VERSION 5.7 ;
BUSBITCHARS "[]" ;
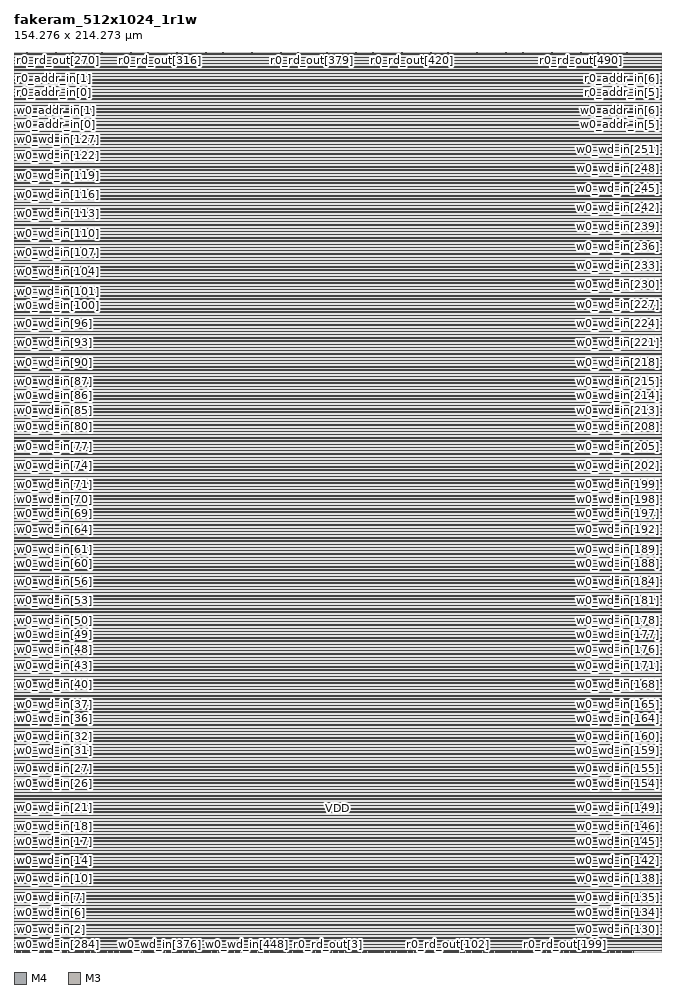
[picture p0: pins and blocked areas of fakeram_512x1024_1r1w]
MACRO fakeram_512x1024_1r1w
  FOREIGN fakeram_512x1024_1r1w 0 0 ;
  SYMMETRY X Y R90 ;
  SIZE 154.276 BY 214.273 ;
  CLASS BLOCK ;
  PIN w0_wd_in[0]
    DIRECTION INPUT ;
    USE SIGNAL ;
    SHAPE ABUTMENT ;
    PORT
      LAYER M4 ;
      RECT 0.000 0.276 0.072 0.300 ;
    END
  END w0_wd_in[0]
  PIN w0_wd_in[1]
    DIRECTION INPUT ;
    USE SIGNAL ;
    SHAPE ABUTMENT ;
    PORT
      LAYER M4 ;
      RECT 0.000 1.812 0.072 1.836 ;
    END
  END w0_wd_in[1]
  PIN w0_wd_in[2]
    DIRECTION INPUT ;
    USE SIGNAL ;
    SHAPE ABUTMENT ;
    PORT
      LAYER M4 ;
      RECT 0.000 3.348 0.072 3.372 ;
    END
  END w0_wd_in[2]
  PIN w0_wd_in[3]
    DIRECTION INPUT ;
    USE SIGNAL ;
    SHAPE ABUTMENT ;
    PORT
      LAYER M4 ;
      RECT 0.000 4.884 0.072 4.908 ;
    END
  END w0_wd_in[3]
  PIN w0_wd_in[4]
    DIRECTION INPUT ;
    USE SIGNAL ;
    SHAPE ABUTMENT ;
    PORT
      LAYER M4 ;
      RECT 0.000 6.420 0.072 6.444 ;
    END
  END w0_wd_in[4]
  PIN w0_wd_in[5]
    DIRECTION INPUT ;
    USE SIGNAL ;
    SHAPE ABUTMENT ;
    PORT
      LAYER M4 ;
      RECT 0.000 7.956 0.072 7.980 ;
    END
  END w0_wd_in[5]
  PIN w0_wd_in[6]
    DIRECTION INPUT ;
    USE SIGNAL ;
    SHAPE ABUTMENT ;
    PORT
      LAYER M4 ;
      RECT 0.000 9.492 0.072 9.516 ;
    END
  END w0_wd_in[6]
  PIN w0_wd_in[7]
    DIRECTION INPUT ;
    USE SIGNAL ;
    SHAPE ABUTMENT ;
    PORT
      LAYER M4 ;
      RECT 0.000 11.028 0.072 11.052 ;
    END
  END w0_wd_in[7]
  PIN w0_wd_in[8]
    DIRECTION INPUT ;
    USE SIGNAL ;
    SHAPE ABUTMENT ;
    PORT
      LAYER M4 ;
      RECT 0.000 12.564 0.072 12.588 ;
    END
  END w0_wd_in[8]
  PIN w0_wd_in[9]
    DIRECTION INPUT ;
    USE SIGNAL ;
    SHAPE ABUTMENT ;
    PORT
      LAYER M4 ;
      RECT 0.000 14.100 0.072 14.124 ;
    END
  END w0_wd_in[9]
  PIN w0_wd_in[10]
    DIRECTION INPUT ;
    USE SIGNAL ;
    SHAPE ABUTMENT ;
    PORT
      LAYER M4 ;
      RECT 0.000 15.636 0.072 15.660 ;
    END
  END w0_wd_in[10]
  PIN w0_wd_in[11]
    DIRECTION INPUT ;
    USE SIGNAL ;
    SHAPE ABUTMENT ;
    PORT
      LAYER M4 ;
      RECT 0.000 17.172 0.072 17.196 ;
    END
  END w0_wd_in[11]
  PIN w0_wd_in[12]
    DIRECTION INPUT ;
    USE SIGNAL ;
    SHAPE ABUTMENT ;
    PORT
      LAYER M4 ;
      RECT 0.000 18.708 0.072 18.732 ;
    END
  END w0_wd_in[12]
  PIN w0_wd_in[13]
    DIRECTION INPUT ;
    USE SIGNAL ;
    SHAPE ABUTMENT ;
    PORT
      LAYER M4 ;
      RECT 0.000 20.244 0.072 20.268 ;
    END
  END w0_wd_in[13]
  PIN w0_wd_in[14]
    DIRECTION INPUT ;
    USE SIGNAL ;
    SHAPE ABUTMENT ;
    PORT
      LAYER M4 ;
      RECT 0.000 21.780 0.072 21.804 ;
    END
  END w0_wd_in[14]
  PIN w0_wd_in[15]
    DIRECTION INPUT ;
    USE SIGNAL ;
    SHAPE ABUTMENT ;
    PORT
      LAYER M4 ;
      RECT 0.000 23.316 0.072 23.340 ;
    END
  END w0_wd_in[15]
  PIN w0_wd_in[16]
    DIRECTION INPUT ;
    USE SIGNAL ;
    SHAPE ABUTMENT ;
    PORT
      LAYER M4 ;
      RECT 0.000 24.852 0.072 24.876 ;
    END
  END w0_wd_in[16]
  PIN w0_wd_in[17]
    DIRECTION INPUT ;
    USE SIGNAL ;
    SHAPE ABUTMENT ;
    PORT
      LAYER M4 ;
      RECT 0.000 26.388 0.072 26.412 ;
    END
  END w0_wd_in[17]
  PIN w0_wd_in[18]
    DIRECTION INPUT ;
    USE SIGNAL ;
    SHAPE ABUTMENT ;
    PORT
      LAYER M4 ;
      RECT 0.000 27.924 0.072 27.948 ;
    END
  END w0_wd_in[18]
  PIN w0_wd_in[19]
    DIRECTION INPUT ;
    USE SIGNAL ;
    SHAPE ABUTMENT ;
    PORT
      LAYER M4 ;
      RECT 0.000 29.460 0.072 29.484 ;
    END
  END w0_wd_in[19]
  PIN w0_wd_in[20]
    DIRECTION INPUT ;
    USE SIGNAL ;
    SHAPE ABUTMENT ;
    PORT
      LAYER M4 ;
      RECT 0.000 30.996 0.072 31.020 ;
    END
  END w0_wd_in[20]
  PIN w0_wd_in[21]
    DIRECTION INPUT ;
    USE SIGNAL ;
    SHAPE ABUTMENT ;
    PORT
      LAYER M4 ;
      RECT 0.000 32.532 0.072 32.556 ;
    END
  END w0_wd_in[21]
  PIN w0_wd_in[22]
    DIRECTION INPUT ;
    USE SIGNAL ;
    SHAPE ABUTMENT ;
    PORT
      LAYER M4 ;
      RECT 0.000 34.068 0.072 34.092 ;
    END
  END w0_wd_in[22]
  PIN w0_wd_in[23]
    DIRECTION INPUT ;
    USE SIGNAL ;
    SHAPE ABUTMENT ;
    PORT
      LAYER M4 ;
      RECT 0.000 35.604 0.072 35.628 ;
    END
  END w0_wd_in[23]
  PIN w0_wd_in[24]
    DIRECTION INPUT ;
    USE SIGNAL ;
    SHAPE ABUTMENT ;
    PORT
      LAYER M4 ;
      RECT 0.000 37.140 0.072 37.164 ;
    END
  END w0_wd_in[24]
  PIN w0_wd_in[25]
    DIRECTION INPUT ;
    USE SIGNAL ;
    SHAPE ABUTMENT ;
    PORT
      LAYER M4 ;
      RECT 0.000 38.676 0.072 38.700 ;
    END
  END w0_wd_in[25]
  PIN w0_wd_in[26]
    DIRECTION INPUT ;
    USE SIGNAL ;
    SHAPE ABUTMENT ;
    PORT
      LAYER M4 ;
      RECT 0.000 40.212 0.072 40.236 ;
    END
  END w0_wd_in[26]
  PIN w0_wd_in[27]
    DIRECTION INPUT ;
    USE SIGNAL ;
    SHAPE ABUTMENT ;
    PORT
      LAYER M4 ;
      RECT 0.000 41.748 0.072 41.772 ;
    END
  END w0_wd_in[27]
  PIN w0_wd_in[28]
    DIRECTION INPUT ;
    USE SIGNAL ;
    SHAPE ABUTMENT ;
    PORT
      LAYER M4 ;
      RECT 0.000 43.284 0.072 43.308 ;
    END
  END w0_wd_in[28]
  PIN w0_wd_in[29]
    DIRECTION INPUT ;
    USE SIGNAL ;
    SHAPE ABUTMENT ;
    PORT
      LAYER M4 ;
      RECT 0.000 44.820 0.072 44.844 ;
    END
  END w0_wd_in[29]
  PIN w0_wd_in[30]
    DIRECTION INPUT ;
    USE SIGNAL ;
    SHAPE ABUTMENT ;
    PORT
      LAYER M4 ;
      RECT 0.000 46.356 0.072 46.380 ;
    END
  END w0_wd_in[30]
  PIN w0_wd_in[31]
    DIRECTION INPUT ;
    USE SIGNAL ;
    SHAPE ABUTMENT ;
    PORT
      LAYER M4 ;
      RECT 0.000 47.892 0.072 47.916 ;
    END
  END w0_wd_in[31]
  PIN w0_wd_in[32]
    DIRECTION INPUT ;
    USE SIGNAL ;
    SHAPE ABUTMENT ;
    PORT
      LAYER M4 ;
      RECT 0.000 49.428 0.072 49.452 ;
    END
  END w0_wd_in[32]
  PIN w0_wd_in[33]
    DIRECTION INPUT ;
    USE SIGNAL ;
    SHAPE ABUTMENT ;
    PORT
      LAYER M4 ;
      RECT 0.000 50.964 0.072 50.988 ;
    END
  END w0_wd_in[33]
  PIN w0_wd_in[34]
    DIRECTION INPUT ;
    USE SIGNAL ;
    SHAPE ABUTMENT ;
    PORT
      LAYER M4 ;
      RECT 0.000 52.500 0.072 52.524 ;
    END
  END w0_wd_in[34]
  PIN w0_wd_in[35]
    DIRECTION INPUT ;
    USE SIGNAL ;
    SHAPE ABUTMENT ;
    PORT
      LAYER M4 ;
      RECT 0.000 54.036 0.072 54.060 ;
    END
  END w0_wd_in[35]
  PIN w0_wd_in[36]
    DIRECTION INPUT ;
    USE SIGNAL ;
    SHAPE ABUTMENT ;
    PORT
      LAYER M4 ;
      RECT 0.000 55.572 0.072 55.596 ;
    END
  END w0_wd_in[36]
  PIN w0_wd_in[37]
    DIRECTION INPUT ;
    USE SIGNAL ;
    SHAPE ABUTMENT ;
    PORT
      LAYER M4 ;
      RECT 0.000 57.108 0.072 57.132 ;
    END
  END w0_wd_in[37]
  PIN w0_wd_in[38]
    DIRECTION INPUT ;
    USE SIGNAL ;
    SHAPE ABUTMENT ;
    PORT
      LAYER M4 ;
      RECT 0.000 58.644 0.072 58.668 ;
    END
  END w0_wd_in[38]
  PIN w0_wd_in[39]
    DIRECTION INPUT ;
    USE SIGNAL ;
    SHAPE ABUTMENT ;
    PORT
      LAYER M4 ;
      RECT 0.000 60.180 0.072 60.204 ;
    END
  END w0_wd_in[39]
  PIN w0_wd_in[40]
    DIRECTION INPUT ;
    USE SIGNAL ;
    SHAPE ABUTMENT ;
    PORT
      LAYER M4 ;
      RECT 0.000 61.716 0.072 61.740 ;
    END
  END w0_wd_in[40]
  PIN w0_wd_in[41]
    DIRECTION INPUT ;
    USE SIGNAL ;
    SHAPE ABUTMENT ;
    PORT
      LAYER M4 ;
      RECT 0.000 63.252 0.072 63.276 ;
    END
  END w0_wd_in[41]
  PIN w0_wd_in[42]
    DIRECTION INPUT ;
    USE SIGNAL ;
    SHAPE ABUTMENT ;
    PORT
      LAYER M4 ;
      RECT 0.000 64.788 0.072 64.812 ;
    END
  END w0_wd_in[42]
  PIN w0_wd_in[43]
    DIRECTION INPUT ;
    USE SIGNAL ;
    SHAPE ABUTMENT ;
    PORT
      LAYER M4 ;
      RECT 0.000 66.324 0.072 66.348 ;
    END
  END w0_wd_in[43]
  PIN w0_wd_in[44]
    DIRECTION INPUT ;
    USE SIGNAL ;
    SHAPE ABUTMENT ;
    PORT
      LAYER M4 ;
      RECT 0.000 67.860 0.072 67.884 ;
    END
  END w0_wd_in[44]
  PIN w0_wd_in[45]
    DIRECTION INPUT ;
    USE SIGNAL ;
    SHAPE ABUTMENT ;
    PORT
      LAYER M4 ;
      RECT 0.000 69.396 0.072 69.420 ;
    END
  END w0_wd_in[45]
  PIN w0_wd_in[46]
    DIRECTION INPUT ;
    USE SIGNAL ;
    SHAPE ABUTMENT ;
    PORT
      LAYER M4 ;
      RECT 0.000 70.932 0.072 70.956 ;
    END
  END w0_wd_in[46]
  PIN w0_wd_in[47]
    DIRECTION INPUT ;
    USE SIGNAL ;
    SHAPE ABUTMENT ;
    PORT
      LAYER M4 ;
      RECT 0.000 72.468 0.072 72.492 ;
    END
  END w0_wd_in[47]
  PIN w0_wd_in[48]
    DIRECTION INPUT ;
    USE SIGNAL ;
    SHAPE ABUTMENT ;
    PORT
      LAYER M4 ;
      RECT 0.000 74.004 0.072 74.028 ;
    END
  END w0_wd_in[48]
  PIN w0_wd_in[49]
    DIRECTION INPUT ;
    USE SIGNAL ;
    SHAPE ABUTMENT ;
    PORT
      LAYER M4 ;
      RECT 0.000 75.540 0.072 75.564 ;
    END
  END w0_wd_in[49]
  PIN w0_wd_in[50]
    DIRECTION INPUT ;
    USE SIGNAL ;
    SHAPE ABUTMENT ;
    PORT
      LAYER M4 ;
      RECT 0.000 77.076 0.072 77.100 ;
    END
  END w0_wd_in[50]
  PIN w0_wd_in[51]
    DIRECTION INPUT ;
    USE SIGNAL ;
    SHAPE ABUTMENT ;
    PORT
      LAYER M4 ;
      RECT 0.000 78.612 0.072 78.636 ;
    END
  END w0_wd_in[51]
  PIN w0_wd_in[52]
    DIRECTION INPUT ;
    USE SIGNAL ;
    SHAPE ABUTMENT ;
    PORT
      LAYER M4 ;
      RECT 0.000 80.148 0.072 80.172 ;
    END
  END w0_wd_in[52]
  PIN w0_wd_in[53]
    DIRECTION INPUT ;
    USE SIGNAL ;
    SHAPE ABUTMENT ;
    PORT
      LAYER M4 ;
      RECT 0.000 81.684 0.072 81.708 ;
    END
  END w0_wd_in[53]
  PIN w0_wd_in[54]
    DIRECTION INPUT ;
    USE SIGNAL ;
    SHAPE ABUTMENT ;
    PORT
      LAYER M4 ;
      RECT 0.000 83.220 0.072 83.244 ;
    END
  END w0_wd_in[54]
  PIN w0_wd_in[55]
    DIRECTION INPUT ;
    USE SIGNAL ;
    SHAPE ABUTMENT ;
    PORT
      LAYER M4 ;
      RECT 0.000 84.756 0.072 84.780 ;
    END
  END w0_wd_in[55]
  PIN w0_wd_in[56]
    DIRECTION INPUT ;
    USE SIGNAL ;
    SHAPE ABUTMENT ;
    PORT
      LAYER M4 ;
      RECT 0.000 86.292 0.072 86.316 ;
    END
  END w0_wd_in[56]
  PIN w0_wd_in[57]
    DIRECTION INPUT ;
    USE SIGNAL ;
    SHAPE ABUTMENT ;
    PORT
      LAYER M4 ;
      RECT 0.000 87.828 0.072 87.852 ;
    END
  END w0_wd_in[57]
  PIN w0_wd_in[58]
    DIRECTION INPUT ;
    USE SIGNAL ;
    SHAPE ABUTMENT ;
    PORT
      LAYER M4 ;
      RECT 0.000 89.364 0.072 89.388 ;
    END
  END w0_wd_in[58]
  PIN w0_wd_in[59]
    DIRECTION INPUT ;
    USE SIGNAL ;
    SHAPE ABUTMENT ;
    PORT
      LAYER M4 ;
      RECT 0.000 90.900 0.072 90.924 ;
    END
  END w0_wd_in[59]
  PIN w0_wd_in[60]
    DIRECTION INPUT ;
    USE SIGNAL ;
    SHAPE ABUTMENT ;
    PORT
      LAYER M4 ;
      RECT 0.000 92.436 0.072 92.460 ;
    END
  END w0_wd_in[60]
  PIN w0_wd_in[61]
    DIRECTION INPUT ;
    USE SIGNAL ;
    SHAPE ABUTMENT ;
    PORT
      LAYER M4 ;
      RECT 0.000 93.972 0.072 93.996 ;
    END
  END w0_wd_in[61]
  PIN w0_wd_in[62]
    DIRECTION INPUT ;
    USE SIGNAL ;
    SHAPE ABUTMENT ;
    PORT
      LAYER M4 ;
      RECT 0.000 95.508 0.072 95.532 ;
    END
  END w0_wd_in[62]
  PIN w0_wd_in[63]
    DIRECTION INPUT ;
    USE SIGNAL ;
    SHAPE ABUTMENT ;
    PORT
      LAYER M4 ;
      RECT 0.000 97.044 0.072 97.068 ;
    END
  END w0_wd_in[63]
  PIN w0_wd_in[64]
    DIRECTION INPUT ;
    USE SIGNAL ;
    SHAPE ABUTMENT ;
    PORT
      LAYER M4 ;
      RECT 0.000 98.580 0.072 98.604 ;
    END
  END w0_wd_in[64]
  PIN w0_wd_in[65]
    DIRECTION INPUT ;
    USE SIGNAL ;
    SHAPE ABUTMENT ;
    PORT
      LAYER M4 ;
      RECT 0.000 100.116 0.072 100.140 ;
    END
  END w0_wd_in[65]
  PIN w0_wd_in[66]
    DIRECTION INPUT ;
    USE SIGNAL ;
    SHAPE ABUTMENT ;
    PORT
      LAYER M4 ;
      RECT 0.000 101.652 0.072 101.676 ;
    END
  END w0_wd_in[66]
  PIN w0_wd_in[67]
    DIRECTION INPUT ;
    USE SIGNAL ;
    SHAPE ABUTMENT ;
    PORT
      LAYER M4 ;
      RECT 0.000 103.188 0.072 103.212 ;
    END
  END w0_wd_in[67]
  PIN w0_wd_in[68]
    DIRECTION INPUT ;
    USE SIGNAL ;
    SHAPE ABUTMENT ;
    PORT
      LAYER M4 ;
      RECT 0.000 104.724 0.072 104.748 ;
    END
  END w0_wd_in[68]
  PIN w0_wd_in[69]
    DIRECTION INPUT ;
    USE SIGNAL ;
    SHAPE ABUTMENT ;
    PORT
      LAYER M4 ;
      RECT 0.000 106.260 0.072 106.284 ;
    END
  END w0_wd_in[69]
  PIN w0_wd_in[70]
    DIRECTION INPUT ;
    USE SIGNAL ;
    SHAPE ABUTMENT ;
    PORT
      LAYER M4 ;
      RECT 0.000 107.796 0.072 107.820 ;
    END
  END w0_wd_in[70]
  PIN w0_wd_in[71]
    DIRECTION INPUT ;
    USE SIGNAL ;
    SHAPE ABUTMENT ;
    PORT
      LAYER M4 ;
      RECT 0.000 109.332 0.072 109.356 ;
    END
  END w0_wd_in[71]
  PIN w0_wd_in[72]
    DIRECTION INPUT ;
    USE SIGNAL ;
    SHAPE ABUTMENT ;
    PORT
      LAYER M4 ;
      RECT 0.000 110.868 0.072 110.892 ;
    END
  END w0_wd_in[72]
  PIN w0_wd_in[73]
    DIRECTION INPUT ;
    USE SIGNAL ;
    SHAPE ABUTMENT ;
    PORT
      LAYER M4 ;
      RECT 0.000 112.404 0.072 112.428 ;
    END
  END w0_wd_in[73]
  PIN w0_wd_in[74]
    DIRECTION INPUT ;
    USE SIGNAL ;
    SHAPE ABUTMENT ;
    PORT
      LAYER M4 ;
      RECT 0.000 113.940 0.072 113.964 ;
    END
  END w0_wd_in[74]
  PIN w0_wd_in[75]
    DIRECTION INPUT ;
    USE SIGNAL ;
    SHAPE ABUTMENT ;
    PORT
      LAYER M4 ;
      RECT 0.000 115.476 0.072 115.500 ;
    END
  END w0_wd_in[75]
  PIN w0_wd_in[76]
    DIRECTION INPUT ;
    USE SIGNAL ;
    SHAPE ABUTMENT ;
    PORT
      LAYER M4 ;
      RECT 0.000 117.012 0.072 117.036 ;
    END
  END w0_wd_in[76]
  PIN w0_wd_in[77]
    DIRECTION INPUT ;
    USE SIGNAL ;
    SHAPE ABUTMENT ;
    PORT
      LAYER M4 ;
      RECT 0.000 118.548 0.072 118.572 ;
    END
  END w0_wd_in[77]
  PIN w0_wd_in[78]
    DIRECTION INPUT ;
    USE SIGNAL ;
    SHAPE ABUTMENT ;
    PORT
      LAYER M4 ;
      RECT 0.000 120.084 0.072 120.108 ;
    END
  END w0_wd_in[78]
  PIN w0_wd_in[79]
    DIRECTION INPUT ;
    USE SIGNAL ;
    SHAPE ABUTMENT ;
    PORT
      LAYER M4 ;
      RECT 0.000 121.620 0.072 121.644 ;
    END
  END w0_wd_in[79]
  PIN w0_wd_in[80]
    DIRECTION INPUT ;
    USE SIGNAL ;
    SHAPE ABUTMENT ;
    PORT
      LAYER M4 ;
      RECT 0.000 123.156 0.072 123.180 ;
    END
  END w0_wd_in[80]
  PIN w0_wd_in[81]
    DIRECTION INPUT ;
    USE SIGNAL ;
    SHAPE ABUTMENT ;
    PORT
      LAYER M4 ;
      RECT 0.000 124.692 0.072 124.716 ;
    END
  END w0_wd_in[81]
  PIN w0_wd_in[82]
    DIRECTION INPUT ;
    USE SIGNAL ;
    SHAPE ABUTMENT ;
    PORT
      LAYER M4 ;
      RECT 0.000 126.228 0.072 126.252 ;
    END
  END w0_wd_in[82]
  PIN w0_wd_in[83]
    DIRECTION INPUT ;
    USE SIGNAL ;
    SHAPE ABUTMENT ;
    PORT
      LAYER M4 ;
      RECT 0.000 127.764 0.072 127.788 ;
    END
  END w0_wd_in[83]
  PIN w0_wd_in[84]
    DIRECTION INPUT ;
    USE SIGNAL ;
    SHAPE ABUTMENT ;
    PORT
      LAYER M4 ;
      RECT 0.000 129.300 0.072 129.324 ;
    END
  END w0_wd_in[84]
  PIN w0_wd_in[85]
    DIRECTION INPUT ;
    USE SIGNAL ;
    SHAPE ABUTMENT ;
    PORT
      LAYER M4 ;
      RECT 0.000 130.836 0.072 130.860 ;
    END
  END w0_wd_in[85]
  PIN w0_wd_in[86]
    DIRECTION INPUT ;
    USE SIGNAL ;
    SHAPE ABUTMENT ;
    PORT
      LAYER M4 ;
      RECT 0.000 132.372 0.072 132.396 ;
    END
  END w0_wd_in[86]
  PIN w0_wd_in[87]
    DIRECTION INPUT ;
    USE SIGNAL ;
    SHAPE ABUTMENT ;
    PORT
      LAYER M4 ;
      RECT 0.000 133.908 0.072 133.932 ;
    END
  END w0_wd_in[87]
  PIN w0_wd_in[88]
    DIRECTION INPUT ;
    USE SIGNAL ;
    SHAPE ABUTMENT ;
    PORT
      LAYER M4 ;
      RECT 0.000 135.444 0.072 135.468 ;
    END
  END w0_wd_in[88]
  PIN w0_wd_in[89]
    DIRECTION INPUT ;
    USE SIGNAL ;
    SHAPE ABUTMENT ;
    PORT
      LAYER M4 ;
      RECT 0.000 136.980 0.072 137.004 ;
    END
  END w0_wd_in[89]
  PIN w0_wd_in[90]
    DIRECTION INPUT ;
    USE SIGNAL ;
    SHAPE ABUTMENT ;
    PORT
      LAYER M4 ;
      RECT 0.000 138.516 0.072 138.540 ;
    END
  END w0_wd_in[90]
  PIN w0_wd_in[91]
    DIRECTION INPUT ;
    USE SIGNAL ;
    SHAPE ABUTMENT ;
    PORT
      LAYER M4 ;
      RECT 0.000 140.052 0.072 140.076 ;
    END
  END w0_wd_in[91]
  PIN w0_wd_in[92]
    DIRECTION INPUT ;
    USE SIGNAL ;
    SHAPE ABUTMENT ;
    PORT
      LAYER M4 ;
      RECT 0.000 141.588 0.072 141.612 ;
    END
  END w0_wd_in[92]
  PIN w0_wd_in[93]
    DIRECTION INPUT ;
    USE SIGNAL ;
    SHAPE ABUTMENT ;
    PORT
      LAYER M4 ;
      RECT 0.000 143.124 0.072 143.148 ;
    END
  END w0_wd_in[93]
  PIN w0_wd_in[94]
    DIRECTION INPUT ;
    USE SIGNAL ;
    SHAPE ABUTMENT ;
    PORT
      LAYER M4 ;
      RECT 0.000 144.660 0.072 144.684 ;
    END
  END w0_wd_in[94]
  PIN w0_wd_in[95]
    DIRECTION INPUT ;
    USE SIGNAL ;
    SHAPE ABUTMENT ;
    PORT
      LAYER M4 ;
      RECT 0.000 146.196 0.072 146.220 ;
    END
  END w0_wd_in[95]
  PIN w0_wd_in[96]
    DIRECTION INPUT ;
    USE SIGNAL ;
    SHAPE ABUTMENT ;
    PORT
      LAYER M4 ;
      RECT 0.000 147.732 0.072 147.756 ;
    END
  END w0_wd_in[96]
  PIN w0_wd_in[97]
    DIRECTION INPUT ;
    USE SIGNAL ;
    SHAPE ABUTMENT ;
    PORT
      LAYER M4 ;
      RECT 0.000 149.268 0.072 149.292 ;
    END
  END w0_wd_in[97]
  PIN w0_wd_in[98]
    DIRECTION INPUT ;
    USE SIGNAL ;
    SHAPE ABUTMENT ;
    PORT
      LAYER M4 ;
      RECT 0.000 150.804 0.072 150.828 ;
    END
  END w0_wd_in[98]
  PIN w0_wd_in[99]
    DIRECTION INPUT ;
    USE SIGNAL ;
    SHAPE ABUTMENT ;
    PORT
      LAYER M4 ;
      RECT 0.000 152.340 0.072 152.364 ;
    END
  END w0_wd_in[99]
  PIN w0_wd_in[100]
    DIRECTION INPUT ;
    USE SIGNAL ;
    SHAPE ABUTMENT ;
    PORT
      LAYER M4 ;
      RECT 0.000 153.876 0.072 153.900 ;
    END
  END w0_wd_in[100]
  PIN w0_wd_in[101]
    DIRECTION INPUT ;
    USE SIGNAL ;
    SHAPE ABUTMENT ;
    PORT
      LAYER M4 ;
      RECT 0.000 155.412 0.072 155.436 ;
    END
  END w0_wd_in[101]
  PIN w0_wd_in[102]
    DIRECTION INPUT ;
    USE SIGNAL ;
    SHAPE ABUTMENT ;
    PORT
      LAYER M4 ;
      RECT 0.000 156.948 0.072 156.972 ;
    END
  END w0_wd_in[102]
  PIN w0_wd_in[103]
    DIRECTION INPUT ;
    USE SIGNAL ;
    SHAPE ABUTMENT ;
    PORT
      LAYER M4 ;
      RECT 0.000 158.484 0.072 158.508 ;
    END
  END w0_wd_in[103]
  PIN w0_wd_in[104]
    DIRECTION INPUT ;
    USE SIGNAL ;
    SHAPE ABUTMENT ;
    PORT
      LAYER M4 ;
      RECT 0.000 160.020 0.072 160.044 ;
    END
  END w0_wd_in[104]
  PIN w0_wd_in[105]
    DIRECTION INPUT ;
    USE SIGNAL ;
    SHAPE ABUTMENT ;
    PORT
      LAYER M4 ;
      RECT 0.000 161.556 0.072 161.580 ;
    END
  END w0_wd_in[105]
  PIN w0_wd_in[106]
    DIRECTION INPUT ;
    USE SIGNAL ;
    SHAPE ABUTMENT ;
    PORT
      LAYER M4 ;
      RECT 0.000 163.092 0.072 163.116 ;
    END
  END w0_wd_in[106]
  PIN w0_wd_in[107]
    DIRECTION INPUT ;
    USE SIGNAL ;
    SHAPE ABUTMENT ;
    PORT
      LAYER M4 ;
      RECT 0.000 164.628 0.072 164.652 ;
    END
  END w0_wd_in[107]
  PIN w0_wd_in[108]
    DIRECTION INPUT ;
    USE SIGNAL ;
    SHAPE ABUTMENT ;
    PORT
      LAYER M4 ;
      RECT 0.000 166.164 0.072 166.188 ;
    END
  END w0_wd_in[108]
  PIN w0_wd_in[109]
    DIRECTION INPUT ;
    USE SIGNAL ;
    SHAPE ABUTMENT ;
    PORT
      LAYER M4 ;
      RECT 0.000 167.700 0.072 167.724 ;
    END
  END w0_wd_in[109]
  PIN w0_wd_in[110]
    DIRECTION INPUT ;
    USE SIGNAL ;
    SHAPE ABUTMENT ;
    PORT
      LAYER M4 ;
      RECT 0.000 169.236 0.072 169.260 ;
    END
  END w0_wd_in[110]
  PIN w0_wd_in[111]
    DIRECTION INPUT ;
    USE SIGNAL ;
    SHAPE ABUTMENT ;
    PORT
      LAYER M4 ;
      RECT 0.000 170.772 0.072 170.796 ;
    END
  END w0_wd_in[111]
  PIN w0_wd_in[112]
    DIRECTION INPUT ;
    USE SIGNAL ;
    SHAPE ABUTMENT ;
    PORT
      LAYER M4 ;
      RECT 0.000 172.308 0.072 172.332 ;
    END
  END w0_wd_in[112]
  PIN w0_wd_in[113]
    DIRECTION INPUT ;
    USE SIGNAL ;
    SHAPE ABUTMENT ;
    PORT
      LAYER M4 ;
      RECT 0.000 173.844 0.072 173.868 ;
    END
  END w0_wd_in[113]
  PIN w0_wd_in[114]
    DIRECTION INPUT ;
    USE SIGNAL ;
    SHAPE ABUTMENT ;
    PORT
      LAYER M4 ;
      RECT 0.000 175.380 0.072 175.404 ;
    END
  END w0_wd_in[114]
  PIN w0_wd_in[115]
    DIRECTION INPUT ;
    USE SIGNAL ;
    SHAPE ABUTMENT ;
    PORT
      LAYER M4 ;
      RECT 0.000 176.916 0.072 176.940 ;
    END
  END w0_wd_in[115]
  PIN w0_wd_in[116]
    DIRECTION INPUT ;
    USE SIGNAL ;
    SHAPE ABUTMENT ;
    PORT
      LAYER M4 ;
      RECT 0.000 178.452 0.072 178.476 ;
    END
  END w0_wd_in[116]
  PIN w0_wd_in[117]
    DIRECTION INPUT ;
    USE SIGNAL ;
    SHAPE ABUTMENT ;
    PORT
      LAYER M4 ;
      RECT 0.000 179.988 0.072 180.012 ;
    END
  END w0_wd_in[117]
  PIN w0_wd_in[118]
    DIRECTION INPUT ;
    USE SIGNAL ;
    SHAPE ABUTMENT ;
    PORT
      LAYER M4 ;
      RECT 0.000 181.524 0.072 181.548 ;
    END
  END w0_wd_in[118]
  PIN w0_wd_in[119]
    DIRECTION INPUT ;
    USE SIGNAL ;
    SHAPE ABUTMENT ;
    PORT
      LAYER M4 ;
      RECT 0.000 183.060 0.072 183.084 ;
    END
  END w0_wd_in[119]
  PIN w0_wd_in[120]
    DIRECTION INPUT ;
    USE SIGNAL ;
    SHAPE ABUTMENT ;
    PORT
      LAYER M4 ;
      RECT 0.000 184.596 0.072 184.620 ;
    END
  END w0_wd_in[120]
  PIN w0_wd_in[121]
    DIRECTION INPUT ;
    USE SIGNAL ;
    SHAPE ABUTMENT ;
    PORT
      LAYER M4 ;
      RECT 0.000 186.132 0.072 186.156 ;
    END
  END w0_wd_in[121]
  PIN w0_wd_in[122]
    DIRECTION INPUT ;
    USE SIGNAL ;
    SHAPE ABUTMENT ;
    PORT
      LAYER M4 ;
      RECT 0.000 187.668 0.072 187.692 ;
    END
  END w0_wd_in[122]
  PIN w0_wd_in[123]
    DIRECTION INPUT ;
    USE SIGNAL ;
    SHAPE ABUTMENT ;
    PORT
      LAYER M4 ;
      RECT 0.000 189.204 0.072 189.228 ;
    END
  END w0_wd_in[123]
  PIN w0_wd_in[124]
    DIRECTION INPUT ;
    USE SIGNAL ;
    SHAPE ABUTMENT ;
    PORT
      LAYER M4 ;
      RECT 0.000 190.740 0.072 190.764 ;
    END
  END w0_wd_in[124]
  PIN w0_wd_in[125]
    DIRECTION INPUT ;
    USE SIGNAL ;
    SHAPE ABUTMENT ;
    PORT
      LAYER M4 ;
      RECT 0.000 192.276 0.072 192.300 ;
    END
  END w0_wd_in[125]
  PIN w0_wd_in[126]
    DIRECTION INPUT ;
    USE SIGNAL ;
    SHAPE ABUTMENT ;
    PORT
      LAYER M4 ;
      RECT 0.000 193.812 0.072 193.836 ;
    END
  END w0_wd_in[126]
  PIN w0_wd_in[127]
    DIRECTION INPUT ;
    USE SIGNAL ;
    SHAPE ABUTMENT ;
    PORT
      LAYER M4 ;
      RECT 0.000 195.348 0.072 195.372 ;
    END
  END w0_wd_in[127]
  PIN w0_wd_in[128]
    DIRECTION INPUT ;
    USE SIGNAL ;
    SHAPE ABUTMENT ;
    PORT
      LAYER M4 ;
      RECT 154.204 0.276 154.276 0.300 ;
    END
  END w0_wd_in[128]
  PIN w0_wd_in[129]
    DIRECTION INPUT ;
    USE SIGNAL ;
    SHAPE ABUTMENT ;
    PORT
      LAYER M4 ;
      RECT 154.204 1.812 154.276 1.836 ;
    END
  END w0_wd_in[129]
  PIN w0_wd_in[130]
    DIRECTION INPUT ;
    USE SIGNAL ;
    SHAPE ABUTMENT ;
    PORT
      LAYER M4 ;
      RECT 154.204 3.348 154.276 3.372 ;
    END
  END w0_wd_in[130]
  PIN w0_wd_in[131]
    DIRECTION INPUT ;
    USE SIGNAL ;
    SHAPE ABUTMENT ;
    PORT
      LAYER M4 ;
      RECT 154.204 4.884 154.276 4.908 ;
    END
  END w0_wd_in[131]
  PIN w0_wd_in[132]
    DIRECTION INPUT ;
    USE SIGNAL ;
    SHAPE ABUTMENT ;
    PORT
      LAYER M4 ;
      RECT 154.204 6.420 154.276 6.444 ;
    END
  END w0_wd_in[132]
  PIN w0_wd_in[133]
    DIRECTION INPUT ;
    USE SIGNAL ;
    SHAPE ABUTMENT ;
    PORT
      LAYER M4 ;
      RECT 154.204 7.956 154.276 7.980 ;
    END
  END w0_wd_in[133]
  PIN w0_wd_in[134]
    DIRECTION INPUT ;
    USE SIGNAL ;
    SHAPE ABUTMENT ;
    PORT
      LAYER M4 ;
      RECT 154.204 9.492 154.276 9.516 ;
    END
  END w0_wd_in[134]
  PIN w0_wd_in[135]
    DIRECTION INPUT ;
    USE SIGNAL ;
    SHAPE ABUTMENT ;
    PORT
      LAYER M4 ;
      RECT 154.204 11.028 154.276 11.052 ;
    END
  END w0_wd_in[135]
  PIN w0_wd_in[136]
    DIRECTION INPUT ;
    USE SIGNAL ;
    SHAPE ABUTMENT ;
    PORT
      LAYER M4 ;
      RECT 154.204 12.564 154.276 12.588 ;
    END
  END w0_wd_in[136]
  PIN w0_wd_in[137]
    DIRECTION INPUT ;
    USE SIGNAL ;
    SHAPE ABUTMENT ;
    PORT
      LAYER M4 ;
      RECT 154.204 14.100 154.276 14.124 ;
    END
  END w0_wd_in[137]
  PIN w0_wd_in[138]
    DIRECTION INPUT ;
    USE SIGNAL ;
    SHAPE ABUTMENT ;
    PORT
      LAYER M4 ;
      RECT 154.204 15.636 154.276 15.660 ;
    END
  END w0_wd_in[138]
  PIN w0_wd_in[139]
    DIRECTION INPUT ;
    USE SIGNAL ;
    SHAPE ABUTMENT ;
    PORT
      LAYER M4 ;
      RECT 154.204 17.172 154.276 17.196 ;
    END
  END w0_wd_in[139]
  PIN w0_wd_in[140]
    DIRECTION INPUT ;
    USE SIGNAL ;
    SHAPE ABUTMENT ;
    PORT
      LAYER M4 ;
      RECT 154.204 18.708 154.276 18.732 ;
    END
  END w0_wd_in[140]
  PIN w0_wd_in[141]
    DIRECTION INPUT ;
    USE SIGNAL ;
    SHAPE ABUTMENT ;
    PORT
      LAYER M4 ;
      RECT 154.204 20.244 154.276 20.268 ;
    END
  END w0_wd_in[141]
  PIN w0_wd_in[142]
    DIRECTION INPUT ;
    USE SIGNAL ;
    SHAPE ABUTMENT ;
    PORT
      LAYER M4 ;
      RECT 154.204 21.780 154.276 21.804 ;
    END
  END w0_wd_in[142]
  PIN w0_wd_in[143]
    DIRECTION INPUT ;
    USE SIGNAL ;
    SHAPE ABUTMENT ;
    PORT
      LAYER M4 ;
      RECT 154.204 23.316 154.276 23.340 ;
    END
  END w0_wd_in[143]
  PIN w0_wd_in[144]
    DIRECTION INPUT ;
    USE SIGNAL ;
    SHAPE ABUTMENT ;
    PORT
      LAYER M4 ;
      RECT 154.204 24.852 154.276 24.876 ;
    END
  END w0_wd_in[144]
  PIN w0_wd_in[145]
    DIRECTION INPUT ;
    USE SIGNAL ;
    SHAPE ABUTMENT ;
    PORT
      LAYER M4 ;
      RECT 154.204 26.388 154.276 26.412 ;
    END
  END w0_wd_in[145]
  PIN w0_wd_in[146]
    DIRECTION INPUT ;
    USE SIGNAL ;
    SHAPE ABUTMENT ;
    PORT
      LAYER M4 ;
      RECT 154.204 27.924 154.276 27.948 ;
    END
  END w0_wd_in[146]
  PIN w0_wd_in[147]
    DIRECTION INPUT ;
    USE SIGNAL ;
    SHAPE ABUTMENT ;
    PORT
      LAYER M4 ;
      RECT 154.204 29.460 154.276 29.484 ;
    END
  END w0_wd_in[147]
  PIN w0_wd_in[148]
    DIRECTION INPUT ;
    USE SIGNAL ;
    SHAPE ABUTMENT ;
    PORT
      LAYER M4 ;
      RECT 154.204 30.996 154.276 31.020 ;
    END
  END w0_wd_in[148]
  PIN w0_wd_in[149]
    DIRECTION INPUT ;
    USE SIGNAL ;
    SHAPE ABUTMENT ;
    PORT
      LAYER M4 ;
      RECT 154.204 32.532 154.276 32.556 ;
    END
  END w0_wd_in[149]
  PIN w0_wd_in[150]
    DIRECTION INPUT ;
    USE SIGNAL ;
    SHAPE ABUTMENT ;
    PORT
      LAYER M4 ;
      RECT 154.204 34.068 154.276 34.092 ;
    END
  END w0_wd_in[150]
  PIN w0_wd_in[151]
    DIRECTION INPUT ;
    USE SIGNAL ;
    SHAPE ABUTMENT ;
    PORT
      LAYER M4 ;
      RECT 154.204 35.604 154.276 35.628 ;
    END
  END w0_wd_in[151]
  PIN w0_wd_in[152]
    DIRECTION INPUT ;
    USE SIGNAL ;
    SHAPE ABUTMENT ;
    PORT
      LAYER M4 ;
      RECT 154.204 37.140 154.276 37.164 ;
    END
  END w0_wd_in[152]
  PIN w0_wd_in[153]
    DIRECTION INPUT ;
    USE SIGNAL ;
    SHAPE ABUTMENT ;
    PORT
      LAYER M4 ;
      RECT 154.204 38.676 154.276 38.700 ;
    END
  END w0_wd_in[153]
  PIN w0_wd_in[154]
    DIRECTION INPUT ;
    USE SIGNAL ;
    SHAPE ABUTMENT ;
    PORT
      LAYER M4 ;
      RECT 154.204 40.212 154.276 40.236 ;
    END
  END w0_wd_in[154]
  PIN w0_wd_in[155]
    DIRECTION INPUT ;
    USE SIGNAL ;
    SHAPE ABUTMENT ;
    PORT
      LAYER M4 ;
      RECT 154.204 41.748 154.276 41.772 ;
    END
  END w0_wd_in[155]
  PIN w0_wd_in[156]
    DIRECTION INPUT ;
    USE SIGNAL ;
    SHAPE ABUTMENT ;
    PORT
      LAYER M4 ;
      RECT 154.204 43.284 154.276 43.308 ;
    END
  END w0_wd_in[156]
  PIN w0_wd_in[157]
    DIRECTION INPUT ;
    USE SIGNAL ;
    SHAPE ABUTMENT ;
    PORT
      LAYER M4 ;
      RECT 154.204 44.820 154.276 44.844 ;
    END
  END w0_wd_in[157]
  PIN w0_wd_in[158]
    DIRECTION INPUT ;
    USE SIGNAL ;
    SHAPE ABUTMENT ;
    PORT
      LAYER M4 ;
      RECT 154.204 46.356 154.276 46.380 ;
    END
  END w0_wd_in[158]
  PIN w0_wd_in[159]
    DIRECTION INPUT ;
    USE SIGNAL ;
    SHAPE ABUTMENT ;
    PORT
      LAYER M4 ;
      RECT 154.204 47.892 154.276 47.916 ;
    END
  END w0_wd_in[159]
  PIN w0_wd_in[160]
    DIRECTION INPUT ;
    USE SIGNAL ;
    SHAPE ABUTMENT ;
    PORT
      LAYER M4 ;
      RECT 154.204 49.428 154.276 49.452 ;
    END
  END w0_wd_in[160]
  PIN w0_wd_in[161]
    DIRECTION INPUT ;
    USE SIGNAL ;
    SHAPE ABUTMENT ;
    PORT
      LAYER M4 ;
      RECT 154.204 50.964 154.276 50.988 ;
    END
  END w0_wd_in[161]
  PIN w0_wd_in[162]
    DIRECTION INPUT ;
    USE SIGNAL ;
    SHAPE ABUTMENT ;
    PORT
      LAYER M4 ;
      RECT 154.204 52.500 154.276 52.524 ;
    END
  END w0_wd_in[162]
  PIN w0_wd_in[163]
    DIRECTION INPUT ;
    USE SIGNAL ;
    SHAPE ABUTMENT ;
    PORT
      LAYER M4 ;
      RECT 154.204 54.036 154.276 54.060 ;
    END
  END w0_wd_in[163]
  PIN w0_wd_in[164]
    DIRECTION INPUT ;
    USE SIGNAL ;
    SHAPE ABUTMENT ;
    PORT
      LAYER M4 ;
      RECT 154.204 55.572 154.276 55.596 ;
    END
  END w0_wd_in[164]
  PIN w0_wd_in[165]
    DIRECTION INPUT ;
    USE SIGNAL ;
    SHAPE ABUTMENT ;
    PORT
      LAYER M4 ;
      RECT 154.204 57.108 154.276 57.132 ;
    END
  END w0_wd_in[165]
  PIN w0_wd_in[166]
    DIRECTION INPUT ;
    USE SIGNAL ;
    SHAPE ABUTMENT ;
    PORT
      LAYER M4 ;
      RECT 154.204 58.644 154.276 58.668 ;
    END
  END w0_wd_in[166]
  PIN w0_wd_in[167]
    DIRECTION INPUT ;
    USE SIGNAL ;
    SHAPE ABUTMENT ;
    PORT
      LAYER M4 ;
      RECT 154.204 60.180 154.276 60.204 ;
    END
  END w0_wd_in[167]
  PIN w0_wd_in[168]
    DIRECTION INPUT ;
    USE SIGNAL ;
    SHAPE ABUTMENT ;
    PORT
      LAYER M4 ;
      RECT 154.204 61.716 154.276 61.740 ;
    END
  END w0_wd_in[168]
  PIN w0_wd_in[169]
    DIRECTION INPUT ;
    USE SIGNAL ;
    SHAPE ABUTMENT ;
    PORT
      LAYER M4 ;
      RECT 154.204 63.252 154.276 63.276 ;
    END
  END w0_wd_in[169]
  PIN w0_wd_in[170]
    DIRECTION INPUT ;
    USE SIGNAL ;
    SHAPE ABUTMENT ;
    PORT
      LAYER M4 ;
      RECT 154.204 64.788 154.276 64.812 ;
    END
  END w0_wd_in[170]
  PIN w0_wd_in[171]
    DIRECTION INPUT ;
    USE SIGNAL ;
    SHAPE ABUTMENT ;
    PORT
      LAYER M4 ;
      RECT 154.204 66.324 154.276 66.348 ;
    END
  END w0_wd_in[171]
  PIN w0_wd_in[172]
    DIRECTION INPUT ;
    USE SIGNAL ;
    SHAPE ABUTMENT ;
    PORT
      LAYER M4 ;
      RECT 154.204 67.860 154.276 67.884 ;
    END
  END w0_wd_in[172]
  PIN w0_wd_in[173]
    DIRECTION INPUT ;
    USE SIGNAL ;
    SHAPE ABUTMENT ;
    PORT
      LAYER M4 ;
      RECT 154.204 69.396 154.276 69.420 ;
    END
  END w0_wd_in[173]
  PIN w0_wd_in[174]
    DIRECTION INPUT ;
    USE SIGNAL ;
    SHAPE ABUTMENT ;
    PORT
      LAYER M4 ;
      RECT 154.204 70.932 154.276 70.956 ;
    END
  END w0_wd_in[174]
  PIN w0_wd_in[175]
    DIRECTION INPUT ;
    USE SIGNAL ;
    SHAPE ABUTMENT ;
    PORT
      LAYER M4 ;
      RECT 154.204 72.468 154.276 72.492 ;
    END
  END w0_wd_in[175]
  PIN w0_wd_in[176]
    DIRECTION INPUT ;
    USE SIGNAL ;
    SHAPE ABUTMENT ;
    PORT
      LAYER M4 ;
      RECT 154.204 74.004 154.276 74.028 ;
    END
  END w0_wd_in[176]
  PIN w0_wd_in[177]
    DIRECTION INPUT ;
    USE SIGNAL ;
    SHAPE ABUTMENT ;
    PORT
      LAYER M4 ;
      RECT 154.204 75.540 154.276 75.564 ;
    END
  END w0_wd_in[177]
  PIN w0_wd_in[178]
    DIRECTION INPUT ;
    USE SIGNAL ;
    SHAPE ABUTMENT ;
    PORT
      LAYER M4 ;
      RECT 154.204 77.076 154.276 77.100 ;
    END
  END w0_wd_in[178]
  PIN w0_wd_in[179]
    DIRECTION INPUT ;
    USE SIGNAL ;
    SHAPE ABUTMENT ;
    PORT
      LAYER M4 ;
      RECT 154.204 78.612 154.276 78.636 ;
    END
  END w0_wd_in[179]
  PIN w0_wd_in[180]
    DIRECTION INPUT ;
    USE SIGNAL ;
    SHAPE ABUTMENT ;
    PORT
      LAYER M4 ;
      RECT 154.204 80.148 154.276 80.172 ;
    END
  END w0_wd_in[180]
  PIN w0_wd_in[181]
    DIRECTION INPUT ;
    USE SIGNAL ;
    SHAPE ABUTMENT ;
    PORT
      LAYER M4 ;
      RECT 154.204 81.684 154.276 81.708 ;
    END
  END w0_wd_in[181]
  PIN w0_wd_in[182]
    DIRECTION INPUT ;
    USE SIGNAL ;
    SHAPE ABUTMENT ;
    PORT
      LAYER M4 ;
      RECT 154.204 83.220 154.276 83.244 ;
    END
  END w0_wd_in[182]
  PIN w0_wd_in[183]
    DIRECTION INPUT ;
    USE SIGNAL ;
    SHAPE ABUTMENT ;
    PORT
      LAYER M4 ;
      RECT 154.204 84.756 154.276 84.780 ;
    END
  END w0_wd_in[183]
  PIN w0_wd_in[184]
    DIRECTION INPUT ;
    USE SIGNAL ;
    SHAPE ABUTMENT ;
    PORT
      LAYER M4 ;
      RECT 154.204 86.292 154.276 86.316 ;
    END
  END w0_wd_in[184]
  PIN w0_wd_in[185]
    DIRECTION INPUT ;
    USE SIGNAL ;
    SHAPE ABUTMENT ;
    PORT
      LAYER M4 ;
      RECT 154.204 87.828 154.276 87.852 ;
    END
  END w0_wd_in[185]
  PIN w0_wd_in[186]
    DIRECTION INPUT ;
    USE SIGNAL ;
    SHAPE ABUTMENT ;
    PORT
      LAYER M4 ;
      RECT 154.204 89.364 154.276 89.388 ;
    END
  END w0_wd_in[186]
  PIN w0_wd_in[187]
    DIRECTION INPUT ;
    USE SIGNAL ;
    SHAPE ABUTMENT ;
    PORT
      LAYER M4 ;
      RECT 154.204 90.900 154.276 90.924 ;
    END
  END w0_wd_in[187]
  PIN w0_wd_in[188]
    DIRECTION INPUT ;
    USE SIGNAL ;
    SHAPE ABUTMENT ;
    PORT
      LAYER M4 ;
      RECT 154.204 92.436 154.276 92.460 ;
    END
  END w0_wd_in[188]
  PIN w0_wd_in[189]
    DIRECTION INPUT ;
    USE SIGNAL ;
    SHAPE ABUTMENT ;
    PORT
      LAYER M4 ;
      RECT 154.204 93.972 154.276 93.996 ;
    END
  END w0_wd_in[189]
  PIN w0_wd_in[190]
    DIRECTION INPUT ;
    USE SIGNAL ;
    SHAPE ABUTMENT ;
    PORT
      LAYER M4 ;
      RECT 154.204 95.508 154.276 95.532 ;
    END
  END w0_wd_in[190]
  PIN w0_wd_in[191]
    DIRECTION INPUT ;
    USE SIGNAL ;
    SHAPE ABUTMENT ;
    PORT
      LAYER M4 ;
      RECT 154.204 97.044 154.276 97.068 ;
    END
  END w0_wd_in[191]
  PIN w0_wd_in[192]
    DIRECTION INPUT ;
    USE SIGNAL ;
    SHAPE ABUTMENT ;
    PORT
      LAYER M4 ;
      RECT 154.204 98.580 154.276 98.604 ;
    END
  END w0_wd_in[192]
  PIN w0_wd_in[193]
    DIRECTION INPUT ;
    USE SIGNAL ;
    SHAPE ABUTMENT ;
    PORT
      LAYER M4 ;
      RECT 154.204 100.116 154.276 100.140 ;
    END
  END w0_wd_in[193]
  PIN w0_wd_in[194]
    DIRECTION INPUT ;
    USE SIGNAL ;
    SHAPE ABUTMENT ;
    PORT
      LAYER M4 ;
      RECT 154.204 101.652 154.276 101.676 ;
    END
  END w0_wd_in[194]
  PIN w0_wd_in[195]
    DIRECTION INPUT ;
    USE SIGNAL ;
    SHAPE ABUTMENT ;
    PORT
      LAYER M4 ;
      RECT 154.204 103.188 154.276 103.212 ;
    END
  END w0_wd_in[195]
  PIN w0_wd_in[196]
    DIRECTION INPUT ;
    USE SIGNAL ;
    SHAPE ABUTMENT ;
    PORT
      LAYER M4 ;
      RECT 154.204 104.724 154.276 104.748 ;
    END
  END w0_wd_in[196]
  PIN w0_wd_in[197]
    DIRECTION INPUT ;
    USE SIGNAL ;
    SHAPE ABUTMENT ;
    PORT
      LAYER M4 ;
      RECT 154.204 106.260 154.276 106.284 ;
    END
  END w0_wd_in[197]
  PIN w0_wd_in[198]
    DIRECTION INPUT ;
    USE SIGNAL ;
    SHAPE ABUTMENT ;
    PORT
      LAYER M4 ;
      RECT 154.204 107.796 154.276 107.820 ;
    END
  END w0_wd_in[198]
  PIN w0_wd_in[199]
    DIRECTION INPUT ;
    USE SIGNAL ;
    SHAPE ABUTMENT ;
    PORT
      LAYER M4 ;
      RECT 154.204 109.332 154.276 109.356 ;
    END
  END w0_wd_in[199]
  PIN w0_wd_in[200]
    DIRECTION INPUT ;
    USE SIGNAL ;
    SHAPE ABUTMENT ;
    PORT
      LAYER M4 ;
      RECT 154.204 110.868 154.276 110.892 ;
    END
  END w0_wd_in[200]
  PIN w0_wd_in[201]
    DIRECTION INPUT ;
    USE SIGNAL ;
    SHAPE ABUTMENT ;
    PORT
      LAYER M4 ;
      RECT 154.204 112.404 154.276 112.428 ;
    END
  END w0_wd_in[201]
  PIN w0_wd_in[202]
    DIRECTION INPUT ;
    USE SIGNAL ;
    SHAPE ABUTMENT ;
    PORT
      LAYER M4 ;
      RECT 154.204 113.940 154.276 113.964 ;
    END
  END w0_wd_in[202]
  PIN w0_wd_in[203]
    DIRECTION INPUT ;
    USE SIGNAL ;
    SHAPE ABUTMENT ;
    PORT
      LAYER M4 ;
      RECT 154.204 115.476 154.276 115.500 ;
    END
  END w0_wd_in[203]
  PIN w0_wd_in[204]
    DIRECTION INPUT ;
    USE SIGNAL ;
    SHAPE ABUTMENT ;
    PORT
      LAYER M4 ;
      RECT 154.204 117.012 154.276 117.036 ;
    END
  END w0_wd_in[204]
  PIN w0_wd_in[205]
    DIRECTION INPUT ;
    USE SIGNAL ;
    SHAPE ABUTMENT ;
    PORT
      LAYER M4 ;
      RECT 154.204 118.548 154.276 118.572 ;
    END
  END w0_wd_in[205]
  PIN w0_wd_in[206]
    DIRECTION INPUT ;
    USE SIGNAL ;
    SHAPE ABUTMENT ;
    PORT
      LAYER M4 ;
      RECT 154.204 120.084 154.276 120.108 ;
    END
  END w0_wd_in[206]
  PIN w0_wd_in[207]
    DIRECTION INPUT ;
    USE SIGNAL ;
    SHAPE ABUTMENT ;
    PORT
      LAYER M4 ;
      RECT 154.204 121.620 154.276 121.644 ;
    END
  END w0_wd_in[207]
  PIN w0_wd_in[208]
    DIRECTION INPUT ;
    USE SIGNAL ;
    SHAPE ABUTMENT ;
    PORT
      LAYER M4 ;
      RECT 154.204 123.156 154.276 123.180 ;
    END
  END w0_wd_in[208]
  PIN w0_wd_in[209]
    DIRECTION INPUT ;
    USE SIGNAL ;
    SHAPE ABUTMENT ;
    PORT
      LAYER M4 ;
      RECT 154.204 124.692 154.276 124.716 ;
    END
  END w0_wd_in[209]
  PIN w0_wd_in[210]
    DIRECTION INPUT ;
    USE SIGNAL ;
    SHAPE ABUTMENT ;
    PORT
      LAYER M4 ;
      RECT 154.204 126.228 154.276 126.252 ;
    END
  END w0_wd_in[210]
  PIN w0_wd_in[211]
    DIRECTION INPUT ;
    USE SIGNAL ;
    SHAPE ABUTMENT ;
    PORT
      LAYER M4 ;
      RECT 154.204 127.764 154.276 127.788 ;
    END
  END w0_wd_in[211]
  PIN w0_wd_in[212]
    DIRECTION INPUT ;
    USE SIGNAL ;
    SHAPE ABUTMENT ;
    PORT
      LAYER M4 ;
      RECT 154.204 129.300 154.276 129.324 ;
    END
  END w0_wd_in[212]
  PIN w0_wd_in[213]
    DIRECTION INPUT ;
    USE SIGNAL ;
    SHAPE ABUTMENT ;
    PORT
      LAYER M4 ;
      RECT 154.204 130.836 154.276 130.860 ;
    END
  END w0_wd_in[213]
  PIN w0_wd_in[214]
    DIRECTION INPUT ;
    USE SIGNAL ;
    SHAPE ABUTMENT ;
    PORT
      LAYER M4 ;
      RECT 154.204 132.372 154.276 132.396 ;
    END
  END w0_wd_in[214]
  PIN w0_wd_in[215]
    DIRECTION INPUT ;
    USE SIGNAL ;
    SHAPE ABUTMENT ;
    PORT
      LAYER M4 ;
      RECT 154.204 133.908 154.276 133.932 ;
    END
  END w0_wd_in[215]
  PIN w0_wd_in[216]
    DIRECTION INPUT ;
    USE SIGNAL ;
    SHAPE ABUTMENT ;
    PORT
      LAYER M4 ;
      RECT 154.204 135.444 154.276 135.468 ;
    END
  END w0_wd_in[216]
  PIN w0_wd_in[217]
    DIRECTION INPUT ;
    USE SIGNAL ;
    SHAPE ABUTMENT ;
    PORT
      LAYER M4 ;
      RECT 154.204 136.980 154.276 137.004 ;
    END
  END w0_wd_in[217]
  PIN w0_wd_in[218]
    DIRECTION INPUT ;
    USE SIGNAL ;
    SHAPE ABUTMENT ;
    PORT
      LAYER M4 ;
      RECT 154.204 138.516 154.276 138.540 ;
    END
  END w0_wd_in[218]
  PIN w0_wd_in[219]
    DIRECTION INPUT ;
    USE SIGNAL ;
    SHAPE ABUTMENT ;
    PORT
      LAYER M4 ;
      RECT 154.204 140.052 154.276 140.076 ;
    END
  END w0_wd_in[219]
  PIN w0_wd_in[220]
    DIRECTION INPUT ;
    USE SIGNAL ;
    SHAPE ABUTMENT ;
    PORT
      LAYER M4 ;
      RECT 154.204 141.588 154.276 141.612 ;
    END
  END w0_wd_in[220]
  PIN w0_wd_in[221]
    DIRECTION INPUT ;
    USE SIGNAL ;
    SHAPE ABUTMENT ;
    PORT
      LAYER M4 ;
      RECT 154.204 143.124 154.276 143.148 ;
    END
  END w0_wd_in[221]
  PIN w0_wd_in[222]
    DIRECTION INPUT ;
    USE SIGNAL ;
    SHAPE ABUTMENT ;
    PORT
      LAYER M4 ;
      RECT 154.204 144.660 154.276 144.684 ;
    END
  END w0_wd_in[222]
  PIN w0_wd_in[223]
    DIRECTION INPUT ;
    USE SIGNAL ;
    SHAPE ABUTMENT ;
    PORT
      LAYER M4 ;
      RECT 154.204 146.196 154.276 146.220 ;
    END
  END w0_wd_in[223]
  PIN w0_wd_in[224]
    DIRECTION INPUT ;
    USE SIGNAL ;
    SHAPE ABUTMENT ;
    PORT
      LAYER M4 ;
      RECT 154.204 147.732 154.276 147.756 ;
    END
  END w0_wd_in[224]
  PIN w0_wd_in[225]
    DIRECTION INPUT ;
    USE SIGNAL ;
    SHAPE ABUTMENT ;
    PORT
      LAYER M4 ;
      RECT 154.204 149.268 154.276 149.292 ;
    END
  END w0_wd_in[225]
  PIN w0_wd_in[226]
    DIRECTION INPUT ;
    USE SIGNAL ;
    SHAPE ABUTMENT ;
    PORT
      LAYER M4 ;
      RECT 154.204 150.804 154.276 150.828 ;
    END
  END w0_wd_in[226]
  PIN w0_wd_in[227]
    DIRECTION INPUT ;
    USE SIGNAL ;
    SHAPE ABUTMENT ;
    PORT
      LAYER M4 ;
      RECT 154.204 152.340 154.276 152.364 ;
    END
  END w0_wd_in[227]
  PIN w0_wd_in[228]
    DIRECTION INPUT ;
    USE SIGNAL ;
    SHAPE ABUTMENT ;
    PORT
      LAYER M4 ;
      RECT 154.204 153.876 154.276 153.900 ;
    END
  END w0_wd_in[228]
  PIN w0_wd_in[229]
    DIRECTION INPUT ;
    USE SIGNAL ;
    SHAPE ABUTMENT ;
    PORT
      LAYER M4 ;
      RECT 154.204 155.412 154.276 155.436 ;
    END
  END w0_wd_in[229]
  PIN w0_wd_in[230]
    DIRECTION INPUT ;
    USE SIGNAL ;
    SHAPE ABUTMENT ;
    PORT
      LAYER M4 ;
      RECT 154.204 156.948 154.276 156.972 ;
    END
  END w0_wd_in[230]
  PIN w0_wd_in[231]
    DIRECTION INPUT ;
    USE SIGNAL ;
    SHAPE ABUTMENT ;
    PORT
      LAYER M4 ;
      RECT 154.204 158.484 154.276 158.508 ;
    END
  END w0_wd_in[231]
  PIN w0_wd_in[232]
    DIRECTION INPUT ;
    USE SIGNAL ;
    SHAPE ABUTMENT ;
    PORT
      LAYER M4 ;
      RECT 154.204 160.020 154.276 160.044 ;
    END
  END w0_wd_in[232]
  PIN w0_wd_in[233]
    DIRECTION INPUT ;
    USE SIGNAL ;
    SHAPE ABUTMENT ;
    PORT
      LAYER M4 ;
      RECT 154.204 161.556 154.276 161.580 ;
    END
  END w0_wd_in[233]
  PIN w0_wd_in[234]
    DIRECTION INPUT ;
    USE SIGNAL ;
    SHAPE ABUTMENT ;
    PORT
      LAYER M4 ;
      RECT 154.204 163.092 154.276 163.116 ;
    END
  END w0_wd_in[234]
  PIN w0_wd_in[235]
    DIRECTION INPUT ;
    USE SIGNAL ;
    SHAPE ABUTMENT ;
    PORT
      LAYER M4 ;
      RECT 154.204 164.628 154.276 164.652 ;
    END
  END w0_wd_in[235]
  PIN w0_wd_in[236]
    DIRECTION INPUT ;
    USE SIGNAL ;
    SHAPE ABUTMENT ;
    PORT
      LAYER M4 ;
      RECT 154.204 166.164 154.276 166.188 ;
    END
  END w0_wd_in[236]
  PIN w0_wd_in[237]
    DIRECTION INPUT ;
    USE SIGNAL ;
    SHAPE ABUTMENT ;
    PORT
      LAYER M4 ;
      RECT 154.204 167.700 154.276 167.724 ;
    END
  END w0_wd_in[237]
  PIN w0_wd_in[238]
    DIRECTION INPUT ;
    USE SIGNAL ;
    SHAPE ABUTMENT ;
    PORT
      LAYER M4 ;
      RECT 154.204 169.236 154.276 169.260 ;
    END
  END w0_wd_in[238]
  PIN w0_wd_in[239]
    DIRECTION INPUT ;
    USE SIGNAL ;
    SHAPE ABUTMENT ;
    PORT
      LAYER M4 ;
      RECT 154.204 170.772 154.276 170.796 ;
    END
  END w0_wd_in[239]
  PIN w0_wd_in[240]
    DIRECTION INPUT ;
    USE SIGNAL ;
    SHAPE ABUTMENT ;
    PORT
      LAYER M4 ;
      RECT 154.204 172.308 154.276 172.332 ;
    END
  END w0_wd_in[240]
  PIN w0_wd_in[241]
    DIRECTION INPUT ;
    USE SIGNAL ;
    SHAPE ABUTMENT ;
    PORT
      LAYER M4 ;
      RECT 154.204 173.844 154.276 173.868 ;
    END
  END w0_wd_in[241]
  PIN w0_wd_in[242]
    DIRECTION INPUT ;
    USE SIGNAL ;
    SHAPE ABUTMENT ;
    PORT
      LAYER M4 ;
      RECT 154.204 175.380 154.276 175.404 ;
    END
  END w0_wd_in[242]
  PIN w0_wd_in[243]
    DIRECTION INPUT ;
    USE SIGNAL ;
    SHAPE ABUTMENT ;
    PORT
      LAYER M4 ;
      RECT 154.204 176.916 154.276 176.940 ;
    END
  END w0_wd_in[243]
  PIN w0_wd_in[244]
    DIRECTION INPUT ;
    USE SIGNAL ;
    SHAPE ABUTMENT ;
    PORT
      LAYER M4 ;
      RECT 154.204 178.452 154.276 178.476 ;
    END
  END w0_wd_in[244]
  PIN w0_wd_in[245]
    DIRECTION INPUT ;
    USE SIGNAL ;
    SHAPE ABUTMENT ;
    PORT
      LAYER M4 ;
      RECT 154.204 179.988 154.276 180.012 ;
    END
  END w0_wd_in[245]
  PIN w0_wd_in[246]
    DIRECTION INPUT ;
    USE SIGNAL ;
    SHAPE ABUTMENT ;
    PORT
      LAYER M4 ;
      RECT 154.204 181.524 154.276 181.548 ;
    END
  END w0_wd_in[246]
  PIN w0_wd_in[247]
    DIRECTION INPUT ;
    USE SIGNAL ;
    SHAPE ABUTMENT ;
    PORT
      LAYER M4 ;
      RECT 154.204 183.060 154.276 183.084 ;
    END
  END w0_wd_in[247]
  PIN w0_wd_in[248]
    DIRECTION INPUT ;
    USE SIGNAL ;
    SHAPE ABUTMENT ;
    PORT
      LAYER M4 ;
      RECT 154.204 184.596 154.276 184.620 ;
    END
  END w0_wd_in[248]
  PIN w0_wd_in[249]
    DIRECTION INPUT ;
    USE SIGNAL ;
    SHAPE ABUTMENT ;
    PORT
      LAYER M4 ;
      RECT 154.204 186.132 154.276 186.156 ;
    END
  END w0_wd_in[249]
  PIN w0_wd_in[250]
    DIRECTION INPUT ;
    USE SIGNAL ;
    SHAPE ABUTMENT ;
    PORT
      LAYER M4 ;
      RECT 154.204 187.668 154.276 187.692 ;
    END
  END w0_wd_in[250]
  PIN w0_wd_in[251]
    DIRECTION INPUT ;
    USE SIGNAL ;
    SHAPE ABUTMENT ;
    PORT
      LAYER M4 ;
      RECT 154.204 189.204 154.276 189.228 ;
    END
  END w0_wd_in[251]
  PIN w0_wd_in[252]
    DIRECTION INPUT ;
    USE SIGNAL ;
    SHAPE ABUTMENT ;
    PORT
      LAYER M4 ;
      RECT 154.204 190.740 154.276 190.764 ;
    END
  END w0_wd_in[252]
  PIN w0_wd_in[253]
    DIRECTION INPUT ;
    USE SIGNAL ;
    SHAPE ABUTMENT ;
    PORT
      LAYER M4 ;
      RECT 154.204 192.276 154.276 192.300 ;
    END
  END w0_wd_in[253]
  PIN w0_wd_in[254]
    DIRECTION INPUT ;
    USE SIGNAL ;
    SHAPE ABUTMENT ;
    PORT
      LAYER M4 ;
      RECT 154.204 193.812 154.276 193.836 ;
    END
  END w0_wd_in[254]
  PIN w0_wd_in[255]
    DIRECTION INPUT ;
    USE SIGNAL ;
    SHAPE ABUTMENT ;
    PORT
      LAYER M4 ;
      RECT 154.204 195.348 154.276 195.372 ;
    END
  END w0_wd_in[255]
  PIN w0_wd_in[256]
    DIRECTION OUTPUT ;
    USE SIGNAL ;
    SHAPE ABUTMENT ;
    PORT
      LAYER M3 ;
      RECT 0.207 0.000 0.225 0.054 ;
    END
  END w0_wd_in[256]
  PIN w0_wd_in[257]
    DIRECTION OUTPUT ;
    USE SIGNAL ;
    SHAPE ABUTMENT ;
    PORT
      LAYER M3 ;
      RECT 0.495 0.000 0.513 0.054 ;
    END
  END w0_wd_in[257]
  PIN w0_wd_in[258]
    DIRECTION OUTPUT ;
    USE SIGNAL ;
    SHAPE ABUTMENT ;
    PORT
      LAYER M3 ;
      RECT 0.783 0.000 0.801 0.054 ;
    END
  END w0_wd_in[258]
  PIN w0_wd_in[259]
    DIRECTION OUTPUT ;
    USE SIGNAL ;
    SHAPE ABUTMENT ;
    PORT
      LAYER M3 ;
      RECT 1.071 0.000 1.089 0.054 ;
    END
  END w0_wd_in[259]
  PIN w0_wd_in[260]
    DIRECTION OUTPUT ;
    USE SIGNAL ;
    SHAPE ABUTMENT ;
    PORT
      LAYER M3 ;
      RECT 1.359 0.000 1.377 0.054 ;
    END
  END w0_wd_in[260]
  PIN w0_wd_in[261]
    DIRECTION OUTPUT ;
    USE SIGNAL ;
    SHAPE ABUTMENT ;
    PORT
      LAYER M3 ;
      RECT 1.647 0.000 1.665 0.054 ;
    END
  END w0_wd_in[261]
  PIN w0_wd_in[262]
    DIRECTION OUTPUT ;
    USE SIGNAL ;
    SHAPE ABUTMENT ;
    PORT
      LAYER M3 ;
      RECT 1.935 0.000 1.953 0.054 ;
    END
  END w0_wd_in[262]
  PIN w0_wd_in[263]
    DIRECTION OUTPUT ;
    USE SIGNAL ;
    SHAPE ABUTMENT ;
    PORT
      LAYER M3 ;
      RECT 2.223 0.000 2.241 0.054 ;
    END
  END w0_wd_in[263]
  PIN w0_wd_in[264]
    DIRECTION OUTPUT ;
    USE SIGNAL ;
    SHAPE ABUTMENT ;
    PORT
      LAYER M3 ;
      RECT 2.511 0.000 2.529 0.054 ;
    END
  END w0_wd_in[264]
  PIN w0_wd_in[265]
    DIRECTION OUTPUT ;
    USE SIGNAL ;
    SHAPE ABUTMENT ;
    PORT
      LAYER M3 ;
      RECT 2.799 0.000 2.817 0.054 ;
    END
  END w0_wd_in[265]
  PIN w0_wd_in[266]
    DIRECTION OUTPUT ;
    USE SIGNAL ;
    SHAPE ABUTMENT ;
    PORT
      LAYER M3 ;
      RECT 3.087 0.000 3.105 0.054 ;
    END
  END w0_wd_in[266]
  PIN w0_wd_in[267]
    DIRECTION OUTPUT ;
    USE SIGNAL ;
    SHAPE ABUTMENT ;
    PORT
      LAYER M3 ;
      RECT 3.375 0.000 3.393 0.054 ;
    END
  END w0_wd_in[267]
  PIN w0_wd_in[268]
    DIRECTION OUTPUT ;
    USE SIGNAL ;
    SHAPE ABUTMENT ;
    PORT
      LAYER M3 ;
      RECT 3.663 0.000 3.681 0.054 ;
    END
  END w0_wd_in[268]
  PIN w0_wd_in[269]
    DIRECTION OUTPUT ;
    USE SIGNAL ;
    SHAPE ABUTMENT ;
    PORT
      LAYER M3 ;
      RECT 3.951 0.000 3.969 0.054 ;
    END
  END w0_wd_in[269]
  PIN w0_wd_in[270]
    DIRECTION OUTPUT ;
    USE SIGNAL ;
    SHAPE ABUTMENT ;
    PORT
      LAYER M3 ;
      RECT 4.239 0.000 4.257 0.054 ;
    END
  END w0_wd_in[270]
  PIN w0_wd_in[271]
    DIRECTION OUTPUT ;
    USE SIGNAL ;
    SHAPE ABUTMENT ;
    PORT
      LAYER M3 ;
      RECT 4.527 0.000 4.545 0.054 ;
    END
  END w0_wd_in[271]
  PIN w0_wd_in[272]
    DIRECTION OUTPUT ;
    USE SIGNAL ;
    SHAPE ABUTMENT ;
    PORT
      LAYER M3 ;
      RECT 4.815 0.000 4.833 0.054 ;
    END
  END w0_wd_in[272]
  PIN w0_wd_in[273]
    DIRECTION OUTPUT ;
    USE SIGNAL ;
    SHAPE ABUTMENT ;
    PORT
      LAYER M3 ;
      RECT 5.103 0.000 5.121 0.054 ;
    END
  END w0_wd_in[273]
  PIN w0_wd_in[274]
    DIRECTION OUTPUT ;
    USE SIGNAL ;
    SHAPE ABUTMENT ;
    PORT
      LAYER M3 ;
      RECT 5.391 0.000 5.409 0.054 ;
    END
  END w0_wd_in[274]
  PIN w0_wd_in[275]
    DIRECTION OUTPUT ;
    USE SIGNAL ;
    SHAPE ABUTMENT ;
    PORT
      LAYER M3 ;
      RECT 5.679 0.000 5.697 0.054 ;
    END
  END w0_wd_in[275]
  PIN w0_wd_in[276]
    DIRECTION OUTPUT ;
    USE SIGNAL ;
    SHAPE ABUTMENT ;
    PORT
      LAYER M3 ;
      RECT 5.967 0.000 5.985 0.054 ;
    END
  END w0_wd_in[276]
  PIN w0_wd_in[277]
    DIRECTION OUTPUT ;
    USE SIGNAL ;
    SHAPE ABUTMENT ;
    PORT
      LAYER M3 ;
      RECT 6.255 0.000 6.273 0.054 ;
    END
  END w0_wd_in[277]
  PIN w0_wd_in[278]
    DIRECTION OUTPUT ;
    USE SIGNAL ;
    SHAPE ABUTMENT ;
    PORT
      LAYER M3 ;
      RECT 6.543 0.000 6.561 0.054 ;
    END
  END w0_wd_in[278]
  PIN w0_wd_in[279]
    DIRECTION OUTPUT ;
    USE SIGNAL ;
    SHAPE ABUTMENT ;
    PORT
      LAYER M3 ;
      RECT 6.831 0.000 6.849 0.054 ;
    END
  END w0_wd_in[279]
  PIN w0_wd_in[280]
    DIRECTION OUTPUT ;
    USE SIGNAL ;
    SHAPE ABUTMENT ;
    PORT
      LAYER M3 ;
      RECT 7.119 0.000 7.137 0.054 ;
    END
  END w0_wd_in[280]
  PIN w0_wd_in[281]
    DIRECTION OUTPUT ;
    USE SIGNAL ;
    SHAPE ABUTMENT ;
    PORT
      LAYER M3 ;
      RECT 7.407 0.000 7.425 0.054 ;
    END
  END w0_wd_in[281]
  PIN w0_wd_in[282]
    DIRECTION OUTPUT ;
    USE SIGNAL ;
    SHAPE ABUTMENT ;
    PORT
      LAYER M3 ;
      RECT 7.695 0.000 7.713 0.054 ;
    END
  END w0_wd_in[282]
  PIN w0_wd_in[283]
    DIRECTION OUTPUT ;
    USE SIGNAL ;
    SHAPE ABUTMENT ;
    PORT
      LAYER M3 ;
      RECT 7.983 0.000 8.001 0.054 ;
    END
  END w0_wd_in[283]
  PIN w0_wd_in[284]
    DIRECTION OUTPUT ;
    USE SIGNAL ;
    SHAPE ABUTMENT ;
    PORT
      LAYER M3 ;
      RECT 8.271 0.000 8.289 0.054 ;
    END
  END w0_wd_in[284]
  PIN w0_wd_in[285]
    DIRECTION OUTPUT ;
    USE SIGNAL ;
    SHAPE ABUTMENT ;
    PORT
      LAYER M3 ;
      RECT 8.559 0.000 8.577 0.054 ;
    END
  END w0_wd_in[285]
  PIN w0_wd_in[286]
    DIRECTION OUTPUT ;
    USE SIGNAL ;
    SHAPE ABUTMENT ;
    PORT
      LAYER M3 ;
      RECT 8.847 0.000 8.865 0.054 ;
    END
  END w0_wd_in[286]
  PIN w0_wd_in[287]
    DIRECTION OUTPUT ;
    USE SIGNAL ;
    SHAPE ABUTMENT ;
    PORT
      LAYER M3 ;
      RECT 9.135 0.000 9.153 0.054 ;
    END
  END w0_wd_in[287]
  PIN w0_wd_in[288]
    DIRECTION OUTPUT ;
    USE SIGNAL ;
    SHAPE ABUTMENT ;
    PORT
      LAYER M3 ;
      RECT 9.423 0.000 9.441 0.054 ;
    END
  END w0_wd_in[288]
  PIN w0_wd_in[289]
    DIRECTION OUTPUT ;
    USE SIGNAL ;
    SHAPE ABUTMENT ;
    PORT
      LAYER M3 ;
      RECT 9.711 0.000 9.729 0.054 ;
    END
  END w0_wd_in[289]
  PIN w0_wd_in[290]
    DIRECTION OUTPUT ;
    USE SIGNAL ;
    SHAPE ABUTMENT ;
    PORT
      LAYER M3 ;
      RECT 9.999 0.000 10.017 0.054 ;
    END
  END w0_wd_in[290]
  PIN w0_wd_in[291]
    DIRECTION OUTPUT ;
    USE SIGNAL ;
    SHAPE ABUTMENT ;
    PORT
      LAYER M3 ;
      RECT 10.287 0.000 10.305 0.054 ;
    END
  END w0_wd_in[291]
  PIN w0_wd_in[292]
    DIRECTION OUTPUT ;
    USE SIGNAL ;
    SHAPE ABUTMENT ;
    PORT
      LAYER M3 ;
      RECT 10.575 0.000 10.593 0.054 ;
    END
  END w0_wd_in[292]
  PIN w0_wd_in[293]
    DIRECTION OUTPUT ;
    USE SIGNAL ;
    SHAPE ABUTMENT ;
    PORT
      LAYER M3 ;
      RECT 10.863 0.000 10.881 0.054 ;
    END
  END w0_wd_in[293]
  PIN w0_wd_in[294]
    DIRECTION OUTPUT ;
    USE SIGNAL ;
    SHAPE ABUTMENT ;
    PORT
      LAYER M3 ;
      RECT 11.151 0.000 11.169 0.054 ;
    END
  END w0_wd_in[294]
  PIN w0_wd_in[295]
    DIRECTION OUTPUT ;
    USE SIGNAL ;
    SHAPE ABUTMENT ;
    PORT
      LAYER M3 ;
      RECT 11.439 0.000 11.457 0.054 ;
    END
  END w0_wd_in[295]
  PIN w0_wd_in[296]
    DIRECTION OUTPUT ;
    USE SIGNAL ;
    SHAPE ABUTMENT ;
    PORT
      LAYER M3 ;
      RECT 11.727 0.000 11.745 0.054 ;
    END
  END w0_wd_in[296]
  PIN w0_wd_in[297]
    DIRECTION OUTPUT ;
    USE SIGNAL ;
    SHAPE ABUTMENT ;
    PORT
      LAYER M3 ;
      RECT 12.015 0.000 12.033 0.054 ;
    END
  END w0_wd_in[297]
  PIN w0_wd_in[298]
    DIRECTION OUTPUT ;
    USE SIGNAL ;
    SHAPE ABUTMENT ;
    PORT
      LAYER M3 ;
      RECT 12.303 0.000 12.321 0.054 ;
    END
  END w0_wd_in[298]
  PIN w0_wd_in[299]
    DIRECTION OUTPUT ;
    USE SIGNAL ;
    SHAPE ABUTMENT ;
    PORT
      LAYER M3 ;
      RECT 12.591 0.000 12.609 0.054 ;
    END
  END w0_wd_in[299]
  PIN w0_wd_in[300]
    DIRECTION OUTPUT ;
    USE SIGNAL ;
    SHAPE ABUTMENT ;
    PORT
      LAYER M3 ;
      RECT 12.879 0.000 12.897 0.054 ;
    END
  END w0_wd_in[300]
  PIN w0_wd_in[301]
    DIRECTION OUTPUT ;
    USE SIGNAL ;
    SHAPE ABUTMENT ;
    PORT
      LAYER M3 ;
      RECT 13.167 0.000 13.185 0.054 ;
    END
  END w0_wd_in[301]
  PIN w0_wd_in[302]
    DIRECTION OUTPUT ;
    USE SIGNAL ;
    SHAPE ABUTMENT ;
    PORT
      LAYER M3 ;
      RECT 13.455 0.000 13.473 0.054 ;
    END
  END w0_wd_in[302]
  PIN w0_wd_in[303]
    DIRECTION OUTPUT ;
    USE SIGNAL ;
    SHAPE ABUTMENT ;
    PORT
      LAYER M3 ;
      RECT 13.743 0.000 13.761 0.054 ;
    END
  END w0_wd_in[303]
  PIN w0_wd_in[304]
    DIRECTION OUTPUT ;
    USE SIGNAL ;
    SHAPE ABUTMENT ;
    PORT
      LAYER M3 ;
      RECT 14.031 0.000 14.049 0.054 ;
    END
  END w0_wd_in[304]
  PIN w0_wd_in[305]
    DIRECTION OUTPUT ;
    USE SIGNAL ;
    SHAPE ABUTMENT ;
    PORT
      LAYER M3 ;
      RECT 14.319 0.000 14.337 0.054 ;
    END
  END w0_wd_in[305]
  PIN w0_wd_in[306]
    DIRECTION OUTPUT ;
    USE SIGNAL ;
    SHAPE ABUTMENT ;
    PORT
      LAYER M3 ;
      RECT 14.607 0.000 14.625 0.054 ;
    END
  END w0_wd_in[306]
  PIN w0_wd_in[307]
    DIRECTION OUTPUT ;
    USE SIGNAL ;
    SHAPE ABUTMENT ;
    PORT
      LAYER M3 ;
      RECT 14.895 0.000 14.913 0.054 ;
    END
  END w0_wd_in[307]
  PIN w0_wd_in[308]
    DIRECTION OUTPUT ;
    USE SIGNAL ;
    SHAPE ABUTMENT ;
    PORT
      LAYER M3 ;
      RECT 15.183 0.000 15.201 0.054 ;
    END
  END w0_wd_in[308]
  PIN w0_wd_in[309]
    DIRECTION OUTPUT ;
    USE SIGNAL ;
    SHAPE ABUTMENT ;
    PORT
      LAYER M3 ;
      RECT 15.471 0.000 15.489 0.054 ;
    END
  END w0_wd_in[309]
  PIN w0_wd_in[310]
    DIRECTION OUTPUT ;
    USE SIGNAL ;
    SHAPE ABUTMENT ;
    PORT
      LAYER M3 ;
      RECT 15.759 0.000 15.777 0.054 ;
    END
  END w0_wd_in[310]
  PIN w0_wd_in[311]
    DIRECTION OUTPUT ;
    USE SIGNAL ;
    SHAPE ABUTMENT ;
    PORT
      LAYER M3 ;
      RECT 16.047 0.000 16.065 0.054 ;
    END
  END w0_wd_in[311]
  PIN w0_wd_in[312]
    DIRECTION OUTPUT ;
    USE SIGNAL ;
    SHAPE ABUTMENT ;
    PORT
      LAYER M3 ;
      RECT 16.335 0.000 16.353 0.054 ;
    END
  END w0_wd_in[312]
  PIN w0_wd_in[313]
    DIRECTION OUTPUT ;
    USE SIGNAL ;
    SHAPE ABUTMENT ;
    PORT
      LAYER M3 ;
      RECT 16.623 0.000 16.641 0.054 ;
    END
  END w0_wd_in[313]
  PIN w0_wd_in[314]
    DIRECTION OUTPUT ;
    USE SIGNAL ;
    SHAPE ABUTMENT ;
    PORT
      LAYER M3 ;
      RECT 16.911 0.000 16.929 0.054 ;
    END
  END w0_wd_in[314]
  PIN w0_wd_in[315]
    DIRECTION OUTPUT ;
    USE SIGNAL ;
    SHAPE ABUTMENT ;
    PORT
      LAYER M3 ;
      RECT 17.199 0.000 17.217 0.054 ;
    END
  END w0_wd_in[315]
  PIN w0_wd_in[316]
    DIRECTION OUTPUT ;
    USE SIGNAL ;
    SHAPE ABUTMENT ;
    PORT
      LAYER M3 ;
      RECT 17.487 0.000 17.505 0.054 ;
    END
  END w0_wd_in[316]
  PIN w0_wd_in[317]
    DIRECTION OUTPUT ;
    USE SIGNAL ;
    SHAPE ABUTMENT ;
    PORT
      LAYER M3 ;
      RECT 17.775 0.000 17.793 0.054 ;
    END
  END w0_wd_in[317]
  PIN w0_wd_in[318]
    DIRECTION OUTPUT ;
    USE SIGNAL ;
    SHAPE ABUTMENT ;
    PORT
      LAYER M3 ;
      RECT 18.063 0.000 18.081 0.054 ;
    END
  END w0_wd_in[318]
  PIN w0_wd_in[319]
    DIRECTION OUTPUT ;
    USE SIGNAL ;
    SHAPE ABUTMENT ;
    PORT
      LAYER M3 ;
      RECT 18.351 0.000 18.369 0.054 ;
    END
  END w0_wd_in[319]
  PIN w0_wd_in[320]
    DIRECTION OUTPUT ;
    USE SIGNAL ;
    SHAPE ABUTMENT ;
    PORT
      LAYER M3 ;
      RECT 18.639 0.000 18.657 0.054 ;
    END
  END w0_wd_in[320]
  PIN w0_wd_in[321]
    DIRECTION OUTPUT ;
    USE SIGNAL ;
    SHAPE ABUTMENT ;
    PORT
      LAYER M3 ;
      RECT 18.927 0.000 18.945 0.054 ;
    END
  END w0_wd_in[321]
  PIN w0_wd_in[322]
    DIRECTION OUTPUT ;
    USE SIGNAL ;
    SHAPE ABUTMENT ;
    PORT
      LAYER M3 ;
      RECT 19.215 0.000 19.233 0.054 ;
    END
  END w0_wd_in[322]
  PIN w0_wd_in[323]
    DIRECTION OUTPUT ;
    USE SIGNAL ;
    SHAPE ABUTMENT ;
    PORT
      LAYER M3 ;
      RECT 19.503 0.000 19.521 0.054 ;
    END
  END w0_wd_in[323]
  PIN w0_wd_in[324]
    DIRECTION OUTPUT ;
    USE SIGNAL ;
    SHAPE ABUTMENT ;
    PORT
      LAYER M3 ;
      RECT 19.791 0.000 19.809 0.054 ;
    END
  END w0_wd_in[324]
  PIN w0_wd_in[325]
    DIRECTION OUTPUT ;
    USE SIGNAL ;
    SHAPE ABUTMENT ;
    PORT
      LAYER M3 ;
      RECT 20.079 0.000 20.097 0.054 ;
    END
  END w0_wd_in[325]
  PIN w0_wd_in[326]
    DIRECTION OUTPUT ;
    USE SIGNAL ;
    SHAPE ABUTMENT ;
    PORT
      LAYER M3 ;
      RECT 20.367 0.000 20.385 0.054 ;
    END
  END w0_wd_in[326]
  PIN w0_wd_in[327]
    DIRECTION OUTPUT ;
    USE SIGNAL ;
    SHAPE ABUTMENT ;
    PORT
      LAYER M3 ;
      RECT 20.655 0.000 20.673 0.054 ;
    END
  END w0_wd_in[327]
  PIN w0_wd_in[328]
    DIRECTION OUTPUT ;
    USE SIGNAL ;
    SHAPE ABUTMENT ;
    PORT
      LAYER M3 ;
      RECT 20.943 0.000 20.961 0.054 ;
    END
  END w0_wd_in[328]
  PIN w0_wd_in[329]
    DIRECTION OUTPUT ;
    USE SIGNAL ;
    SHAPE ABUTMENT ;
    PORT
      LAYER M3 ;
      RECT 21.231 0.000 21.249 0.054 ;
    END
  END w0_wd_in[329]
  PIN w0_wd_in[330]
    DIRECTION OUTPUT ;
    USE SIGNAL ;
    SHAPE ABUTMENT ;
    PORT
      LAYER M3 ;
      RECT 21.519 0.000 21.537 0.054 ;
    END
  END w0_wd_in[330]
  PIN w0_wd_in[331]
    DIRECTION OUTPUT ;
    USE SIGNAL ;
    SHAPE ABUTMENT ;
    PORT
      LAYER M3 ;
      RECT 21.807 0.000 21.825 0.054 ;
    END
  END w0_wd_in[331]
  PIN w0_wd_in[332]
    DIRECTION OUTPUT ;
    USE SIGNAL ;
    SHAPE ABUTMENT ;
    PORT
      LAYER M3 ;
      RECT 22.095 0.000 22.113 0.054 ;
    END
  END w0_wd_in[332]
  PIN w0_wd_in[333]
    DIRECTION OUTPUT ;
    USE SIGNAL ;
    SHAPE ABUTMENT ;
    PORT
      LAYER M3 ;
      RECT 22.383 0.000 22.401 0.054 ;
    END
  END w0_wd_in[333]
  PIN w0_wd_in[334]
    DIRECTION OUTPUT ;
    USE SIGNAL ;
    SHAPE ABUTMENT ;
    PORT
      LAYER M3 ;
      RECT 22.671 0.000 22.689 0.054 ;
    END
  END w0_wd_in[334]
  PIN w0_wd_in[335]
    DIRECTION OUTPUT ;
    USE SIGNAL ;
    SHAPE ABUTMENT ;
    PORT
      LAYER M3 ;
      RECT 22.959 0.000 22.977 0.054 ;
    END
  END w0_wd_in[335]
  PIN w0_wd_in[336]
    DIRECTION OUTPUT ;
    USE SIGNAL ;
    SHAPE ABUTMENT ;
    PORT
      LAYER M3 ;
      RECT 23.247 0.000 23.265 0.054 ;
    END
  END w0_wd_in[336]
  PIN w0_wd_in[337]
    DIRECTION OUTPUT ;
    USE SIGNAL ;
    SHAPE ABUTMENT ;
    PORT
      LAYER M3 ;
      RECT 23.535 0.000 23.553 0.054 ;
    END
  END w0_wd_in[337]
  PIN w0_wd_in[338]
    DIRECTION OUTPUT ;
    USE SIGNAL ;
    SHAPE ABUTMENT ;
    PORT
      LAYER M3 ;
      RECT 23.823 0.000 23.841 0.054 ;
    END
  END w0_wd_in[338]
  PIN w0_wd_in[339]
    DIRECTION OUTPUT ;
    USE SIGNAL ;
    SHAPE ABUTMENT ;
    PORT
      LAYER M3 ;
      RECT 24.111 0.000 24.129 0.054 ;
    END
  END w0_wd_in[339]
  PIN w0_wd_in[340]
    DIRECTION OUTPUT ;
    USE SIGNAL ;
    SHAPE ABUTMENT ;
    PORT
      LAYER M3 ;
      RECT 24.399 0.000 24.417 0.054 ;
    END
  END w0_wd_in[340]
  PIN w0_wd_in[341]
    DIRECTION OUTPUT ;
    USE SIGNAL ;
    SHAPE ABUTMENT ;
    PORT
      LAYER M3 ;
      RECT 24.687 0.000 24.705 0.054 ;
    END
  END w0_wd_in[341]
  PIN w0_wd_in[342]
    DIRECTION OUTPUT ;
    USE SIGNAL ;
    SHAPE ABUTMENT ;
    PORT
      LAYER M3 ;
      RECT 24.975 0.000 24.993 0.054 ;
    END
  END w0_wd_in[342]
  PIN w0_wd_in[343]
    DIRECTION OUTPUT ;
    USE SIGNAL ;
    SHAPE ABUTMENT ;
    PORT
      LAYER M3 ;
      RECT 25.263 0.000 25.281 0.054 ;
    END
  END w0_wd_in[343]
  PIN w0_wd_in[344]
    DIRECTION OUTPUT ;
    USE SIGNAL ;
    SHAPE ABUTMENT ;
    PORT
      LAYER M3 ;
      RECT 25.551 0.000 25.569 0.054 ;
    END
  END w0_wd_in[344]
  PIN w0_wd_in[345]
    DIRECTION OUTPUT ;
    USE SIGNAL ;
    SHAPE ABUTMENT ;
    PORT
      LAYER M3 ;
      RECT 25.839 0.000 25.857 0.054 ;
    END
  END w0_wd_in[345]
  PIN w0_wd_in[346]
    DIRECTION OUTPUT ;
    USE SIGNAL ;
    SHAPE ABUTMENT ;
    PORT
      LAYER M3 ;
      RECT 26.127 0.000 26.145 0.054 ;
    END
  END w0_wd_in[346]
  PIN w0_wd_in[347]
    DIRECTION OUTPUT ;
    USE SIGNAL ;
    SHAPE ABUTMENT ;
    PORT
      LAYER M3 ;
      RECT 26.415 0.000 26.433 0.054 ;
    END
  END w0_wd_in[347]
  PIN w0_wd_in[348]
    DIRECTION OUTPUT ;
    USE SIGNAL ;
    SHAPE ABUTMENT ;
    PORT
      LAYER M3 ;
      RECT 26.703 0.000 26.721 0.054 ;
    END
  END w0_wd_in[348]
  PIN w0_wd_in[349]
    DIRECTION OUTPUT ;
    USE SIGNAL ;
    SHAPE ABUTMENT ;
    PORT
      LAYER M3 ;
      RECT 26.991 0.000 27.009 0.054 ;
    END
  END w0_wd_in[349]
  PIN w0_wd_in[350]
    DIRECTION OUTPUT ;
    USE SIGNAL ;
    SHAPE ABUTMENT ;
    PORT
      LAYER M3 ;
      RECT 27.279 0.000 27.297 0.054 ;
    END
  END w0_wd_in[350]
  PIN w0_wd_in[351]
    DIRECTION OUTPUT ;
    USE SIGNAL ;
    SHAPE ABUTMENT ;
    PORT
      LAYER M3 ;
      RECT 27.567 0.000 27.585 0.054 ;
    END
  END w0_wd_in[351]
  PIN w0_wd_in[352]
    DIRECTION OUTPUT ;
    USE SIGNAL ;
    SHAPE ABUTMENT ;
    PORT
      LAYER M3 ;
      RECT 27.855 0.000 27.873 0.054 ;
    END
  END w0_wd_in[352]
  PIN w0_wd_in[353]
    DIRECTION OUTPUT ;
    USE SIGNAL ;
    SHAPE ABUTMENT ;
    PORT
      LAYER M3 ;
      RECT 28.143 0.000 28.161 0.054 ;
    END
  END w0_wd_in[353]
  PIN w0_wd_in[354]
    DIRECTION OUTPUT ;
    USE SIGNAL ;
    SHAPE ABUTMENT ;
    PORT
      LAYER M3 ;
      RECT 28.431 0.000 28.449 0.054 ;
    END
  END w0_wd_in[354]
  PIN w0_wd_in[355]
    DIRECTION OUTPUT ;
    USE SIGNAL ;
    SHAPE ABUTMENT ;
    PORT
      LAYER M3 ;
      RECT 28.719 0.000 28.737 0.054 ;
    END
  END w0_wd_in[355]
  PIN w0_wd_in[356]
    DIRECTION OUTPUT ;
    USE SIGNAL ;
    SHAPE ABUTMENT ;
    PORT
      LAYER M3 ;
      RECT 29.007 0.000 29.025 0.054 ;
    END
  END w0_wd_in[356]
  PIN w0_wd_in[357]
    DIRECTION OUTPUT ;
    USE SIGNAL ;
    SHAPE ABUTMENT ;
    PORT
      LAYER M3 ;
      RECT 29.295 0.000 29.313 0.054 ;
    END
  END w0_wd_in[357]
  PIN w0_wd_in[358]
    DIRECTION OUTPUT ;
    USE SIGNAL ;
    SHAPE ABUTMENT ;
    PORT
      LAYER M3 ;
      RECT 29.583 0.000 29.601 0.054 ;
    END
  END w0_wd_in[358]
  PIN w0_wd_in[359]
    DIRECTION OUTPUT ;
    USE SIGNAL ;
    SHAPE ABUTMENT ;
    PORT
      LAYER M3 ;
      RECT 29.871 0.000 29.889 0.054 ;
    END
  END w0_wd_in[359]
  PIN w0_wd_in[360]
    DIRECTION OUTPUT ;
    USE SIGNAL ;
    SHAPE ABUTMENT ;
    PORT
      LAYER M3 ;
      RECT 30.159 0.000 30.177 0.054 ;
    END
  END w0_wd_in[360]
  PIN w0_wd_in[361]
    DIRECTION OUTPUT ;
    USE SIGNAL ;
    SHAPE ABUTMENT ;
    PORT
      LAYER M3 ;
      RECT 30.447 0.000 30.465 0.054 ;
    END
  END w0_wd_in[361]
  PIN w0_wd_in[362]
    DIRECTION OUTPUT ;
    USE SIGNAL ;
    SHAPE ABUTMENT ;
    PORT
      LAYER M3 ;
      RECT 30.735 0.000 30.753 0.054 ;
    END
  END w0_wd_in[362]
  PIN w0_wd_in[363]
    DIRECTION OUTPUT ;
    USE SIGNAL ;
    SHAPE ABUTMENT ;
    PORT
      LAYER M3 ;
      RECT 31.023 0.000 31.041 0.054 ;
    END
  END w0_wd_in[363]
  PIN w0_wd_in[364]
    DIRECTION OUTPUT ;
    USE SIGNAL ;
    SHAPE ABUTMENT ;
    PORT
      LAYER M3 ;
      RECT 31.311 0.000 31.329 0.054 ;
    END
  END w0_wd_in[364]
  PIN w0_wd_in[365]
    DIRECTION OUTPUT ;
    USE SIGNAL ;
    SHAPE ABUTMENT ;
    PORT
      LAYER M3 ;
      RECT 31.599 0.000 31.617 0.054 ;
    END
  END w0_wd_in[365]
  PIN w0_wd_in[366]
    DIRECTION OUTPUT ;
    USE SIGNAL ;
    SHAPE ABUTMENT ;
    PORT
      LAYER M3 ;
      RECT 31.887 0.000 31.905 0.054 ;
    END
  END w0_wd_in[366]
  PIN w0_wd_in[367]
    DIRECTION OUTPUT ;
    USE SIGNAL ;
    SHAPE ABUTMENT ;
    PORT
      LAYER M3 ;
      RECT 32.175 0.000 32.193 0.054 ;
    END
  END w0_wd_in[367]
  PIN w0_wd_in[368]
    DIRECTION OUTPUT ;
    USE SIGNAL ;
    SHAPE ABUTMENT ;
    PORT
      LAYER M3 ;
      RECT 32.463 0.000 32.481 0.054 ;
    END
  END w0_wd_in[368]
  PIN w0_wd_in[369]
    DIRECTION OUTPUT ;
    USE SIGNAL ;
    SHAPE ABUTMENT ;
    PORT
      LAYER M3 ;
      RECT 32.751 0.000 32.769 0.054 ;
    END
  END w0_wd_in[369]
  PIN w0_wd_in[370]
    DIRECTION OUTPUT ;
    USE SIGNAL ;
    SHAPE ABUTMENT ;
    PORT
      LAYER M3 ;
      RECT 33.039 0.000 33.057 0.054 ;
    END
  END w0_wd_in[370]
  PIN w0_wd_in[371]
    DIRECTION OUTPUT ;
    USE SIGNAL ;
    SHAPE ABUTMENT ;
    PORT
      LAYER M3 ;
      RECT 33.327 0.000 33.345 0.054 ;
    END
  END w0_wd_in[371]
  PIN w0_wd_in[372]
    DIRECTION OUTPUT ;
    USE SIGNAL ;
    SHAPE ABUTMENT ;
    PORT
      LAYER M3 ;
      RECT 33.615 0.000 33.633 0.054 ;
    END
  END w0_wd_in[372]
  PIN w0_wd_in[373]
    DIRECTION OUTPUT ;
    USE SIGNAL ;
    SHAPE ABUTMENT ;
    PORT
      LAYER M3 ;
      RECT 33.903 0.000 33.921 0.054 ;
    END
  END w0_wd_in[373]
  PIN w0_wd_in[374]
    DIRECTION OUTPUT ;
    USE SIGNAL ;
    SHAPE ABUTMENT ;
    PORT
      LAYER M3 ;
      RECT 34.191 0.000 34.209 0.054 ;
    END
  END w0_wd_in[374]
  PIN w0_wd_in[375]
    DIRECTION OUTPUT ;
    USE SIGNAL ;
    SHAPE ABUTMENT ;
    PORT
      LAYER M3 ;
      RECT 34.479 0.000 34.497 0.054 ;
    END
  END w0_wd_in[375]
  PIN w0_wd_in[376]
    DIRECTION OUTPUT ;
    USE SIGNAL ;
    SHAPE ABUTMENT ;
    PORT
      LAYER M3 ;
      RECT 34.767 0.000 34.785 0.054 ;
    END
  END w0_wd_in[376]
  PIN w0_wd_in[377]
    DIRECTION OUTPUT ;
    USE SIGNAL ;
    SHAPE ABUTMENT ;
    PORT
      LAYER M3 ;
      RECT 35.055 0.000 35.073 0.054 ;
    END
  END w0_wd_in[377]
  PIN w0_wd_in[378]
    DIRECTION OUTPUT ;
    USE SIGNAL ;
    SHAPE ABUTMENT ;
    PORT
      LAYER M3 ;
      RECT 35.343 0.000 35.361 0.054 ;
    END
  END w0_wd_in[378]
  PIN w0_wd_in[379]
    DIRECTION OUTPUT ;
    USE SIGNAL ;
    SHAPE ABUTMENT ;
    PORT
      LAYER M3 ;
      RECT 35.631 0.000 35.649 0.054 ;
    END
  END w0_wd_in[379]
  PIN w0_wd_in[380]
    DIRECTION OUTPUT ;
    USE SIGNAL ;
    SHAPE ABUTMENT ;
    PORT
      LAYER M3 ;
      RECT 35.919 0.000 35.937 0.054 ;
    END
  END w0_wd_in[380]
  PIN w0_wd_in[381]
    DIRECTION OUTPUT ;
    USE SIGNAL ;
    SHAPE ABUTMENT ;
    PORT
      LAYER M3 ;
      RECT 36.207 0.000 36.225 0.054 ;
    END
  END w0_wd_in[381]
  PIN w0_wd_in[382]
    DIRECTION OUTPUT ;
    USE SIGNAL ;
    SHAPE ABUTMENT ;
    PORT
      LAYER M3 ;
      RECT 36.495 0.000 36.513 0.054 ;
    END
  END w0_wd_in[382]
  PIN w0_wd_in[383]
    DIRECTION OUTPUT ;
    USE SIGNAL ;
    SHAPE ABUTMENT ;
    PORT
      LAYER M3 ;
      RECT 36.783 0.000 36.801 0.054 ;
    END
  END w0_wd_in[383]
  PIN w0_wd_in[384]
    DIRECTION OUTPUT ;
    USE SIGNAL ;
    SHAPE ABUTMENT ;
    PORT
      LAYER M3 ;
      RECT 37.071 0.000 37.089 0.054 ;
    END
  END w0_wd_in[384]
  PIN w0_wd_in[385]
    DIRECTION OUTPUT ;
    USE SIGNAL ;
    SHAPE ABUTMENT ;
    PORT
      LAYER M3 ;
      RECT 37.359 0.000 37.377 0.054 ;
    END
  END w0_wd_in[385]
  PIN w0_wd_in[386]
    DIRECTION OUTPUT ;
    USE SIGNAL ;
    SHAPE ABUTMENT ;
    PORT
      LAYER M3 ;
      RECT 37.647 0.000 37.665 0.054 ;
    END
  END w0_wd_in[386]
  PIN w0_wd_in[387]
    DIRECTION OUTPUT ;
    USE SIGNAL ;
    SHAPE ABUTMENT ;
    PORT
      LAYER M3 ;
      RECT 37.935 0.000 37.953 0.054 ;
    END
  END w0_wd_in[387]
  PIN w0_wd_in[388]
    DIRECTION OUTPUT ;
    USE SIGNAL ;
    SHAPE ABUTMENT ;
    PORT
      LAYER M3 ;
      RECT 38.223 0.000 38.241 0.054 ;
    END
  END w0_wd_in[388]
  PIN w0_wd_in[389]
    DIRECTION OUTPUT ;
    USE SIGNAL ;
    SHAPE ABUTMENT ;
    PORT
      LAYER M3 ;
      RECT 38.511 0.000 38.529 0.054 ;
    END
  END w0_wd_in[389]
  PIN w0_wd_in[390]
    DIRECTION OUTPUT ;
    USE SIGNAL ;
    SHAPE ABUTMENT ;
    PORT
      LAYER M3 ;
      RECT 38.799 0.000 38.817 0.054 ;
    END
  END w0_wd_in[390]
  PIN w0_wd_in[391]
    DIRECTION OUTPUT ;
    USE SIGNAL ;
    SHAPE ABUTMENT ;
    PORT
      LAYER M3 ;
      RECT 39.087 0.000 39.105 0.054 ;
    END
  END w0_wd_in[391]
  PIN w0_wd_in[392]
    DIRECTION OUTPUT ;
    USE SIGNAL ;
    SHAPE ABUTMENT ;
    PORT
      LAYER M3 ;
      RECT 39.375 0.000 39.393 0.054 ;
    END
  END w0_wd_in[392]
  PIN w0_wd_in[393]
    DIRECTION OUTPUT ;
    USE SIGNAL ;
    SHAPE ABUTMENT ;
    PORT
      LAYER M3 ;
      RECT 39.663 0.000 39.681 0.054 ;
    END
  END w0_wd_in[393]
  PIN w0_wd_in[394]
    DIRECTION OUTPUT ;
    USE SIGNAL ;
    SHAPE ABUTMENT ;
    PORT
      LAYER M3 ;
      RECT 39.951 0.000 39.969 0.054 ;
    END
  END w0_wd_in[394]
  PIN w0_wd_in[395]
    DIRECTION OUTPUT ;
    USE SIGNAL ;
    SHAPE ABUTMENT ;
    PORT
      LAYER M3 ;
      RECT 40.239 0.000 40.257 0.054 ;
    END
  END w0_wd_in[395]
  PIN w0_wd_in[396]
    DIRECTION OUTPUT ;
    USE SIGNAL ;
    SHAPE ABUTMENT ;
    PORT
      LAYER M3 ;
      RECT 40.527 0.000 40.545 0.054 ;
    END
  END w0_wd_in[396]
  PIN w0_wd_in[397]
    DIRECTION OUTPUT ;
    USE SIGNAL ;
    SHAPE ABUTMENT ;
    PORT
      LAYER M3 ;
      RECT 40.815 0.000 40.833 0.054 ;
    END
  END w0_wd_in[397]
  PIN w0_wd_in[398]
    DIRECTION OUTPUT ;
    USE SIGNAL ;
    SHAPE ABUTMENT ;
    PORT
      LAYER M3 ;
      RECT 41.103 0.000 41.121 0.054 ;
    END
  END w0_wd_in[398]
  PIN w0_wd_in[399]
    DIRECTION OUTPUT ;
    USE SIGNAL ;
    SHAPE ABUTMENT ;
    PORT
      LAYER M3 ;
      RECT 41.391 0.000 41.409 0.054 ;
    END
  END w0_wd_in[399]
  PIN w0_wd_in[400]
    DIRECTION OUTPUT ;
    USE SIGNAL ;
    SHAPE ABUTMENT ;
    PORT
      LAYER M3 ;
      RECT 41.679 0.000 41.697 0.054 ;
    END
  END w0_wd_in[400]
  PIN w0_wd_in[401]
    DIRECTION OUTPUT ;
    USE SIGNAL ;
    SHAPE ABUTMENT ;
    PORT
      LAYER M3 ;
      RECT 41.967 0.000 41.985 0.054 ;
    END
  END w0_wd_in[401]
  PIN w0_wd_in[402]
    DIRECTION OUTPUT ;
    USE SIGNAL ;
    SHAPE ABUTMENT ;
    PORT
      LAYER M3 ;
      RECT 42.255 0.000 42.273 0.054 ;
    END
  END w0_wd_in[402]
  PIN w0_wd_in[403]
    DIRECTION OUTPUT ;
    USE SIGNAL ;
    SHAPE ABUTMENT ;
    PORT
      LAYER M3 ;
      RECT 42.543 0.000 42.561 0.054 ;
    END
  END w0_wd_in[403]
  PIN w0_wd_in[404]
    DIRECTION OUTPUT ;
    USE SIGNAL ;
    SHAPE ABUTMENT ;
    PORT
      LAYER M3 ;
      RECT 42.831 0.000 42.849 0.054 ;
    END
  END w0_wd_in[404]
  PIN w0_wd_in[405]
    DIRECTION OUTPUT ;
    USE SIGNAL ;
    SHAPE ABUTMENT ;
    PORT
      LAYER M3 ;
      RECT 43.119 0.000 43.137 0.054 ;
    END
  END w0_wd_in[405]
  PIN w0_wd_in[406]
    DIRECTION OUTPUT ;
    USE SIGNAL ;
    SHAPE ABUTMENT ;
    PORT
      LAYER M3 ;
      RECT 43.407 0.000 43.425 0.054 ;
    END
  END w0_wd_in[406]
  PIN w0_wd_in[407]
    DIRECTION OUTPUT ;
    USE SIGNAL ;
    SHAPE ABUTMENT ;
    PORT
      LAYER M3 ;
      RECT 43.695 0.000 43.713 0.054 ;
    END
  END w0_wd_in[407]
  PIN w0_wd_in[408]
    DIRECTION OUTPUT ;
    USE SIGNAL ;
    SHAPE ABUTMENT ;
    PORT
      LAYER M3 ;
      RECT 43.983 0.000 44.001 0.054 ;
    END
  END w0_wd_in[408]
  PIN w0_wd_in[409]
    DIRECTION OUTPUT ;
    USE SIGNAL ;
    SHAPE ABUTMENT ;
    PORT
      LAYER M3 ;
      RECT 44.271 0.000 44.289 0.054 ;
    END
  END w0_wd_in[409]
  PIN w0_wd_in[410]
    DIRECTION OUTPUT ;
    USE SIGNAL ;
    SHAPE ABUTMENT ;
    PORT
      LAYER M3 ;
      RECT 44.559 0.000 44.577 0.054 ;
    END
  END w0_wd_in[410]
  PIN w0_wd_in[411]
    DIRECTION OUTPUT ;
    USE SIGNAL ;
    SHAPE ABUTMENT ;
    PORT
      LAYER M3 ;
      RECT 44.847 0.000 44.865 0.054 ;
    END
  END w0_wd_in[411]
  PIN w0_wd_in[412]
    DIRECTION OUTPUT ;
    USE SIGNAL ;
    SHAPE ABUTMENT ;
    PORT
      LAYER M3 ;
      RECT 45.135 0.000 45.153 0.054 ;
    END
  END w0_wd_in[412]
  PIN w0_wd_in[413]
    DIRECTION OUTPUT ;
    USE SIGNAL ;
    SHAPE ABUTMENT ;
    PORT
      LAYER M3 ;
      RECT 45.423 0.000 45.441 0.054 ;
    END
  END w0_wd_in[413]
  PIN w0_wd_in[414]
    DIRECTION OUTPUT ;
    USE SIGNAL ;
    SHAPE ABUTMENT ;
    PORT
      LAYER M3 ;
      RECT 45.711 0.000 45.729 0.054 ;
    END
  END w0_wd_in[414]
  PIN w0_wd_in[415]
    DIRECTION OUTPUT ;
    USE SIGNAL ;
    SHAPE ABUTMENT ;
    PORT
      LAYER M3 ;
      RECT 45.999 0.000 46.017 0.054 ;
    END
  END w0_wd_in[415]
  PIN w0_wd_in[416]
    DIRECTION OUTPUT ;
    USE SIGNAL ;
    SHAPE ABUTMENT ;
    PORT
      LAYER M3 ;
      RECT 46.287 0.000 46.305 0.054 ;
    END
  END w0_wd_in[416]
  PIN w0_wd_in[417]
    DIRECTION OUTPUT ;
    USE SIGNAL ;
    SHAPE ABUTMENT ;
    PORT
      LAYER M3 ;
      RECT 46.575 0.000 46.593 0.054 ;
    END
  END w0_wd_in[417]
  PIN w0_wd_in[418]
    DIRECTION OUTPUT ;
    USE SIGNAL ;
    SHAPE ABUTMENT ;
    PORT
      LAYER M3 ;
      RECT 46.863 0.000 46.881 0.054 ;
    END
  END w0_wd_in[418]
  PIN w0_wd_in[419]
    DIRECTION OUTPUT ;
    USE SIGNAL ;
    SHAPE ABUTMENT ;
    PORT
      LAYER M3 ;
      RECT 47.151 0.000 47.169 0.054 ;
    END
  END w0_wd_in[419]
  PIN w0_wd_in[420]
    DIRECTION OUTPUT ;
    USE SIGNAL ;
    SHAPE ABUTMENT ;
    PORT
      LAYER M3 ;
      RECT 47.439 0.000 47.457 0.054 ;
    END
  END w0_wd_in[420]
  PIN w0_wd_in[421]
    DIRECTION OUTPUT ;
    USE SIGNAL ;
    SHAPE ABUTMENT ;
    PORT
      LAYER M3 ;
      RECT 47.727 0.000 47.745 0.054 ;
    END
  END w0_wd_in[421]
  PIN w0_wd_in[422]
    DIRECTION OUTPUT ;
    USE SIGNAL ;
    SHAPE ABUTMENT ;
    PORT
      LAYER M3 ;
      RECT 48.015 0.000 48.033 0.054 ;
    END
  END w0_wd_in[422]
  PIN w0_wd_in[423]
    DIRECTION OUTPUT ;
    USE SIGNAL ;
    SHAPE ABUTMENT ;
    PORT
      LAYER M3 ;
      RECT 48.303 0.000 48.321 0.054 ;
    END
  END w0_wd_in[423]
  PIN w0_wd_in[424]
    DIRECTION OUTPUT ;
    USE SIGNAL ;
    SHAPE ABUTMENT ;
    PORT
      LAYER M3 ;
      RECT 48.591 0.000 48.609 0.054 ;
    END
  END w0_wd_in[424]
  PIN w0_wd_in[425]
    DIRECTION OUTPUT ;
    USE SIGNAL ;
    SHAPE ABUTMENT ;
    PORT
      LAYER M3 ;
      RECT 48.879 0.000 48.897 0.054 ;
    END
  END w0_wd_in[425]
  PIN w0_wd_in[426]
    DIRECTION OUTPUT ;
    USE SIGNAL ;
    SHAPE ABUTMENT ;
    PORT
      LAYER M3 ;
      RECT 49.167 0.000 49.185 0.054 ;
    END
  END w0_wd_in[426]
  PIN w0_wd_in[427]
    DIRECTION OUTPUT ;
    USE SIGNAL ;
    SHAPE ABUTMENT ;
    PORT
      LAYER M3 ;
      RECT 49.455 0.000 49.473 0.054 ;
    END
  END w0_wd_in[427]
  PIN w0_wd_in[428]
    DIRECTION OUTPUT ;
    USE SIGNAL ;
    SHAPE ABUTMENT ;
    PORT
      LAYER M3 ;
      RECT 49.743 0.000 49.761 0.054 ;
    END
  END w0_wd_in[428]
  PIN w0_wd_in[429]
    DIRECTION OUTPUT ;
    USE SIGNAL ;
    SHAPE ABUTMENT ;
    PORT
      LAYER M3 ;
      RECT 50.031 0.000 50.049 0.054 ;
    END
  END w0_wd_in[429]
  PIN w0_wd_in[430]
    DIRECTION OUTPUT ;
    USE SIGNAL ;
    SHAPE ABUTMENT ;
    PORT
      LAYER M3 ;
      RECT 50.319 0.000 50.337 0.054 ;
    END
  END w0_wd_in[430]
  PIN w0_wd_in[431]
    DIRECTION OUTPUT ;
    USE SIGNAL ;
    SHAPE ABUTMENT ;
    PORT
      LAYER M3 ;
      RECT 50.607 0.000 50.625 0.054 ;
    END
  END w0_wd_in[431]
  PIN w0_wd_in[432]
    DIRECTION OUTPUT ;
    USE SIGNAL ;
    SHAPE ABUTMENT ;
    PORT
      LAYER M3 ;
      RECT 50.895 0.000 50.913 0.054 ;
    END
  END w0_wd_in[432]
  PIN w0_wd_in[433]
    DIRECTION OUTPUT ;
    USE SIGNAL ;
    SHAPE ABUTMENT ;
    PORT
      LAYER M3 ;
      RECT 51.183 0.000 51.201 0.054 ;
    END
  END w0_wd_in[433]
  PIN w0_wd_in[434]
    DIRECTION OUTPUT ;
    USE SIGNAL ;
    SHAPE ABUTMENT ;
    PORT
      LAYER M3 ;
      RECT 51.471 0.000 51.489 0.054 ;
    END
  END w0_wd_in[434]
  PIN w0_wd_in[435]
    DIRECTION OUTPUT ;
    USE SIGNAL ;
    SHAPE ABUTMENT ;
    PORT
      LAYER M3 ;
      RECT 51.759 0.000 51.777 0.054 ;
    END
  END w0_wd_in[435]
  PIN w0_wd_in[436]
    DIRECTION OUTPUT ;
    USE SIGNAL ;
    SHAPE ABUTMENT ;
    PORT
      LAYER M3 ;
      RECT 52.047 0.000 52.065 0.054 ;
    END
  END w0_wd_in[436]
  PIN w0_wd_in[437]
    DIRECTION OUTPUT ;
    USE SIGNAL ;
    SHAPE ABUTMENT ;
    PORT
      LAYER M3 ;
      RECT 52.335 0.000 52.353 0.054 ;
    END
  END w0_wd_in[437]
  PIN w0_wd_in[438]
    DIRECTION OUTPUT ;
    USE SIGNAL ;
    SHAPE ABUTMENT ;
    PORT
      LAYER M3 ;
      RECT 52.623 0.000 52.641 0.054 ;
    END
  END w0_wd_in[438]
  PIN w0_wd_in[439]
    DIRECTION OUTPUT ;
    USE SIGNAL ;
    SHAPE ABUTMENT ;
    PORT
      LAYER M3 ;
      RECT 52.911 0.000 52.929 0.054 ;
    END
  END w0_wd_in[439]
  PIN w0_wd_in[440]
    DIRECTION OUTPUT ;
    USE SIGNAL ;
    SHAPE ABUTMENT ;
    PORT
      LAYER M3 ;
      RECT 53.199 0.000 53.217 0.054 ;
    END
  END w0_wd_in[440]
  PIN w0_wd_in[441]
    DIRECTION OUTPUT ;
    USE SIGNAL ;
    SHAPE ABUTMENT ;
    PORT
      LAYER M3 ;
      RECT 53.487 0.000 53.505 0.054 ;
    END
  END w0_wd_in[441]
  PIN w0_wd_in[442]
    DIRECTION OUTPUT ;
    USE SIGNAL ;
    SHAPE ABUTMENT ;
    PORT
      LAYER M3 ;
      RECT 53.775 0.000 53.793 0.054 ;
    END
  END w0_wd_in[442]
  PIN w0_wd_in[443]
    DIRECTION OUTPUT ;
    USE SIGNAL ;
    SHAPE ABUTMENT ;
    PORT
      LAYER M3 ;
      RECT 54.063 0.000 54.081 0.054 ;
    END
  END w0_wd_in[443]
  PIN w0_wd_in[444]
    DIRECTION OUTPUT ;
    USE SIGNAL ;
    SHAPE ABUTMENT ;
    PORT
      LAYER M3 ;
      RECT 54.351 0.000 54.369 0.054 ;
    END
  END w0_wd_in[444]
  PIN w0_wd_in[445]
    DIRECTION OUTPUT ;
    USE SIGNAL ;
    SHAPE ABUTMENT ;
    PORT
      LAYER M3 ;
      RECT 54.639 0.000 54.657 0.054 ;
    END
  END w0_wd_in[445]
  PIN w0_wd_in[446]
    DIRECTION OUTPUT ;
    USE SIGNAL ;
    SHAPE ABUTMENT ;
    PORT
      LAYER M3 ;
      RECT 54.927 0.000 54.945 0.054 ;
    END
  END w0_wd_in[446]
  PIN w0_wd_in[447]
    DIRECTION OUTPUT ;
    USE SIGNAL ;
    SHAPE ABUTMENT ;
    PORT
      LAYER M3 ;
      RECT 55.215 0.000 55.233 0.054 ;
    END
  END w0_wd_in[447]
  PIN w0_wd_in[448]
    DIRECTION OUTPUT ;
    USE SIGNAL ;
    SHAPE ABUTMENT ;
    PORT
      LAYER M3 ;
      RECT 55.503 0.000 55.521 0.054 ;
    END
  END w0_wd_in[448]
  PIN w0_wd_in[449]
    DIRECTION OUTPUT ;
    USE SIGNAL ;
    SHAPE ABUTMENT ;
    PORT
      LAYER M3 ;
      RECT 55.791 0.000 55.809 0.054 ;
    END
  END w0_wd_in[449]
  PIN w0_wd_in[450]
    DIRECTION OUTPUT ;
    USE SIGNAL ;
    SHAPE ABUTMENT ;
    PORT
      LAYER M3 ;
      RECT 56.079 0.000 56.097 0.054 ;
    END
  END w0_wd_in[450]
  PIN w0_wd_in[451]
    DIRECTION OUTPUT ;
    USE SIGNAL ;
    SHAPE ABUTMENT ;
    PORT
      LAYER M3 ;
      RECT 56.367 0.000 56.385 0.054 ;
    END
  END w0_wd_in[451]
  PIN w0_wd_in[452]
    DIRECTION OUTPUT ;
    USE SIGNAL ;
    SHAPE ABUTMENT ;
    PORT
      LAYER M3 ;
      RECT 56.655 0.000 56.673 0.054 ;
    END
  END w0_wd_in[452]
  PIN w0_wd_in[453]
    DIRECTION OUTPUT ;
    USE SIGNAL ;
    SHAPE ABUTMENT ;
    PORT
      LAYER M3 ;
      RECT 56.943 0.000 56.961 0.054 ;
    END
  END w0_wd_in[453]
  PIN w0_wd_in[454]
    DIRECTION OUTPUT ;
    USE SIGNAL ;
    SHAPE ABUTMENT ;
    PORT
      LAYER M3 ;
      RECT 57.231 0.000 57.249 0.054 ;
    END
  END w0_wd_in[454]
  PIN w0_wd_in[455]
    DIRECTION OUTPUT ;
    USE SIGNAL ;
    SHAPE ABUTMENT ;
    PORT
      LAYER M3 ;
      RECT 57.519 0.000 57.537 0.054 ;
    END
  END w0_wd_in[455]
  PIN w0_wd_in[456]
    DIRECTION OUTPUT ;
    USE SIGNAL ;
    SHAPE ABUTMENT ;
    PORT
      LAYER M3 ;
      RECT 57.807 0.000 57.825 0.054 ;
    END
  END w0_wd_in[456]
  PIN w0_wd_in[457]
    DIRECTION OUTPUT ;
    USE SIGNAL ;
    SHAPE ABUTMENT ;
    PORT
      LAYER M3 ;
      RECT 58.095 0.000 58.113 0.054 ;
    END
  END w0_wd_in[457]
  PIN w0_wd_in[458]
    DIRECTION OUTPUT ;
    USE SIGNAL ;
    SHAPE ABUTMENT ;
    PORT
      LAYER M3 ;
      RECT 58.383 0.000 58.401 0.054 ;
    END
  END w0_wd_in[458]
  PIN w0_wd_in[459]
    DIRECTION OUTPUT ;
    USE SIGNAL ;
    SHAPE ABUTMENT ;
    PORT
      LAYER M3 ;
      RECT 58.671 0.000 58.689 0.054 ;
    END
  END w0_wd_in[459]
  PIN w0_wd_in[460]
    DIRECTION OUTPUT ;
    USE SIGNAL ;
    SHAPE ABUTMENT ;
    PORT
      LAYER M3 ;
      RECT 58.959 0.000 58.977 0.054 ;
    END
  END w0_wd_in[460]
  PIN w0_wd_in[461]
    DIRECTION OUTPUT ;
    USE SIGNAL ;
    SHAPE ABUTMENT ;
    PORT
      LAYER M3 ;
      RECT 59.247 0.000 59.265 0.054 ;
    END
  END w0_wd_in[461]
  PIN w0_wd_in[462]
    DIRECTION OUTPUT ;
    USE SIGNAL ;
    SHAPE ABUTMENT ;
    PORT
      LAYER M3 ;
      RECT 59.535 0.000 59.553 0.054 ;
    END
  END w0_wd_in[462]
  PIN w0_wd_in[463]
    DIRECTION OUTPUT ;
    USE SIGNAL ;
    SHAPE ABUTMENT ;
    PORT
      LAYER M3 ;
      RECT 59.823 0.000 59.841 0.054 ;
    END
  END w0_wd_in[463]
  PIN w0_wd_in[464]
    DIRECTION OUTPUT ;
    USE SIGNAL ;
    SHAPE ABUTMENT ;
    PORT
      LAYER M3 ;
      RECT 60.111 0.000 60.129 0.054 ;
    END
  END w0_wd_in[464]
  PIN w0_wd_in[465]
    DIRECTION OUTPUT ;
    USE SIGNAL ;
    SHAPE ABUTMENT ;
    PORT
      LAYER M3 ;
      RECT 60.399 0.000 60.417 0.054 ;
    END
  END w0_wd_in[465]
  PIN w0_wd_in[466]
    DIRECTION OUTPUT ;
    USE SIGNAL ;
    SHAPE ABUTMENT ;
    PORT
      LAYER M3 ;
      RECT 60.687 0.000 60.705 0.054 ;
    END
  END w0_wd_in[466]
  PIN w0_wd_in[467]
    DIRECTION OUTPUT ;
    USE SIGNAL ;
    SHAPE ABUTMENT ;
    PORT
      LAYER M3 ;
      RECT 60.975 0.000 60.993 0.054 ;
    END
  END w0_wd_in[467]
  PIN w0_wd_in[468]
    DIRECTION OUTPUT ;
    USE SIGNAL ;
    SHAPE ABUTMENT ;
    PORT
      LAYER M3 ;
      RECT 61.263 0.000 61.281 0.054 ;
    END
  END w0_wd_in[468]
  PIN w0_wd_in[469]
    DIRECTION OUTPUT ;
    USE SIGNAL ;
    SHAPE ABUTMENT ;
    PORT
      LAYER M3 ;
      RECT 61.551 0.000 61.569 0.054 ;
    END
  END w0_wd_in[469]
  PIN w0_wd_in[470]
    DIRECTION OUTPUT ;
    USE SIGNAL ;
    SHAPE ABUTMENT ;
    PORT
      LAYER M3 ;
      RECT 61.839 0.000 61.857 0.054 ;
    END
  END w0_wd_in[470]
  PIN w0_wd_in[471]
    DIRECTION OUTPUT ;
    USE SIGNAL ;
    SHAPE ABUTMENT ;
    PORT
      LAYER M3 ;
      RECT 62.127 0.000 62.145 0.054 ;
    END
  END w0_wd_in[471]
  PIN w0_wd_in[472]
    DIRECTION OUTPUT ;
    USE SIGNAL ;
    SHAPE ABUTMENT ;
    PORT
      LAYER M3 ;
      RECT 62.415 0.000 62.433 0.054 ;
    END
  END w0_wd_in[472]
  PIN w0_wd_in[473]
    DIRECTION OUTPUT ;
    USE SIGNAL ;
    SHAPE ABUTMENT ;
    PORT
      LAYER M3 ;
      RECT 62.703 0.000 62.721 0.054 ;
    END
  END w0_wd_in[473]
  PIN w0_wd_in[474]
    DIRECTION OUTPUT ;
    USE SIGNAL ;
    SHAPE ABUTMENT ;
    PORT
      LAYER M3 ;
      RECT 62.991 0.000 63.009 0.054 ;
    END
  END w0_wd_in[474]
  PIN w0_wd_in[475]
    DIRECTION OUTPUT ;
    USE SIGNAL ;
    SHAPE ABUTMENT ;
    PORT
      LAYER M3 ;
      RECT 63.279 0.000 63.297 0.054 ;
    END
  END w0_wd_in[475]
  PIN w0_wd_in[476]
    DIRECTION OUTPUT ;
    USE SIGNAL ;
    SHAPE ABUTMENT ;
    PORT
      LAYER M3 ;
      RECT 63.567 0.000 63.585 0.054 ;
    END
  END w0_wd_in[476]
  PIN w0_wd_in[477]
    DIRECTION OUTPUT ;
    USE SIGNAL ;
    SHAPE ABUTMENT ;
    PORT
      LAYER M3 ;
      RECT 63.855 0.000 63.873 0.054 ;
    END
  END w0_wd_in[477]
  PIN w0_wd_in[478]
    DIRECTION OUTPUT ;
    USE SIGNAL ;
    SHAPE ABUTMENT ;
    PORT
      LAYER M3 ;
      RECT 64.143 0.000 64.161 0.054 ;
    END
  END w0_wd_in[478]
  PIN w0_wd_in[479]
    DIRECTION OUTPUT ;
    USE SIGNAL ;
    SHAPE ABUTMENT ;
    PORT
      LAYER M3 ;
      RECT 64.431 0.000 64.449 0.054 ;
    END
  END w0_wd_in[479]
  PIN w0_wd_in[480]
    DIRECTION OUTPUT ;
    USE SIGNAL ;
    SHAPE ABUTMENT ;
    PORT
      LAYER M3 ;
      RECT 64.719 0.000 64.737 0.054 ;
    END
  END w0_wd_in[480]
  PIN w0_wd_in[481]
    DIRECTION OUTPUT ;
    USE SIGNAL ;
    SHAPE ABUTMENT ;
    PORT
      LAYER M3 ;
      RECT 65.007 0.000 65.025 0.054 ;
    END
  END w0_wd_in[481]
  PIN w0_wd_in[482]
    DIRECTION OUTPUT ;
    USE SIGNAL ;
    SHAPE ABUTMENT ;
    PORT
      LAYER M3 ;
      RECT 65.295 0.000 65.313 0.054 ;
    END
  END w0_wd_in[482]
  PIN w0_wd_in[483]
    DIRECTION OUTPUT ;
    USE SIGNAL ;
    SHAPE ABUTMENT ;
    PORT
      LAYER M3 ;
      RECT 65.583 0.000 65.601 0.054 ;
    END
  END w0_wd_in[483]
  PIN w0_wd_in[484]
    DIRECTION OUTPUT ;
    USE SIGNAL ;
    SHAPE ABUTMENT ;
    PORT
      LAYER M3 ;
      RECT 65.871 0.000 65.889 0.054 ;
    END
  END w0_wd_in[484]
  PIN w0_wd_in[485]
    DIRECTION OUTPUT ;
    USE SIGNAL ;
    SHAPE ABUTMENT ;
    PORT
      LAYER M3 ;
      RECT 66.159 0.000 66.177 0.054 ;
    END
  END w0_wd_in[485]
  PIN w0_wd_in[486]
    DIRECTION OUTPUT ;
    USE SIGNAL ;
    SHAPE ABUTMENT ;
    PORT
      LAYER M3 ;
      RECT 66.447 0.000 66.465 0.054 ;
    END
  END w0_wd_in[486]
  PIN w0_wd_in[487]
    DIRECTION OUTPUT ;
    USE SIGNAL ;
    SHAPE ABUTMENT ;
    PORT
      LAYER M3 ;
      RECT 66.735 0.000 66.753 0.054 ;
    END
  END w0_wd_in[487]
  PIN w0_wd_in[488]
    DIRECTION OUTPUT ;
    USE SIGNAL ;
    SHAPE ABUTMENT ;
    PORT
      LAYER M3 ;
      RECT 67.023 0.000 67.041 0.054 ;
    END
  END w0_wd_in[488]
  PIN w0_wd_in[489]
    DIRECTION OUTPUT ;
    USE SIGNAL ;
    SHAPE ABUTMENT ;
    PORT
      LAYER M3 ;
      RECT 67.311 0.000 67.329 0.054 ;
    END
  END w0_wd_in[489]
  PIN w0_wd_in[490]
    DIRECTION OUTPUT ;
    USE SIGNAL ;
    SHAPE ABUTMENT ;
    PORT
      LAYER M3 ;
      RECT 67.599 0.000 67.617 0.054 ;
    END
  END w0_wd_in[490]
  PIN w0_wd_in[491]
    DIRECTION OUTPUT ;
    USE SIGNAL ;
    SHAPE ABUTMENT ;
    PORT
      LAYER M3 ;
      RECT 67.887 0.000 67.905 0.054 ;
    END
  END w0_wd_in[491]
  PIN w0_wd_in[492]
    DIRECTION OUTPUT ;
    USE SIGNAL ;
    SHAPE ABUTMENT ;
    PORT
      LAYER M3 ;
      RECT 68.175 0.000 68.193 0.054 ;
    END
  END w0_wd_in[492]
  PIN w0_wd_in[493]
    DIRECTION OUTPUT ;
    USE SIGNAL ;
    SHAPE ABUTMENT ;
    PORT
      LAYER M3 ;
      RECT 68.463 0.000 68.481 0.054 ;
    END
  END w0_wd_in[493]
  PIN w0_wd_in[494]
    DIRECTION OUTPUT ;
    USE SIGNAL ;
    SHAPE ABUTMENT ;
    PORT
      LAYER M3 ;
      RECT 68.751 0.000 68.769 0.054 ;
    END
  END w0_wd_in[494]
  PIN w0_wd_in[495]
    DIRECTION OUTPUT ;
    USE SIGNAL ;
    SHAPE ABUTMENT ;
    PORT
      LAYER M3 ;
      RECT 69.039 0.000 69.057 0.054 ;
    END
  END w0_wd_in[495]
  PIN w0_wd_in[496]
    DIRECTION OUTPUT ;
    USE SIGNAL ;
    SHAPE ABUTMENT ;
    PORT
      LAYER M3 ;
      RECT 69.327 0.000 69.345 0.054 ;
    END
  END w0_wd_in[496]
  PIN w0_wd_in[497]
    DIRECTION OUTPUT ;
    USE SIGNAL ;
    SHAPE ABUTMENT ;
    PORT
      LAYER M3 ;
      RECT 69.615 0.000 69.633 0.054 ;
    END
  END w0_wd_in[497]
  PIN w0_wd_in[498]
    DIRECTION OUTPUT ;
    USE SIGNAL ;
    SHAPE ABUTMENT ;
    PORT
      LAYER M3 ;
      RECT 69.903 0.000 69.921 0.054 ;
    END
  END w0_wd_in[498]
  PIN w0_wd_in[499]
    DIRECTION OUTPUT ;
    USE SIGNAL ;
    SHAPE ABUTMENT ;
    PORT
      LAYER M3 ;
      RECT 70.191 0.000 70.209 0.054 ;
    END
  END w0_wd_in[499]
  PIN w0_wd_in[500]
    DIRECTION OUTPUT ;
    USE SIGNAL ;
    SHAPE ABUTMENT ;
    PORT
      LAYER M3 ;
      RECT 70.479 0.000 70.497 0.054 ;
    END
  END w0_wd_in[500]
  PIN w0_wd_in[501]
    DIRECTION OUTPUT ;
    USE SIGNAL ;
    SHAPE ABUTMENT ;
    PORT
      LAYER M3 ;
      RECT 70.767 0.000 70.785 0.054 ;
    END
  END w0_wd_in[501]
  PIN w0_wd_in[502]
    DIRECTION OUTPUT ;
    USE SIGNAL ;
    SHAPE ABUTMENT ;
    PORT
      LAYER M3 ;
      RECT 71.055 0.000 71.073 0.054 ;
    END
  END w0_wd_in[502]
  PIN w0_wd_in[503]
    DIRECTION OUTPUT ;
    USE SIGNAL ;
    SHAPE ABUTMENT ;
    PORT
      LAYER M3 ;
      RECT 71.343 0.000 71.361 0.054 ;
    END
  END w0_wd_in[503]
  PIN w0_wd_in[504]
    DIRECTION OUTPUT ;
    USE SIGNAL ;
    SHAPE ABUTMENT ;
    PORT
      LAYER M3 ;
      RECT 71.631 0.000 71.649 0.054 ;
    END
  END w0_wd_in[504]
  PIN w0_wd_in[505]
    DIRECTION OUTPUT ;
    USE SIGNAL ;
    SHAPE ABUTMENT ;
    PORT
      LAYER M3 ;
      RECT 71.919 0.000 71.937 0.054 ;
    END
  END w0_wd_in[505]
  PIN w0_wd_in[506]
    DIRECTION OUTPUT ;
    USE SIGNAL ;
    SHAPE ABUTMENT ;
    PORT
      LAYER M3 ;
      RECT 72.207 0.000 72.225 0.054 ;
    END
  END w0_wd_in[506]
  PIN w0_wd_in[507]
    DIRECTION OUTPUT ;
    USE SIGNAL ;
    SHAPE ABUTMENT ;
    PORT
      LAYER M3 ;
      RECT 72.495 0.000 72.513 0.054 ;
    END
  END w0_wd_in[507]
  PIN w0_wd_in[508]
    DIRECTION OUTPUT ;
    USE SIGNAL ;
    SHAPE ABUTMENT ;
    PORT
      LAYER M3 ;
      RECT 72.783 0.000 72.801 0.054 ;
    END
  END w0_wd_in[508]
  PIN w0_wd_in[509]
    DIRECTION OUTPUT ;
    USE SIGNAL ;
    SHAPE ABUTMENT ;
    PORT
      LAYER M3 ;
      RECT 73.071 0.000 73.089 0.054 ;
    END
  END w0_wd_in[509]
  PIN w0_wd_in[510]
    DIRECTION OUTPUT ;
    USE SIGNAL ;
    SHAPE ABUTMENT ;
    PORT
      LAYER M3 ;
      RECT 73.359 0.000 73.377 0.054 ;
    END
  END w0_wd_in[510]
  PIN w0_wd_in[511]
    DIRECTION OUTPUT ;
    USE SIGNAL ;
    SHAPE ABUTMENT ;
    PORT
      LAYER M3 ;
      RECT 73.647 0.000 73.665 0.054 ;
    END
  END w0_wd_in[511]
  PIN r0_rd_out[0]
    DIRECTION OUTPUT ;
    USE SIGNAL ;
    SHAPE ABUTMENT ;
    PORT
      LAYER M3 ;
      RECT 73.935 0.000 73.953 0.054 ;
    END
  END r0_rd_out[0]
  PIN r0_rd_out[1]
    DIRECTION OUTPUT ;
    USE SIGNAL ;
    SHAPE ABUTMENT ;
    PORT
      LAYER M3 ;
      RECT 74.223 0.000 74.241 0.054 ;
    END
  END r0_rd_out[1]
  PIN r0_rd_out[2]
    DIRECTION OUTPUT ;
    USE SIGNAL ;
    SHAPE ABUTMENT ;
    PORT
      LAYER M3 ;
      RECT 74.511 0.000 74.529 0.054 ;
    END
  END r0_rd_out[2]
  PIN r0_rd_out[3]
    DIRECTION OUTPUT ;
    USE SIGNAL ;
    SHAPE ABUTMENT ;
    PORT
      LAYER M3 ;
      RECT 74.799 0.000 74.817 0.054 ;
    END
  END r0_rd_out[3]
  PIN r0_rd_out[4]
    DIRECTION OUTPUT ;
    USE SIGNAL ;
    SHAPE ABUTMENT ;
    PORT
      LAYER M3 ;
      RECT 75.087 0.000 75.105 0.054 ;
    END
  END r0_rd_out[4]
  PIN r0_rd_out[5]
    DIRECTION OUTPUT ;
    USE SIGNAL ;
    SHAPE ABUTMENT ;
    PORT
      LAYER M3 ;
      RECT 75.375 0.000 75.393 0.054 ;
    END
  END r0_rd_out[5]
  PIN r0_rd_out[6]
    DIRECTION OUTPUT ;
    USE SIGNAL ;
    SHAPE ABUTMENT ;
    PORT
      LAYER M3 ;
      RECT 75.663 0.000 75.681 0.054 ;
    END
  END r0_rd_out[6]
  PIN r0_rd_out[7]
    DIRECTION OUTPUT ;
    USE SIGNAL ;
    SHAPE ABUTMENT ;
    PORT
      LAYER M3 ;
      RECT 75.951 0.000 75.969 0.054 ;
    END
  END r0_rd_out[7]
  PIN r0_rd_out[8]
    DIRECTION OUTPUT ;
    USE SIGNAL ;
    SHAPE ABUTMENT ;
    PORT
      LAYER M3 ;
      RECT 76.239 0.000 76.257 0.054 ;
    END
  END r0_rd_out[8]
  PIN r0_rd_out[9]
    DIRECTION OUTPUT ;
    USE SIGNAL ;
    SHAPE ABUTMENT ;
    PORT
      LAYER M3 ;
      RECT 76.527 0.000 76.545 0.054 ;
    END
  END r0_rd_out[9]
  PIN r0_rd_out[10]
    DIRECTION OUTPUT ;
    USE SIGNAL ;
    SHAPE ABUTMENT ;
    PORT
      LAYER M3 ;
      RECT 76.815 0.000 76.833 0.054 ;
    END
  END r0_rd_out[10]
  PIN r0_rd_out[11]
    DIRECTION OUTPUT ;
    USE SIGNAL ;
    SHAPE ABUTMENT ;
    PORT
      LAYER M3 ;
      RECT 77.103 0.000 77.121 0.054 ;
    END
  END r0_rd_out[11]
  PIN r0_rd_out[12]
    DIRECTION OUTPUT ;
    USE SIGNAL ;
    SHAPE ABUTMENT ;
    PORT
      LAYER M3 ;
      RECT 77.391 0.000 77.409 0.054 ;
    END
  END r0_rd_out[12]
  PIN r0_rd_out[13]
    DIRECTION OUTPUT ;
    USE SIGNAL ;
    SHAPE ABUTMENT ;
    PORT
      LAYER M3 ;
      RECT 77.679 0.000 77.697 0.054 ;
    END
  END r0_rd_out[13]
  PIN r0_rd_out[14]
    DIRECTION OUTPUT ;
    USE SIGNAL ;
    SHAPE ABUTMENT ;
    PORT
      LAYER M3 ;
      RECT 77.967 0.000 77.985 0.054 ;
    END
  END r0_rd_out[14]
  PIN r0_rd_out[15]
    DIRECTION OUTPUT ;
    USE SIGNAL ;
    SHAPE ABUTMENT ;
    PORT
      LAYER M3 ;
      RECT 78.255 0.000 78.273 0.054 ;
    END
  END r0_rd_out[15]
  PIN r0_rd_out[16]
    DIRECTION OUTPUT ;
    USE SIGNAL ;
    SHAPE ABUTMENT ;
    PORT
      LAYER M3 ;
      RECT 78.543 0.000 78.561 0.054 ;
    END
  END r0_rd_out[16]
  PIN r0_rd_out[17]
    DIRECTION OUTPUT ;
    USE SIGNAL ;
    SHAPE ABUTMENT ;
    PORT
      LAYER M3 ;
      RECT 78.831 0.000 78.849 0.054 ;
    END
  END r0_rd_out[17]
  PIN r0_rd_out[18]
    DIRECTION OUTPUT ;
    USE SIGNAL ;
    SHAPE ABUTMENT ;
    PORT
      LAYER M3 ;
      RECT 79.119 0.000 79.137 0.054 ;
    END
  END r0_rd_out[18]
  PIN r0_rd_out[19]
    DIRECTION OUTPUT ;
    USE SIGNAL ;
    SHAPE ABUTMENT ;
    PORT
      LAYER M3 ;
      RECT 79.407 0.000 79.425 0.054 ;
    END
  END r0_rd_out[19]
  PIN r0_rd_out[20]
    DIRECTION OUTPUT ;
    USE SIGNAL ;
    SHAPE ABUTMENT ;
    PORT
      LAYER M3 ;
      RECT 79.695 0.000 79.713 0.054 ;
    END
  END r0_rd_out[20]
  PIN r0_rd_out[21]
    DIRECTION OUTPUT ;
    USE SIGNAL ;
    SHAPE ABUTMENT ;
    PORT
      LAYER M3 ;
      RECT 79.983 0.000 80.001 0.054 ;
    END
  END r0_rd_out[21]
  PIN r0_rd_out[22]
    DIRECTION OUTPUT ;
    USE SIGNAL ;
    SHAPE ABUTMENT ;
    PORT
      LAYER M3 ;
      RECT 80.271 0.000 80.289 0.054 ;
    END
  END r0_rd_out[22]
  PIN r0_rd_out[23]
    DIRECTION OUTPUT ;
    USE SIGNAL ;
    SHAPE ABUTMENT ;
    PORT
      LAYER M3 ;
      RECT 80.559 0.000 80.577 0.054 ;
    END
  END r0_rd_out[23]
  PIN r0_rd_out[24]
    DIRECTION OUTPUT ;
    USE SIGNAL ;
    SHAPE ABUTMENT ;
    PORT
      LAYER M3 ;
      RECT 80.847 0.000 80.865 0.054 ;
    END
  END r0_rd_out[24]
  PIN r0_rd_out[25]
    DIRECTION OUTPUT ;
    USE SIGNAL ;
    SHAPE ABUTMENT ;
    PORT
      LAYER M3 ;
      RECT 81.135 0.000 81.153 0.054 ;
    END
  END r0_rd_out[25]
  PIN r0_rd_out[26]
    DIRECTION OUTPUT ;
    USE SIGNAL ;
    SHAPE ABUTMENT ;
    PORT
      LAYER M3 ;
      RECT 81.423 0.000 81.441 0.054 ;
    END
  END r0_rd_out[26]
  PIN r0_rd_out[27]
    DIRECTION OUTPUT ;
    USE SIGNAL ;
    SHAPE ABUTMENT ;
    PORT
      LAYER M3 ;
      RECT 81.711 0.000 81.729 0.054 ;
    END
  END r0_rd_out[27]
  PIN r0_rd_out[28]
    DIRECTION OUTPUT ;
    USE SIGNAL ;
    SHAPE ABUTMENT ;
    PORT
      LAYER M3 ;
      RECT 81.999 0.000 82.017 0.054 ;
    END
  END r0_rd_out[28]
  PIN r0_rd_out[29]
    DIRECTION OUTPUT ;
    USE SIGNAL ;
    SHAPE ABUTMENT ;
    PORT
      LAYER M3 ;
      RECT 82.287 0.000 82.305 0.054 ;
    END
  END r0_rd_out[29]
  PIN r0_rd_out[30]
    DIRECTION OUTPUT ;
    USE SIGNAL ;
    SHAPE ABUTMENT ;
    PORT
      LAYER M3 ;
      RECT 82.575 0.000 82.593 0.054 ;
    END
  END r0_rd_out[30]
  PIN r0_rd_out[31]
    DIRECTION OUTPUT ;
    USE SIGNAL ;
    SHAPE ABUTMENT ;
    PORT
      LAYER M3 ;
      RECT 82.863 0.000 82.881 0.054 ;
    END
  END r0_rd_out[31]
  PIN r0_rd_out[32]
    DIRECTION OUTPUT ;
    USE SIGNAL ;
    SHAPE ABUTMENT ;
    PORT
      LAYER M3 ;
      RECT 83.151 0.000 83.169 0.054 ;
    END
  END r0_rd_out[32]
  PIN r0_rd_out[33]
    DIRECTION OUTPUT ;
    USE SIGNAL ;
    SHAPE ABUTMENT ;
    PORT
      LAYER M3 ;
      RECT 83.439 0.000 83.457 0.054 ;
    END
  END r0_rd_out[33]
  PIN r0_rd_out[34]
    DIRECTION OUTPUT ;
    USE SIGNAL ;
    SHAPE ABUTMENT ;
    PORT
      LAYER M3 ;
      RECT 83.727 0.000 83.745 0.054 ;
    END
  END r0_rd_out[34]
  PIN r0_rd_out[35]
    DIRECTION OUTPUT ;
    USE SIGNAL ;
    SHAPE ABUTMENT ;
    PORT
      LAYER M3 ;
      RECT 84.015 0.000 84.033 0.054 ;
    END
  END r0_rd_out[35]
  PIN r0_rd_out[36]
    DIRECTION OUTPUT ;
    USE SIGNAL ;
    SHAPE ABUTMENT ;
    PORT
      LAYER M3 ;
      RECT 84.303 0.000 84.321 0.054 ;
    END
  END r0_rd_out[36]
  PIN r0_rd_out[37]
    DIRECTION OUTPUT ;
    USE SIGNAL ;
    SHAPE ABUTMENT ;
    PORT
      LAYER M3 ;
      RECT 84.591 0.000 84.609 0.054 ;
    END
  END r0_rd_out[37]
  PIN r0_rd_out[38]
    DIRECTION OUTPUT ;
    USE SIGNAL ;
    SHAPE ABUTMENT ;
    PORT
      LAYER M3 ;
      RECT 84.879 0.000 84.897 0.054 ;
    END
  END r0_rd_out[38]
  PIN r0_rd_out[39]
    DIRECTION OUTPUT ;
    USE SIGNAL ;
    SHAPE ABUTMENT ;
    PORT
      LAYER M3 ;
      RECT 85.167 0.000 85.185 0.054 ;
    END
  END r0_rd_out[39]
  PIN r0_rd_out[40]
    DIRECTION OUTPUT ;
    USE SIGNAL ;
    SHAPE ABUTMENT ;
    PORT
      LAYER M3 ;
      RECT 85.455 0.000 85.473 0.054 ;
    END
  END r0_rd_out[40]
  PIN r0_rd_out[41]
    DIRECTION OUTPUT ;
    USE SIGNAL ;
    SHAPE ABUTMENT ;
    PORT
      LAYER M3 ;
      RECT 85.743 0.000 85.761 0.054 ;
    END
  END r0_rd_out[41]
  PIN r0_rd_out[42]
    DIRECTION OUTPUT ;
    USE SIGNAL ;
    SHAPE ABUTMENT ;
    PORT
      LAYER M3 ;
      RECT 86.031 0.000 86.049 0.054 ;
    END
  END r0_rd_out[42]
  PIN r0_rd_out[43]
    DIRECTION OUTPUT ;
    USE SIGNAL ;
    SHAPE ABUTMENT ;
    PORT
      LAYER M3 ;
      RECT 86.319 0.000 86.337 0.054 ;
    END
  END r0_rd_out[43]
  PIN r0_rd_out[44]
    DIRECTION OUTPUT ;
    USE SIGNAL ;
    SHAPE ABUTMENT ;
    PORT
      LAYER M3 ;
      RECT 86.607 0.000 86.625 0.054 ;
    END
  END r0_rd_out[44]
  PIN r0_rd_out[45]
    DIRECTION OUTPUT ;
    USE SIGNAL ;
    SHAPE ABUTMENT ;
    PORT
      LAYER M3 ;
      RECT 86.895 0.000 86.913 0.054 ;
    END
  END r0_rd_out[45]
  PIN r0_rd_out[46]
    DIRECTION OUTPUT ;
    USE SIGNAL ;
    SHAPE ABUTMENT ;
    PORT
      LAYER M3 ;
      RECT 87.183 0.000 87.201 0.054 ;
    END
  END r0_rd_out[46]
  PIN r0_rd_out[47]
    DIRECTION OUTPUT ;
    USE SIGNAL ;
    SHAPE ABUTMENT ;
    PORT
      LAYER M3 ;
      RECT 87.471 0.000 87.489 0.054 ;
    END
  END r0_rd_out[47]
  PIN r0_rd_out[48]
    DIRECTION OUTPUT ;
    USE SIGNAL ;
    SHAPE ABUTMENT ;
    PORT
      LAYER M3 ;
      RECT 87.759 0.000 87.777 0.054 ;
    END
  END r0_rd_out[48]
  PIN r0_rd_out[49]
    DIRECTION OUTPUT ;
    USE SIGNAL ;
    SHAPE ABUTMENT ;
    PORT
      LAYER M3 ;
      RECT 88.047 0.000 88.065 0.054 ;
    END
  END r0_rd_out[49]
  PIN r0_rd_out[50]
    DIRECTION OUTPUT ;
    USE SIGNAL ;
    SHAPE ABUTMENT ;
    PORT
      LAYER M3 ;
      RECT 88.335 0.000 88.353 0.054 ;
    END
  END r0_rd_out[50]
  PIN r0_rd_out[51]
    DIRECTION OUTPUT ;
    USE SIGNAL ;
    SHAPE ABUTMENT ;
    PORT
      LAYER M3 ;
      RECT 88.623 0.000 88.641 0.054 ;
    END
  END r0_rd_out[51]
  PIN r0_rd_out[52]
    DIRECTION OUTPUT ;
    USE SIGNAL ;
    SHAPE ABUTMENT ;
    PORT
      LAYER M3 ;
      RECT 88.911 0.000 88.929 0.054 ;
    END
  END r0_rd_out[52]
  PIN r0_rd_out[53]
    DIRECTION OUTPUT ;
    USE SIGNAL ;
    SHAPE ABUTMENT ;
    PORT
      LAYER M3 ;
      RECT 89.199 0.000 89.217 0.054 ;
    END
  END r0_rd_out[53]
  PIN r0_rd_out[54]
    DIRECTION OUTPUT ;
    USE SIGNAL ;
    SHAPE ABUTMENT ;
    PORT
      LAYER M3 ;
      RECT 89.487 0.000 89.505 0.054 ;
    END
  END r0_rd_out[54]
  PIN r0_rd_out[55]
    DIRECTION OUTPUT ;
    USE SIGNAL ;
    SHAPE ABUTMENT ;
    PORT
      LAYER M3 ;
      RECT 89.775 0.000 89.793 0.054 ;
    END
  END r0_rd_out[55]
  PIN r0_rd_out[56]
    DIRECTION OUTPUT ;
    USE SIGNAL ;
    SHAPE ABUTMENT ;
    PORT
      LAYER M3 ;
      RECT 90.063 0.000 90.081 0.054 ;
    END
  END r0_rd_out[56]
  PIN r0_rd_out[57]
    DIRECTION OUTPUT ;
    USE SIGNAL ;
    SHAPE ABUTMENT ;
    PORT
      LAYER M3 ;
      RECT 90.351 0.000 90.369 0.054 ;
    END
  END r0_rd_out[57]
  PIN r0_rd_out[58]
    DIRECTION OUTPUT ;
    USE SIGNAL ;
    SHAPE ABUTMENT ;
    PORT
      LAYER M3 ;
      RECT 90.639 0.000 90.657 0.054 ;
    END
  END r0_rd_out[58]
  PIN r0_rd_out[59]
    DIRECTION OUTPUT ;
    USE SIGNAL ;
    SHAPE ABUTMENT ;
    PORT
      LAYER M3 ;
      RECT 90.927 0.000 90.945 0.054 ;
    END
  END r0_rd_out[59]
  PIN r0_rd_out[60]
    DIRECTION OUTPUT ;
    USE SIGNAL ;
    SHAPE ABUTMENT ;
    PORT
      LAYER M3 ;
      RECT 91.215 0.000 91.233 0.054 ;
    END
  END r0_rd_out[60]
  PIN r0_rd_out[61]
    DIRECTION OUTPUT ;
    USE SIGNAL ;
    SHAPE ABUTMENT ;
    PORT
      LAYER M3 ;
      RECT 91.503 0.000 91.521 0.054 ;
    END
  END r0_rd_out[61]
  PIN r0_rd_out[62]
    DIRECTION OUTPUT ;
    USE SIGNAL ;
    SHAPE ABUTMENT ;
    PORT
      LAYER M3 ;
      RECT 91.791 0.000 91.809 0.054 ;
    END
  END r0_rd_out[62]
  PIN r0_rd_out[63]
    DIRECTION OUTPUT ;
    USE SIGNAL ;
    SHAPE ABUTMENT ;
    PORT
      LAYER M3 ;
      RECT 92.079 0.000 92.097 0.054 ;
    END
  END r0_rd_out[63]
  PIN r0_rd_out[64]
    DIRECTION OUTPUT ;
    USE SIGNAL ;
    SHAPE ABUTMENT ;
    PORT
      LAYER M3 ;
      RECT 92.367 0.000 92.385 0.054 ;
    END
  END r0_rd_out[64]
  PIN r0_rd_out[65]
    DIRECTION OUTPUT ;
    USE SIGNAL ;
    SHAPE ABUTMENT ;
    PORT
      LAYER M3 ;
      RECT 92.655 0.000 92.673 0.054 ;
    END
  END r0_rd_out[65]
  PIN r0_rd_out[66]
    DIRECTION OUTPUT ;
    USE SIGNAL ;
    SHAPE ABUTMENT ;
    PORT
      LAYER M3 ;
      RECT 92.943 0.000 92.961 0.054 ;
    END
  END r0_rd_out[66]
  PIN r0_rd_out[67]
    DIRECTION OUTPUT ;
    USE SIGNAL ;
    SHAPE ABUTMENT ;
    PORT
      LAYER M3 ;
      RECT 93.231 0.000 93.249 0.054 ;
    END
  END r0_rd_out[67]
  PIN r0_rd_out[68]
    DIRECTION OUTPUT ;
    USE SIGNAL ;
    SHAPE ABUTMENT ;
    PORT
      LAYER M3 ;
      RECT 93.519 0.000 93.537 0.054 ;
    END
  END r0_rd_out[68]
  PIN r0_rd_out[69]
    DIRECTION OUTPUT ;
    USE SIGNAL ;
    SHAPE ABUTMENT ;
    PORT
      LAYER M3 ;
      RECT 93.807 0.000 93.825 0.054 ;
    END
  END r0_rd_out[69]
  PIN r0_rd_out[70]
    DIRECTION OUTPUT ;
    USE SIGNAL ;
    SHAPE ABUTMENT ;
    PORT
      LAYER M3 ;
      RECT 94.095 0.000 94.113 0.054 ;
    END
  END r0_rd_out[70]
  PIN r0_rd_out[71]
    DIRECTION OUTPUT ;
    USE SIGNAL ;
    SHAPE ABUTMENT ;
    PORT
      LAYER M3 ;
      RECT 94.383 0.000 94.401 0.054 ;
    END
  END r0_rd_out[71]
  PIN r0_rd_out[72]
    DIRECTION OUTPUT ;
    USE SIGNAL ;
    SHAPE ABUTMENT ;
    PORT
      LAYER M3 ;
      RECT 94.671 0.000 94.689 0.054 ;
    END
  END r0_rd_out[72]
  PIN r0_rd_out[73]
    DIRECTION OUTPUT ;
    USE SIGNAL ;
    SHAPE ABUTMENT ;
    PORT
      LAYER M3 ;
      RECT 94.959 0.000 94.977 0.054 ;
    END
  END r0_rd_out[73]
  PIN r0_rd_out[74]
    DIRECTION OUTPUT ;
    USE SIGNAL ;
    SHAPE ABUTMENT ;
    PORT
      LAYER M3 ;
      RECT 95.247 0.000 95.265 0.054 ;
    END
  END r0_rd_out[74]
  PIN r0_rd_out[75]
    DIRECTION OUTPUT ;
    USE SIGNAL ;
    SHAPE ABUTMENT ;
    PORT
      LAYER M3 ;
      RECT 95.535 0.000 95.553 0.054 ;
    END
  END r0_rd_out[75]
  PIN r0_rd_out[76]
    DIRECTION OUTPUT ;
    USE SIGNAL ;
    SHAPE ABUTMENT ;
    PORT
      LAYER M3 ;
      RECT 95.823 0.000 95.841 0.054 ;
    END
  END r0_rd_out[76]
  PIN r0_rd_out[77]
    DIRECTION OUTPUT ;
    USE SIGNAL ;
    SHAPE ABUTMENT ;
    PORT
      LAYER M3 ;
      RECT 96.111 0.000 96.129 0.054 ;
    END
  END r0_rd_out[77]
  PIN r0_rd_out[78]
    DIRECTION OUTPUT ;
    USE SIGNAL ;
    SHAPE ABUTMENT ;
    PORT
      LAYER M3 ;
      RECT 96.399 0.000 96.417 0.054 ;
    END
  END r0_rd_out[78]
  PIN r0_rd_out[79]
    DIRECTION OUTPUT ;
    USE SIGNAL ;
    SHAPE ABUTMENT ;
    PORT
      LAYER M3 ;
      RECT 96.687 0.000 96.705 0.054 ;
    END
  END r0_rd_out[79]
  PIN r0_rd_out[80]
    DIRECTION OUTPUT ;
    USE SIGNAL ;
    SHAPE ABUTMENT ;
    PORT
      LAYER M3 ;
      RECT 96.975 0.000 96.993 0.054 ;
    END
  END r0_rd_out[80]
  PIN r0_rd_out[81]
    DIRECTION OUTPUT ;
    USE SIGNAL ;
    SHAPE ABUTMENT ;
    PORT
      LAYER M3 ;
      RECT 97.263 0.000 97.281 0.054 ;
    END
  END r0_rd_out[81]
  PIN r0_rd_out[82]
    DIRECTION OUTPUT ;
    USE SIGNAL ;
    SHAPE ABUTMENT ;
    PORT
      LAYER M3 ;
      RECT 97.551 0.000 97.569 0.054 ;
    END
  END r0_rd_out[82]
  PIN r0_rd_out[83]
    DIRECTION OUTPUT ;
    USE SIGNAL ;
    SHAPE ABUTMENT ;
    PORT
      LAYER M3 ;
      RECT 97.839 0.000 97.857 0.054 ;
    END
  END r0_rd_out[83]
  PIN r0_rd_out[84]
    DIRECTION OUTPUT ;
    USE SIGNAL ;
    SHAPE ABUTMENT ;
    PORT
      LAYER M3 ;
      RECT 98.127 0.000 98.145 0.054 ;
    END
  END r0_rd_out[84]
  PIN r0_rd_out[85]
    DIRECTION OUTPUT ;
    USE SIGNAL ;
    SHAPE ABUTMENT ;
    PORT
      LAYER M3 ;
      RECT 98.415 0.000 98.433 0.054 ;
    END
  END r0_rd_out[85]
  PIN r0_rd_out[86]
    DIRECTION OUTPUT ;
    USE SIGNAL ;
    SHAPE ABUTMENT ;
    PORT
      LAYER M3 ;
      RECT 98.703 0.000 98.721 0.054 ;
    END
  END r0_rd_out[86]
  PIN r0_rd_out[87]
    DIRECTION OUTPUT ;
    USE SIGNAL ;
    SHAPE ABUTMENT ;
    PORT
      LAYER M3 ;
      RECT 98.991 0.000 99.009 0.054 ;
    END
  END r0_rd_out[87]
  PIN r0_rd_out[88]
    DIRECTION OUTPUT ;
    USE SIGNAL ;
    SHAPE ABUTMENT ;
    PORT
      LAYER M3 ;
      RECT 99.279 0.000 99.297 0.054 ;
    END
  END r0_rd_out[88]
  PIN r0_rd_out[89]
    DIRECTION OUTPUT ;
    USE SIGNAL ;
    SHAPE ABUTMENT ;
    PORT
      LAYER M3 ;
      RECT 99.567 0.000 99.585 0.054 ;
    END
  END r0_rd_out[89]
  PIN r0_rd_out[90]
    DIRECTION OUTPUT ;
    USE SIGNAL ;
    SHAPE ABUTMENT ;
    PORT
      LAYER M3 ;
      RECT 99.855 0.000 99.873 0.054 ;
    END
  END r0_rd_out[90]
  PIN r0_rd_out[91]
    DIRECTION OUTPUT ;
    USE SIGNAL ;
    SHAPE ABUTMENT ;
    PORT
      LAYER M3 ;
      RECT 100.143 0.000 100.161 0.054 ;
    END
  END r0_rd_out[91]
  PIN r0_rd_out[92]
    DIRECTION OUTPUT ;
    USE SIGNAL ;
    SHAPE ABUTMENT ;
    PORT
      LAYER M3 ;
      RECT 100.431 0.000 100.449 0.054 ;
    END
  END r0_rd_out[92]
  PIN r0_rd_out[93]
    DIRECTION OUTPUT ;
    USE SIGNAL ;
    SHAPE ABUTMENT ;
    PORT
      LAYER M3 ;
      RECT 100.719 0.000 100.737 0.054 ;
    END
  END r0_rd_out[93]
  PIN r0_rd_out[94]
    DIRECTION OUTPUT ;
    USE SIGNAL ;
    SHAPE ABUTMENT ;
    PORT
      LAYER M3 ;
      RECT 101.007 0.000 101.025 0.054 ;
    END
  END r0_rd_out[94]
  PIN r0_rd_out[95]
    DIRECTION OUTPUT ;
    USE SIGNAL ;
    SHAPE ABUTMENT ;
    PORT
      LAYER M3 ;
      RECT 101.295 0.000 101.313 0.054 ;
    END
  END r0_rd_out[95]
  PIN r0_rd_out[96]
    DIRECTION OUTPUT ;
    USE SIGNAL ;
    SHAPE ABUTMENT ;
    PORT
      LAYER M3 ;
      RECT 101.583 0.000 101.601 0.054 ;
    END
  END r0_rd_out[96]
  PIN r0_rd_out[97]
    DIRECTION OUTPUT ;
    USE SIGNAL ;
    SHAPE ABUTMENT ;
    PORT
      LAYER M3 ;
      RECT 101.871 0.000 101.889 0.054 ;
    END
  END r0_rd_out[97]
  PIN r0_rd_out[98]
    DIRECTION OUTPUT ;
    USE SIGNAL ;
    SHAPE ABUTMENT ;
    PORT
      LAYER M3 ;
      RECT 102.159 0.000 102.177 0.054 ;
    END
  END r0_rd_out[98]
  PIN r0_rd_out[99]
    DIRECTION OUTPUT ;
    USE SIGNAL ;
    SHAPE ABUTMENT ;
    PORT
      LAYER M3 ;
      RECT 102.447 0.000 102.465 0.054 ;
    END
  END r0_rd_out[99]
  PIN r0_rd_out[100]
    DIRECTION OUTPUT ;
    USE SIGNAL ;
    SHAPE ABUTMENT ;
    PORT
      LAYER M3 ;
      RECT 102.735 0.000 102.753 0.054 ;
    END
  END r0_rd_out[100]
  PIN r0_rd_out[101]
    DIRECTION OUTPUT ;
    USE SIGNAL ;
    SHAPE ABUTMENT ;
    PORT
      LAYER M3 ;
      RECT 103.023 0.000 103.041 0.054 ;
    END
  END r0_rd_out[101]
  PIN r0_rd_out[102]
    DIRECTION OUTPUT ;
    USE SIGNAL ;
    SHAPE ABUTMENT ;
    PORT
      LAYER M3 ;
      RECT 103.311 0.000 103.329 0.054 ;
    END
  END r0_rd_out[102]
  PIN r0_rd_out[103]
    DIRECTION OUTPUT ;
    USE SIGNAL ;
    SHAPE ABUTMENT ;
    PORT
      LAYER M3 ;
      RECT 103.599 0.000 103.617 0.054 ;
    END
  END r0_rd_out[103]
  PIN r0_rd_out[104]
    DIRECTION OUTPUT ;
    USE SIGNAL ;
    SHAPE ABUTMENT ;
    PORT
      LAYER M3 ;
      RECT 103.887 0.000 103.905 0.054 ;
    END
  END r0_rd_out[104]
  PIN r0_rd_out[105]
    DIRECTION OUTPUT ;
    USE SIGNAL ;
    SHAPE ABUTMENT ;
    PORT
      LAYER M3 ;
      RECT 104.175 0.000 104.193 0.054 ;
    END
  END r0_rd_out[105]
  PIN r0_rd_out[106]
    DIRECTION OUTPUT ;
    USE SIGNAL ;
    SHAPE ABUTMENT ;
    PORT
      LAYER M3 ;
      RECT 104.463 0.000 104.481 0.054 ;
    END
  END r0_rd_out[106]
  PIN r0_rd_out[107]
    DIRECTION OUTPUT ;
    USE SIGNAL ;
    SHAPE ABUTMENT ;
    PORT
      LAYER M3 ;
      RECT 104.751 0.000 104.769 0.054 ;
    END
  END r0_rd_out[107]
  PIN r0_rd_out[108]
    DIRECTION OUTPUT ;
    USE SIGNAL ;
    SHAPE ABUTMENT ;
    PORT
      LAYER M3 ;
      RECT 105.039 0.000 105.057 0.054 ;
    END
  END r0_rd_out[108]
  PIN r0_rd_out[109]
    DIRECTION OUTPUT ;
    USE SIGNAL ;
    SHAPE ABUTMENT ;
    PORT
      LAYER M3 ;
      RECT 105.327 0.000 105.345 0.054 ;
    END
  END r0_rd_out[109]
  PIN r0_rd_out[110]
    DIRECTION OUTPUT ;
    USE SIGNAL ;
    SHAPE ABUTMENT ;
    PORT
      LAYER M3 ;
      RECT 105.615 0.000 105.633 0.054 ;
    END
  END r0_rd_out[110]
  PIN r0_rd_out[111]
    DIRECTION OUTPUT ;
    USE SIGNAL ;
    SHAPE ABUTMENT ;
    PORT
      LAYER M3 ;
      RECT 105.903 0.000 105.921 0.054 ;
    END
  END r0_rd_out[111]
  PIN r0_rd_out[112]
    DIRECTION OUTPUT ;
    USE SIGNAL ;
    SHAPE ABUTMENT ;
    PORT
      LAYER M3 ;
      RECT 106.191 0.000 106.209 0.054 ;
    END
  END r0_rd_out[112]
  PIN r0_rd_out[113]
    DIRECTION OUTPUT ;
    USE SIGNAL ;
    SHAPE ABUTMENT ;
    PORT
      LAYER M3 ;
      RECT 106.479 0.000 106.497 0.054 ;
    END
  END r0_rd_out[113]
  PIN r0_rd_out[114]
    DIRECTION OUTPUT ;
    USE SIGNAL ;
    SHAPE ABUTMENT ;
    PORT
      LAYER M3 ;
      RECT 106.767 0.000 106.785 0.054 ;
    END
  END r0_rd_out[114]
  PIN r0_rd_out[115]
    DIRECTION OUTPUT ;
    USE SIGNAL ;
    SHAPE ABUTMENT ;
    PORT
      LAYER M3 ;
      RECT 107.055 0.000 107.073 0.054 ;
    END
  END r0_rd_out[115]
  PIN r0_rd_out[116]
    DIRECTION OUTPUT ;
    USE SIGNAL ;
    SHAPE ABUTMENT ;
    PORT
      LAYER M3 ;
      RECT 107.343 0.000 107.361 0.054 ;
    END
  END r0_rd_out[116]
  PIN r0_rd_out[117]
    DIRECTION OUTPUT ;
    USE SIGNAL ;
    SHAPE ABUTMENT ;
    PORT
      LAYER M3 ;
      RECT 107.631 0.000 107.649 0.054 ;
    END
  END r0_rd_out[117]
  PIN r0_rd_out[118]
    DIRECTION OUTPUT ;
    USE SIGNAL ;
    SHAPE ABUTMENT ;
    PORT
      LAYER M3 ;
      RECT 107.919 0.000 107.937 0.054 ;
    END
  END r0_rd_out[118]
  PIN r0_rd_out[119]
    DIRECTION OUTPUT ;
    USE SIGNAL ;
    SHAPE ABUTMENT ;
    PORT
      LAYER M3 ;
      RECT 108.207 0.000 108.225 0.054 ;
    END
  END r0_rd_out[119]
  PIN r0_rd_out[120]
    DIRECTION OUTPUT ;
    USE SIGNAL ;
    SHAPE ABUTMENT ;
    PORT
      LAYER M3 ;
      RECT 108.495 0.000 108.513 0.054 ;
    END
  END r0_rd_out[120]
  PIN r0_rd_out[121]
    DIRECTION OUTPUT ;
    USE SIGNAL ;
    SHAPE ABUTMENT ;
    PORT
      LAYER M3 ;
      RECT 108.783 0.000 108.801 0.054 ;
    END
  END r0_rd_out[121]
  PIN r0_rd_out[122]
    DIRECTION OUTPUT ;
    USE SIGNAL ;
    SHAPE ABUTMENT ;
    PORT
      LAYER M3 ;
      RECT 109.071 0.000 109.089 0.054 ;
    END
  END r0_rd_out[122]
  PIN r0_rd_out[123]
    DIRECTION OUTPUT ;
    USE SIGNAL ;
    SHAPE ABUTMENT ;
    PORT
      LAYER M3 ;
      RECT 109.359 0.000 109.377 0.054 ;
    END
  END r0_rd_out[123]
  PIN r0_rd_out[124]
    DIRECTION OUTPUT ;
    USE SIGNAL ;
    SHAPE ABUTMENT ;
    PORT
      LAYER M3 ;
      RECT 109.647 0.000 109.665 0.054 ;
    END
  END r0_rd_out[124]
  PIN r0_rd_out[125]
    DIRECTION OUTPUT ;
    USE SIGNAL ;
    SHAPE ABUTMENT ;
    PORT
      LAYER M3 ;
      RECT 109.935 0.000 109.953 0.054 ;
    END
  END r0_rd_out[125]
  PIN r0_rd_out[126]
    DIRECTION OUTPUT ;
    USE SIGNAL ;
    SHAPE ABUTMENT ;
    PORT
      LAYER M3 ;
      RECT 110.223 0.000 110.241 0.054 ;
    END
  END r0_rd_out[126]
  PIN r0_rd_out[127]
    DIRECTION OUTPUT ;
    USE SIGNAL ;
    SHAPE ABUTMENT ;
    PORT
      LAYER M3 ;
      RECT 110.511 0.000 110.529 0.054 ;
    END
  END r0_rd_out[127]
  PIN r0_rd_out[128]
    DIRECTION OUTPUT ;
    USE SIGNAL ;
    SHAPE ABUTMENT ;
    PORT
      LAYER M3 ;
      RECT 110.799 0.000 110.817 0.054 ;
    END
  END r0_rd_out[128]
  PIN r0_rd_out[129]
    DIRECTION OUTPUT ;
    USE SIGNAL ;
    SHAPE ABUTMENT ;
    PORT
      LAYER M3 ;
      RECT 111.087 0.000 111.105 0.054 ;
    END
  END r0_rd_out[129]
  PIN r0_rd_out[130]
    DIRECTION OUTPUT ;
    USE SIGNAL ;
    SHAPE ABUTMENT ;
    PORT
      LAYER M3 ;
      RECT 111.375 0.000 111.393 0.054 ;
    END
  END r0_rd_out[130]
  PIN r0_rd_out[131]
    DIRECTION OUTPUT ;
    USE SIGNAL ;
    SHAPE ABUTMENT ;
    PORT
      LAYER M3 ;
      RECT 111.663 0.000 111.681 0.054 ;
    END
  END r0_rd_out[131]
  PIN r0_rd_out[132]
    DIRECTION OUTPUT ;
    USE SIGNAL ;
    SHAPE ABUTMENT ;
    PORT
      LAYER M3 ;
      RECT 111.951 0.000 111.969 0.054 ;
    END
  END r0_rd_out[132]
  PIN r0_rd_out[133]
    DIRECTION OUTPUT ;
    USE SIGNAL ;
    SHAPE ABUTMENT ;
    PORT
      LAYER M3 ;
      RECT 112.239 0.000 112.257 0.054 ;
    END
  END r0_rd_out[133]
  PIN r0_rd_out[134]
    DIRECTION OUTPUT ;
    USE SIGNAL ;
    SHAPE ABUTMENT ;
    PORT
      LAYER M3 ;
      RECT 112.527 0.000 112.545 0.054 ;
    END
  END r0_rd_out[134]
  PIN r0_rd_out[135]
    DIRECTION OUTPUT ;
    USE SIGNAL ;
    SHAPE ABUTMENT ;
    PORT
      LAYER M3 ;
      RECT 112.815 0.000 112.833 0.054 ;
    END
  END r0_rd_out[135]
  PIN r0_rd_out[136]
    DIRECTION OUTPUT ;
    USE SIGNAL ;
    SHAPE ABUTMENT ;
    PORT
      LAYER M3 ;
      RECT 113.103 0.000 113.121 0.054 ;
    END
  END r0_rd_out[136]
  PIN r0_rd_out[137]
    DIRECTION OUTPUT ;
    USE SIGNAL ;
    SHAPE ABUTMENT ;
    PORT
      LAYER M3 ;
      RECT 113.391 0.000 113.409 0.054 ;
    END
  END r0_rd_out[137]
  PIN r0_rd_out[138]
    DIRECTION OUTPUT ;
    USE SIGNAL ;
    SHAPE ABUTMENT ;
    PORT
      LAYER M3 ;
      RECT 113.679 0.000 113.697 0.054 ;
    END
  END r0_rd_out[138]
  PIN r0_rd_out[139]
    DIRECTION OUTPUT ;
    USE SIGNAL ;
    SHAPE ABUTMENT ;
    PORT
      LAYER M3 ;
      RECT 113.967 0.000 113.985 0.054 ;
    END
  END r0_rd_out[139]
  PIN r0_rd_out[140]
    DIRECTION OUTPUT ;
    USE SIGNAL ;
    SHAPE ABUTMENT ;
    PORT
      LAYER M3 ;
      RECT 114.255 0.000 114.273 0.054 ;
    END
  END r0_rd_out[140]
  PIN r0_rd_out[141]
    DIRECTION OUTPUT ;
    USE SIGNAL ;
    SHAPE ABUTMENT ;
    PORT
      LAYER M3 ;
      RECT 114.543 0.000 114.561 0.054 ;
    END
  END r0_rd_out[141]
  PIN r0_rd_out[142]
    DIRECTION OUTPUT ;
    USE SIGNAL ;
    SHAPE ABUTMENT ;
    PORT
      LAYER M3 ;
      RECT 114.831 0.000 114.849 0.054 ;
    END
  END r0_rd_out[142]
  PIN r0_rd_out[143]
    DIRECTION OUTPUT ;
    USE SIGNAL ;
    SHAPE ABUTMENT ;
    PORT
      LAYER M3 ;
      RECT 115.119 0.000 115.137 0.054 ;
    END
  END r0_rd_out[143]
  PIN r0_rd_out[144]
    DIRECTION OUTPUT ;
    USE SIGNAL ;
    SHAPE ABUTMENT ;
    PORT
      LAYER M3 ;
      RECT 115.407 0.000 115.425 0.054 ;
    END
  END r0_rd_out[144]
  PIN r0_rd_out[145]
    DIRECTION OUTPUT ;
    USE SIGNAL ;
    SHAPE ABUTMENT ;
    PORT
      LAYER M3 ;
      RECT 115.695 0.000 115.713 0.054 ;
    END
  END r0_rd_out[145]
  PIN r0_rd_out[146]
    DIRECTION OUTPUT ;
    USE SIGNAL ;
    SHAPE ABUTMENT ;
    PORT
      LAYER M3 ;
      RECT 115.983 0.000 116.001 0.054 ;
    END
  END r0_rd_out[146]
  PIN r0_rd_out[147]
    DIRECTION OUTPUT ;
    USE SIGNAL ;
    SHAPE ABUTMENT ;
    PORT
      LAYER M3 ;
      RECT 116.271 0.000 116.289 0.054 ;
    END
  END r0_rd_out[147]
  PIN r0_rd_out[148]
    DIRECTION OUTPUT ;
    USE SIGNAL ;
    SHAPE ABUTMENT ;
    PORT
      LAYER M3 ;
      RECT 116.559 0.000 116.577 0.054 ;
    END
  END r0_rd_out[148]
  PIN r0_rd_out[149]
    DIRECTION OUTPUT ;
    USE SIGNAL ;
    SHAPE ABUTMENT ;
    PORT
      LAYER M3 ;
      RECT 116.847 0.000 116.865 0.054 ;
    END
  END r0_rd_out[149]
  PIN r0_rd_out[150]
    DIRECTION OUTPUT ;
    USE SIGNAL ;
    SHAPE ABUTMENT ;
    PORT
      LAYER M3 ;
      RECT 117.135 0.000 117.153 0.054 ;
    END
  END r0_rd_out[150]
  PIN r0_rd_out[151]
    DIRECTION OUTPUT ;
    USE SIGNAL ;
    SHAPE ABUTMENT ;
    PORT
      LAYER M3 ;
      RECT 117.423 0.000 117.441 0.054 ;
    END
  END r0_rd_out[151]
  PIN r0_rd_out[152]
    DIRECTION OUTPUT ;
    USE SIGNAL ;
    SHAPE ABUTMENT ;
    PORT
      LAYER M3 ;
      RECT 117.711 0.000 117.729 0.054 ;
    END
  END r0_rd_out[152]
  PIN r0_rd_out[153]
    DIRECTION OUTPUT ;
    USE SIGNAL ;
    SHAPE ABUTMENT ;
    PORT
      LAYER M3 ;
      RECT 117.999 0.000 118.017 0.054 ;
    END
  END r0_rd_out[153]
  PIN r0_rd_out[154]
    DIRECTION OUTPUT ;
    USE SIGNAL ;
    SHAPE ABUTMENT ;
    PORT
      LAYER M3 ;
      RECT 118.287 0.000 118.305 0.054 ;
    END
  END r0_rd_out[154]
  PIN r0_rd_out[155]
    DIRECTION OUTPUT ;
    USE SIGNAL ;
    SHAPE ABUTMENT ;
    PORT
      LAYER M3 ;
      RECT 118.575 0.000 118.593 0.054 ;
    END
  END r0_rd_out[155]
  PIN r0_rd_out[156]
    DIRECTION OUTPUT ;
    USE SIGNAL ;
    SHAPE ABUTMENT ;
    PORT
      LAYER M3 ;
      RECT 118.863 0.000 118.881 0.054 ;
    END
  END r0_rd_out[156]
  PIN r0_rd_out[157]
    DIRECTION OUTPUT ;
    USE SIGNAL ;
    SHAPE ABUTMENT ;
    PORT
      LAYER M3 ;
      RECT 119.151 0.000 119.169 0.054 ;
    END
  END r0_rd_out[157]
  PIN r0_rd_out[158]
    DIRECTION OUTPUT ;
    USE SIGNAL ;
    SHAPE ABUTMENT ;
    PORT
      LAYER M3 ;
      RECT 119.439 0.000 119.457 0.054 ;
    END
  END r0_rd_out[158]
  PIN r0_rd_out[159]
    DIRECTION OUTPUT ;
    USE SIGNAL ;
    SHAPE ABUTMENT ;
    PORT
      LAYER M3 ;
      RECT 119.727 0.000 119.745 0.054 ;
    END
  END r0_rd_out[159]
  PIN r0_rd_out[160]
    DIRECTION OUTPUT ;
    USE SIGNAL ;
    SHAPE ABUTMENT ;
    PORT
      LAYER M3 ;
      RECT 120.015 0.000 120.033 0.054 ;
    END
  END r0_rd_out[160]
  PIN r0_rd_out[161]
    DIRECTION OUTPUT ;
    USE SIGNAL ;
    SHAPE ABUTMENT ;
    PORT
      LAYER M3 ;
      RECT 120.303 0.000 120.321 0.054 ;
    END
  END r0_rd_out[161]
  PIN r0_rd_out[162]
    DIRECTION OUTPUT ;
    USE SIGNAL ;
    SHAPE ABUTMENT ;
    PORT
      LAYER M3 ;
      RECT 120.591 0.000 120.609 0.054 ;
    END
  END r0_rd_out[162]
  PIN r0_rd_out[163]
    DIRECTION OUTPUT ;
    USE SIGNAL ;
    SHAPE ABUTMENT ;
    PORT
      LAYER M3 ;
      RECT 120.879 0.000 120.897 0.054 ;
    END
  END r0_rd_out[163]
  PIN r0_rd_out[164]
    DIRECTION OUTPUT ;
    USE SIGNAL ;
    SHAPE ABUTMENT ;
    PORT
      LAYER M3 ;
      RECT 121.167 0.000 121.185 0.054 ;
    END
  END r0_rd_out[164]
  PIN r0_rd_out[165]
    DIRECTION OUTPUT ;
    USE SIGNAL ;
    SHAPE ABUTMENT ;
    PORT
      LAYER M3 ;
      RECT 121.455 0.000 121.473 0.054 ;
    END
  END r0_rd_out[165]
  PIN r0_rd_out[166]
    DIRECTION OUTPUT ;
    USE SIGNAL ;
    SHAPE ABUTMENT ;
    PORT
      LAYER M3 ;
      RECT 121.743 0.000 121.761 0.054 ;
    END
  END r0_rd_out[166]
  PIN r0_rd_out[167]
    DIRECTION OUTPUT ;
    USE SIGNAL ;
    SHAPE ABUTMENT ;
    PORT
      LAYER M3 ;
      RECT 122.031 0.000 122.049 0.054 ;
    END
  END r0_rd_out[167]
  PIN r0_rd_out[168]
    DIRECTION OUTPUT ;
    USE SIGNAL ;
    SHAPE ABUTMENT ;
    PORT
      LAYER M3 ;
      RECT 122.319 0.000 122.337 0.054 ;
    END
  END r0_rd_out[168]
  PIN r0_rd_out[169]
    DIRECTION OUTPUT ;
    USE SIGNAL ;
    SHAPE ABUTMENT ;
    PORT
      LAYER M3 ;
      RECT 122.607 0.000 122.625 0.054 ;
    END
  END r0_rd_out[169]
  PIN r0_rd_out[170]
    DIRECTION OUTPUT ;
    USE SIGNAL ;
    SHAPE ABUTMENT ;
    PORT
      LAYER M3 ;
      RECT 122.895 0.000 122.913 0.054 ;
    END
  END r0_rd_out[170]
  PIN r0_rd_out[171]
    DIRECTION OUTPUT ;
    USE SIGNAL ;
    SHAPE ABUTMENT ;
    PORT
      LAYER M3 ;
      RECT 123.183 0.000 123.201 0.054 ;
    END
  END r0_rd_out[171]
  PIN r0_rd_out[172]
    DIRECTION OUTPUT ;
    USE SIGNAL ;
    SHAPE ABUTMENT ;
    PORT
      LAYER M3 ;
      RECT 123.471 0.000 123.489 0.054 ;
    END
  END r0_rd_out[172]
  PIN r0_rd_out[173]
    DIRECTION OUTPUT ;
    USE SIGNAL ;
    SHAPE ABUTMENT ;
    PORT
      LAYER M3 ;
      RECT 123.759 0.000 123.777 0.054 ;
    END
  END r0_rd_out[173]
  PIN r0_rd_out[174]
    DIRECTION OUTPUT ;
    USE SIGNAL ;
    SHAPE ABUTMENT ;
    PORT
      LAYER M3 ;
      RECT 124.047 0.000 124.065 0.054 ;
    END
  END r0_rd_out[174]
  PIN r0_rd_out[175]
    DIRECTION OUTPUT ;
    USE SIGNAL ;
    SHAPE ABUTMENT ;
    PORT
      LAYER M3 ;
      RECT 124.335 0.000 124.353 0.054 ;
    END
  END r0_rd_out[175]
  PIN r0_rd_out[176]
    DIRECTION OUTPUT ;
    USE SIGNAL ;
    SHAPE ABUTMENT ;
    PORT
      LAYER M3 ;
      RECT 124.623 0.000 124.641 0.054 ;
    END
  END r0_rd_out[176]
  PIN r0_rd_out[177]
    DIRECTION OUTPUT ;
    USE SIGNAL ;
    SHAPE ABUTMENT ;
    PORT
      LAYER M3 ;
      RECT 124.911 0.000 124.929 0.054 ;
    END
  END r0_rd_out[177]
  PIN r0_rd_out[178]
    DIRECTION OUTPUT ;
    USE SIGNAL ;
    SHAPE ABUTMENT ;
    PORT
      LAYER M3 ;
      RECT 125.199 0.000 125.217 0.054 ;
    END
  END r0_rd_out[178]
  PIN r0_rd_out[179]
    DIRECTION OUTPUT ;
    USE SIGNAL ;
    SHAPE ABUTMENT ;
    PORT
      LAYER M3 ;
      RECT 125.487 0.000 125.505 0.054 ;
    END
  END r0_rd_out[179]
  PIN r0_rd_out[180]
    DIRECTION OUTPUT ;
    USE SIGNAL ;
    SHAPE ABUTMENT ;
    PORT
      LAYER M3 ;
      RECT 125.775 0.000 125.793 0.054 ;
    END
  END r0_rd_out[180]
  PIN r0_rd_out[181]
    DIRECTION OUTPUT ;
    USE SIGNAL ;
    SHAPE ABUTMENT ;
    PORT
      LAYER M3 ;
      RECT 126.063 0.000 126.081 0.054 ;
    END
  END r0_rd_out[181]
  PIN r0_rd_out[182]
    DIRECTION OUTPUT ;
    USE SIGNAL ;
    SHAPE ABUTMENT ;
    PORT
      LAYER M3 ;
      RECT 126.351 0.000 126.369 0.054 ;
    END
  END r0_rd_out[182]
  PIN r0_rd_out[183]
    DIRECTION OUTPUT ;
    USE SIGNAL ;
    SHAPE ABUTMENT ;
    PORT
      LAYER M3 ;
      RECT 126.639 0.000 126.657 0.054 ;
    END
  END r0_rd_out[183]
  PIN r0_rd_out[184]
    DIRECTION OUTPUT ;
    USE SIGNAL ;
    SHAPE ABUTMENT ;
    PORT
      LAYER M3 ;
      RECT 126.927 0.000 126.945 0.054 ;
    END
  END r0_rd_out[184]
  PIN r0_rd_out[185]
    DIRECTION OUTPUT ;
    USE SIGNAL ;
    SHAPE ABUTMENT ;
    PORT
      LAYER M3 ;
      RECT 127.215 0.000 127.233 0.054 ;
    END
  END r0_rd_out[185]
  PIN r0_rd_out[186]
    DIRECTION OUTPUT ;
    USE SIGNAL ;
    SHAPE ABUTMENT ;
    PORT
      LAYER M3 ;
      RECT 127.503 0.000 127.521 0.054 ;
    END
  END r0_rd_out[186]
  PIN r0_rd_out[187]
    DIRECTION OUTPUT ;
    USE SIGNAL ;
    SHAPE ABUTMENT ;
    PORT
      LAYER M3 ;
      RECT 127.791 0.000 127.809 0.054 ;
    END
  END r0_rd_out[187]
  PIN r0_rd_out[188]
    DIRECTION OUTPUT ;
    USE SIGNAL ;
    SHAPE ABUTMENT ;
    PORT
      LAYER M3 ;
      RECT 128.079 0.000 128.097 0.054 ;
    END
  END r0_rd_out[188]
  PIN r0_rd_out[189]
    DIRECTION OUTPUT ;
    USE SIGNAL ;
    SHAPE ABUTMENT ;
    PORT
      LAYER M3 ;
      RECT 128.367 0.000 128.385 0.054 ;
    END
  END r0_rd_out[189]
  PIN r0_rd_out[190]
    DIRECTION OUTPUT ;
    USE SIGNAL ;
    SHAPE ABUTMENT ;
    PORT
      LAYER M3 ;
      RECT 128.655 0.000 128.673 0.054 ;
    END
  END r0_rd_out[190]
  PIN r0_rd_out[191]
    DIRECTION OUTPUT ;
    USE SIGNAL ;
    SHAPE ABUTMENT ;
    PORT
      LAYER M3 ;
      RECT 128.943 0.000 128.961 0.054 ;
    END
  END r0_rd_out[191]
  PIN r0_rd_out[192]
    DIRECTION OUTPUT ;
    USE SIGNAL ;
    SHAPE ABUTMENT ;
    PORT
      LAYER M3 ;
      RECT 129.231 0.000 129.249 0.054 ;
    END
  END r0_rd_out[192]
  PIN r0_rd_out[193]
    DIRECTION OUTPUT ;
    USE SIGNAL ;
    SHAPE ABUTMENT ;
    PORT
      LAYER M3 ;
      RECT 129.519 0.000 129.537 0.054 ;
    END
  END r0_rd_out[193]
  PIN r0_rd_out[194]
    DIRECTION OUTPUT ;
    USE SIGNAL ;
    SHAPE ABUTMENT ;
    PORT
      LAYER M3 ;
      RECT 129.807 0.000 129.825 0.054 ;
    END
  END r0_rd_out[194]
  PIN r0_rd_out[195]
    DIRECTION OUTPUT ;
    USE SIGNAL ;
    SHAPE ABUTMENT ;
    PORT
      LAYER M3 ;
      RECT 130.095 0.000 130.113 0.054 ;
    END
  END r0_rd_out[195]
  PIN r0_rd_out[196]
    DIRECTION OUTPUT ;
    USE SIGNAL ;
    SHAPE ABUTMENT ;
    PORT
      LAYER M3 ;
      RECT 130.383 0.000 130.401 0.054 ;
    END
  END r0_rd_out[196]
  PIN r0_rd_out[197]
    DIRECTION OUTPUT ;
    USE SIGNAL ;
    SHAPE ABUTMENT ;
    PORT
      LAYER M3 ;
      RECT 130.671 0.000 130.689 0.054 ;
    END
  END r0_rd_out[197]
  PIN r0_rd_out[198]
    DIRECTION OUTPUT ;
    USE SIGNAL ;
    SHAPE ABUTMENT ;
    PORT
      LAYER M3 ;
      RECT 130.959 0.000 130.977 0.054 ;
    END
  END r0_rd_out[198]
  PIN r0_rd_out[199]
    DIRECTION OUTPUT ;
    USE SIGNAL ;
    SHAPE ABUTMENT ;
    PORT
      LAYER M3 ;
      RECT 131.247 0.000 131.265 0.054 ;
    END
  END r0_rd_out[199]
  PIN r0_rd_out[200]
    DIRECTION OUTPUT ;
    USE SIGNAL ;
    SHAPE ABUTMENT ;
    PORT
      LAYER M3 ;
      RECT 131.535 0.000 131.553 0.054 ;
    END
  END r0_rd_out[200]
  PIN r0_rd_out[201]
    DIRECTION OUTPUT ;
    USE SIGNAL ;
    SHAPE ABUTMENT ;
    PORT
      LAYER M3 ;
      RECT 131.823 0.000 131.841 0.054 ;
    END
  END r0_rd_out[201]
  PIN r0_rd_out[202]
    DIRECTION OUTPUT ;
    USE SIGNAL ;
    SHAPE ABUTMENT ;
    PORT
      LAYER M3 ;
      RECT 132.111 0.000 132.129 0.054 ;
    END
  END r0_rd_out[202]
  PIN r0_rd_out[203]
    DIRECTION OUTPUT ;
    USE SIGNAL ;
    SHAPE ABUTMENT ;
    PORT
      LAYER M3 ;
      RECT 132.399 0.000 132.417 0.054 ;
    END
  END r0_rd_out[203]
  PIN r0_rd_out[204]
    DIRECTION OUTPUT ;
    USE SIGNAL ;
    SHAPE ABUTMENT ;
    PORT
      LAYER M3 ;
      RECT 132.687 0.000 132.705 0.054 ;
    END
  END r0_rd_out[204]
  PIN r0_rd_out[205]
    DIRECTION OUTPUT ;
    USE SIGNAL ;
    SHAPE ABUTMENT ;
    PORT
      LAYER M3 ;
      RECT 132.975 0.000 132.993 0.054 ;
    END
  END r0_rd_out[205]
  PIN r0_rd_out[206]
    DIRECTION OUTPUT ;
    USE SIGNAL ;
    SHAPE ABUTMENT ;
    PORT
      LAYER M3 ;
      RECT 133.263 0.000 133.281 0.054 ;
    END
  END r0_rd_out[206]
  PIN r0_rd_out[207]
    DIRECTION OUTPUT ;
    USE SIGNAL ;
    SHAPE ABUTMENT ;
    PORT
      LAYER M3 ;
      RECT 133.551 0.000 133.569 0.054 ;
    END
  END r0_rd_out[207]
  PIN r0_rd_out[208]
    DIRECTION OUTPUT ;
    USE SIGNAL ;
    SHAPE ABUTMENT ;
    PORT
      LAYER M3 ;
      RECT 133.839 0.000 133.857 0.054 ;
    END
  END r0_rd_out[208]
  PIN r0_rd_out[209]
    DIRECTION OUTPUT ;
    USE SIGNAL ;
    SHAPE ABUTMENT ;
    PORT
      LAYER M3 ;
      RECT 134.127 0.000 134.145 0.054 ;
    END
  END r0_rd_out[209]
  PIN r0_rd_out[210]
    DIRECTION OUTPUT ;
    USE SIGNAL ;
    SHAPE ABUTMENT ;
    PORT
      LAYER M3 ;
      RECT 134.415 0.000 134.433 0.054 ;
    END
  END r0_rd_out[210]
  PIN r0_rd_out[211]
    DIRECTION OUTPUT ;
    USE SIGNAL ;
    SHAPE ABUTMENT ;
    PORT
      LAYER M3 ;
      RECT 134.703 0.000 134.721 0.054 ;
    END
  END r0_rd_out[211]
  PIN r0_rd_out[212]
    DIRECTION OUTPUT ;
    USE SIGNAL ;
    SHAPE ABUTMENT ;
    PORT
      LAYER M3 ;
      RECT 134.991 0.000 135.009 0.054 ;
    END
  END r0_rd_out[212]
  PIN r0_rd_out[213]
    DIRECTION OUTPUT ;
    USE SIGNAL ;
    SHAPE ABUTMENT ;
    PORT
      LAYER M3 ;
      RECT 135.279 0.000 135.297 0.054 ;
    END
  END r0_rd_out[213]
  PIN r0_rd_out[214]
    DIRECTION OUTPUT ;
    USE SIGNAL ;
    SHAPE ABUTMENT ;
    PORT
      LAYER M3 ;
      RECT 135.567 0.000 135.585 0.054 ;
    END
  END r0_rd_out[214]
  PIN r0_rd_out[215]
    DIRECTION OUTPUT ;
    USE SIGNAL ;
    SHAPE ABUTMENT ;
    PORT
      LAYER M3 ;
      RECT 135.855 0.000 135.873 0.054 ;
    END
  END r0_rd_out[215]
  PIN r0_rd_out[216]
    DIRECTION OUTPUT ;
    USE SIGNAL ;
    SHAPE ABUTMENT ;
    PORT
      LAYER M3 ;
      RECT 136.143 0.000 136.161 0.054 ;
    END
  END r0_rd_out[216]
  PIN r0_rd_out[217]
    DIRECTION OUTPUT ;
    USE SIGNAL ;
    SHAPE ABUTMENT ;
    PORT
      LAYER M3 ;
      RECT 136.431 0.000 136.449 0.054 ;
    END
  END r0_rd_out[217]
  PIN r0_rd_out[218]
    DIRECTION OUTPUT ;
    USE SIGNAL ;
    SHAPE ABUTMENT ;
    PORT
      LAYER M3 ;
      RECT 136.719 0.000 136.737 0.054 ;
    END
  END r0_rd_out[218]
  PIN r0_rd_out[219]
    DIRECTION OUTPUT ;
    USE SIGNAL ;
    SHAPE ABUTMENT ;
    PORT
      LAYER M3 ;
      RECT 137.007 0.000 137.025 0.054 ;
    END
  END r0_rd_out[219]
  PIN r0_rd_out[220]
    DIRECTION OUTPUT ;
    USE SIGNAL ;
    SHAPE ABUTMENT ;
    PORT
      LAYER M3 ;
      RECT 137.295 0.000 137.313 0.054 ;
    END
  END r0_rd_out[220]
  PIN r0_rd_out[221]
    DIRECTION OUTPUT ;
    USE SIGNAL ;
    SHAPE ABUTMENT ;
    PORT
      LAYER M3 ;
      RECT 137.583 0.000 137.601 0.054 ;
    END
  END r0_rd_out[221]
  PIN r0_rd_out[222]
    DIRECTION OUTPUT ;
    USE SIGNAL ;
    SHAPE ABUTMENT ;
    PORT
      LAYER M3 ;
      RECT 137.871 0.000 137.889 0.054 ;
    END
  END r0_rd_out[222]
  PIN r0_rd_out[223]
    DIRECTION OUTPUT ;
    USE SIGNAL ;
    SHAPE ABUTMENT ;
    PORT
      LAYER M3 ;
      RECT 138.159 0.000 138.177 0.054 ;
    END
  END r0_rd_out[223]
  PIN r0_rd_out[224]
    DIRECTION OUTPUT ;
    USE SIGNAL ;
    SHAPE ABUTMENT ;
    PORT
      LAYER M3 ;
      RECT 138.447 0.000 138.465 0.054 ;
    END
  END r0_rd_out[224]
  PIN r0_rd_out[225]
    DIRECTION OUTPUT ;
    USE SIGNAL ;
    SHAPE ABUTMENT ;
    PORT
      LAYER M3 ;
      RECT 138.735 0.000 138.753 0.054 ;
    END
  END r0_rd_out[225]
  PIN r0_rd_out[226]
    DIRECTION OUTPUT ;
    USE SIGNAL ;
    SHAPE ABUTMENT ;
    PORT
      LAYER M3 ;
      RECT 139.023 0.000 139.041 0.054 ;
    END
  END r0_rd_out[226]
  PIN r0_rd_out[227]
    DIRECTION OUTPUT ;
    USE SIGNAL ;
    SHAPE ABUTMENT ;
    PORT
      LAYER M3 ;
      RECT 139.311 0.000 139.329 0.054 ;
    END
  END r0_rd_out[227]
  PIN r0_rd_out[228]
    DIRECTION OUTPUT ;
    USE SIGNAL ;
    SHAPE ABUTMENT ;
    PORT
      LAYER M3 ;
      RECT 139.599 0.000 139.617 0.054 ;
    END
  END r0_rd_out[228]
  PIN r0_rd_out[229]
    DIRECTION OUTPUT ;
    USE SIGNAL ;
    SHAPE ABUTMENT ;
    PORT
      LAYER M3 ;
      RECT 139.887 0.000 139.905 0.054 ;
    END
  END r0_rd_out[229]
  PIN r0_rd_out[230]
    DIRECTION OUTPUT ;
    USE SIGNAL ;
    SHAPE ABUTMENT ;
    PORT
      LAYER M3 ;
      RECT 140.175 0.000 140.193 0.054 ;
    END
  END r0_rd_out[230]
  PIN r0_rd_out[231]
    DIRECTION OUTPUT ;
    USE SIGNAL ;
    SHAPE ABUTMENT ;
    PORT
      LAYER M3 ;
      RECT 140.463 0.000 140.481 0.054 ;
    END
  END r0_rd_out[231]
  PIN r0_rd_out[232]
    DIRECTION OUTPUT ;
    USE SIGNAL ;
    SHAPE ABUTMENT ;
    PORT
      LAYER M3 ;
      RECT 140.751 0.000 140.769 0.054 ;
    END
  END r0_rd_out[232]
  PIN r0_rd_out[233]
    DIRECTION OUTPUT ;
    USE SIGNAL ;
    SHAPE ABUTMENT ;
    PORT
      LAYER M3 ;
      RECT 141.039 0.000 141.057 0.054 ;
    END
  END r0_rd_out[233]
  PIN r0_rd_out[234]
    DIRECTION OUTPUT ;
    USE SIGNAL ;
    SHAPE ABUTMENT ;
    PORT
      LAYER M3 ;
      RECT 141.327 0.000 141.345 0.054 ;
    END
  END r0_rd_out[234]
  PIN r0_rd_out[235]
    DIRECTION OUTPUT ;
    USE SIGNAL ;
    SHAPE ABUTMENT ;
    PORT
      LAYER M3 ;
      RECT 141.615 0.000 141.633 0.054 ;
    END
  END r0_rd_out[235]
  PIN r0_rd_out[236]
    DIRECTION OUTPUT ;
    USE SIGNAL ;
    SHAPE ABUTMENT ;
    PORT
      LAYER M3 ;
      RECT 141.903 0.000 141.921 0.054 ;
    END
  END r0_rd_out[236]
  PIN r0_rd_out[237]
    DIRECTION OUTPUT ;
    USE SIGNAL ;
    SHAPE ABUTMENT ;
    PORT
      LAYER M3 ;
      RECT 142.191 0.000 142.209 0.054 ;
    END
  END r0_rd_out[237]
  PIN r0_rd_out[238]
    DIRECTION OUTPUT ;
    USE SIGNAL ;
    SHAPE ABUTMENT ;
    PORT
      LAYER M3 ;
      RECT 142.479 0.000 142.497 0.054 ;
    END
  END r0_rd_out[238]
  PIN r0_rd_out[239]
    DIRECTION OUTPUT ;
    USE SIGNAL ;
    SHAPE ABUTMENT ;
    PORT
      LAYER M3 ;
      RECT 142.767 0.000 142.785 0.054 ;
    END
  END r0_rd_out[239]
  PIN r0_rd_out[240]
    DIRECTION OUTPUT ;
    USE SIGNAL ;
    SHAPE ABUTMENT ;
    PORT
      LAYER M3 ;
      RECT 143.055 0.000 143.073 0.054 ;
    END
  END r0_rd_out[240]
  PIN r0_rd_out[241]
    DIRECTION OUTPUT ;
    USE SIGNAL ;
    SHAPE ABUTMENT ;
    PORT
      LAYER M3 ;
      RECT 143.343 0.000 143.361 0.054 ;
    END
  END r0_rd_out[241]
  PIN r0_rd_out[242]
    DIRECTION OUTPUT ;
    USE SIGNAL ;
    SHAPE ABUTMENT ;
    PORT
      LAYER M3 ;
      RECT 143.631 0.000 143.649 0.054 ;
    END
  END r0_rd_out[242]
  PIN r0_rd_out[243]
    DIRECTION OUTPUT ;
    USE SIGNAL ;
    SHAPE ABUTMENT ;
    PORT
      LAYER M3 ;
      RECT 143.919 0.000 143.937 0.054 ;
    END
  END r0_rd_out[243]
  PIN r0_rd_out[244]
    DIRECTION OUTPUT ;
    USE SIGNAL ;
    SHAPE ABUTMENT ;
    PORT
      LAYER M3 ;
      RECT 144.207 0.000 144.225 0.054 ;
    END
  END r0_rd_out[244]
  PIN r0_rd_out[245]
    DIRECTION OUTPUT ;
    USE SIGNAL ;
    SHAPE ABUTMENT ;
    PORT
      LAYER M3 ;
      RECT 144.495 0.000 144.513 0.054 ;
    END
  END r0_rd_out[245]
  PIN r0_rd_out[246]
    DIRECTION OUTPUT ;
    USE SIGNAL ;
    SHAPE ABUTMENT ;
    PORT
      LAYER M3 ;
      RECT 144.783 0.000 144.801 0.054 ;
    END
  END r0_rd_out[246]
  PIN r0_rd_out[247]
    DIRECTION OUTPUT ;
    USE SIGNAL ;
    SHAPE ABUTMENT ;
    PORT
      LAYER M3 ;
      RECT 145.071 0.000 145.089 0.054 ;
    END
  END r0_rd_out[247]
  PIN r0_rd_out[248]
    DIRECTION OUTPUT ;
    USE SIGNAL ;
    SHAPE ABUTMENT ;
    PORT
      LAYER M3 ;
      RECT 145.359 0.000 145.377 0.054 ;
    END
  END r0_rd_out[248]
  PIN r0_rd_out[249]
    DIRECTION OUTPUT ;
    USE SIGNAL ;
    SHAPE ABUTMENT ;
    PORT
      LAYER M3 ;
      RECT 145.647 0.000 145.665 0.054 ;
    END
  END r0_rd_out[249]
  PIN r0_rd_out[250]
    DIRECTION OUTPUT ;
    USE SIGNAL ;
    SHAPE ABUTMENT ;
    PORT
      LAYER M3 ;
      RECT 145.935 0.000 145.953 0.054 ;
    END
  END r0_rd_out[250]
  PIN r0_rd_out[251]
    DIRECTION OUTPUT ;
    USE SIGNAL ;
    SHAPE ABUTMENT ;
    PORT
      LAYER M3 ;
      RECT 146.223 0.000 146.241 0.054 ;
    END
  END r0_rd_out[251]
  PIN r0_rd_out[252]
    DIRECTION OUTPUT ;
    USE SIGNAL ;
    SHAPE ABUTMENT ;
    PORT
      LAYER M3 ;
      RECT 146.511 0.000 146.529 0.054 ;
    END
  END r0_rd_out[252]
  PIN r0_rd_out[253]
    DIRECTION OUTPUT ;
    USE SIGNAL ;
    SHAPE ABUTMENT ;
    PORT
      LAYER M3 ;
      RECT 146.799 0.000 146.817 0.054 ;
    END
  END r0_rd_out[253]
  PIN r0_rd_out[254]
    DIRECTION OUTPUT ;
    USE SIGNAL ;
    SHAPE ABUTMENT ;
    PORT
      LAYER M3 ;
      RECT 147.087 0.000 147.105 0.054 ;
    END
  END r0_rd_out[254]
  PIN r0_rd_out[255]
    DIRECTION OUTPUT ;
    USE SIGNAL ;
    SHAPE ABUTMENT ;
    PORT
      LAYER M3 ;
      RECT 147.375 0.000 147.393 0.054 ;
    END
  END r0_rd_out[255]
  PIN r0_rd_out[256]
    DIRECTION OUTPUT ;
    USE SIGNAL ;
    SHAPE ABUTMENT ;
    PORT
      LAYER M3 ;
      RECT 0.207 214.219 0.225 214.273 ;
    END
  END r0_rd_out[256]
  PIN r0_rd_out[257]
    DIRECTION OUTPUT ;
    USE SIGNAL ;
    SHAPE ABUTMENT ;
    PORT
      LAYER M3 ;
      RECT 0.783 214.219 0.801 214.273 ;
    END
  END r0_rd_out[257]
  PIN r0_rd_out[258]
    DIRECTION OUTPUT ;
    USE SIGNAL ;
    SHAPE ABUTMENT ;
    PORT
      LAYER M3 ;
      RECT 1.359 214.219 1.377 214.273 ;
    END
  END r0_rd_out[258]
  PIN r0_rd_out[259]
    DIRECTION OUTPUT ;
    USE SIGNAL ;
    SHAPE ABUTMENT ;
    PORT
      LAYER M3 ;
      RECT 1.935 214.219 1.953 214.273 ;
    END
  END r0_rd_out[259]
  PIN r0_rd_out[260]
    DIRECTION OUTPUT ;
    USE SIGNAL ;
    SHAPE ABUTMENT ;
    PORT
      LAYER M3 ;
      RECT 2.511 214.219 2.529 214.273 ;
    END
  END r0_rd_out[260]
  PIN r0_rd_out[261]
    DIRECTION OUTPUT ;
    USE SIGNAL ;
    SHAPE ABUTMENT ;
    PORT
      LAYER M3 ;
      RECT 3.087 214.219 3.105 214.273 ;
    END
  END r0_rd_out[261]
  PIN r0_rd_out[262]
    DIRECTION OUTPUT ;
    USE SIGNAL ;
    SHAPE ABUTMENT ;
    PORT
      LAYER M3 ;
      RECT 3.663 214.219 3.681 214.273 ;
    END
  END r0_rd_out[262]
  PIN r0_rd_out[263]
    DIRECTION OUTPUT ;
    USE SIGNAL ;
    SHAPE ABUTMENT ;
    PORT
      LAYER M3 ;
      RECT 4.239 214.219 4.257 214.273 ;
    END
  END r0_rd_out[263]
  PIN r0_rd_out[264]
    DIRECTION OUTPUT ;
    USE SIGNAL ;
    SHAPE ABUTMENT ;
    PORT
      LAYER M3 ;
      RECT 4.815 214.219 4.833 214.273 ;
    END
  END r0_rd_out[264]
  PIN r0_rd_out[265]
    DIRECTION OUTPUT ;
    USE SIGNAL ;
    SHAPE ABUTMENT ;
    PORT
      LAYER M3 ;
      RECT 5.391 214.219 5.409 214.273 ;
    END
  END r0_rd_out[265]
  PIN r0_rd_out[266]
    DIRECTION OUTPUT ;
    USE SIGNAL ;
    SHAPE ABUTMENT ;
    PORT
      LAYER M3 ;
      RECT 5.967 214.219 5.985 214.273 ;
    END
  END r0_rd_out[266]
  PIN r0_rd_out[267]
    DIRECTION OUTPUT ;
    USE SIGNAL ;
    SHAPE ABUTMENT ;
    PORT
      LAYER M3 ;
      RECT 6.543 214.219 6.561 214.273 ;
    END
  END r0_rd_out[267]
  PIN r0_rd_out[268]
    DIRECTION OUTPUT ;
    USE SIGNAL ;
    SHAPE ABUTMENT ;
    PORT
      LAYER M3 ;
      RECT 7.119 214.219 7.137 214.273 ;
    END
  END r0_rd_out[268]
  PIN r0_rd_out[269]
    DIRECTION OUTPUT ;
    USE SIGNAL ;
    SHAPE ABUTMENT ;
    PORT
      LAYER M3 ;
      RECT 7.695 214.219 7.713 214.273 ;
    END
  END r0_rd_out[269]
  PIN r0_rd_out[270]
    DIRECTION OUTPUT ;
    USE SIGNAL ;
    SHAPE ABUTMENT ;
    PORT
      LAYER M3 ;
      RECT 8.271 214.219 8.289 214.273 ;
    END
  END r0_rd_out[270]
  PIN r0_rd_out[271]
    DIRECTION OUTPUT ;
    USE SIGNAL ;
    SHAPE ABUTMENT ;
    PORT
      LAYER M3 ;
      RECT 8.847 214.219 8.865 214.273 ;
    END
  END r0_rd_out[271]
  PIN r0_rd_out[272]
    DIRECTION OUTPUT ;
    USE SIGNAL ;
    SHAPE ABUTMENT ;
    PORT
      LAYER M3 ;
      RECT 9.423 214.219 9.441 214.273 ;
    END
  END r0_rd_out[272]
  PIN r0_rd_out[273]
    DIRECTION OUTPUT ;
    USE SIGNAL ;
    SHAPE ABUTMENT ;
    PORT
      LAYER M3 ;
      RECT 9.999 214.219 10.017 214.273 ;
    END
  END r0_rd_out[273]
  PIN r0_rd_out[274]
    DIRECTION OUTPUT ;
    USE SIGNAL ;
    SHAPE ABUTMENT ;
    PORT
      LAYER M3 ;
      RECT 10.575 214.219 10.593 214.273 ;
    END
  END r0_rd_out[274]
  PIN r0_rd_out[275]
    DIRECTION OUTPUT ;
    USE SIGNAL ;
    SHAPE ABUTMENT ;
    PORT
      LAYER M3 ;
      RECT 11.151 214.219 11.169 214.273 ;
    END
  END r0_rd_out[275]
  PIN r0_rd_out[276]
    DIRECTION OUTPUT ;
    USE SIGNAL ;
    SHAPE ABUTMENT ;
    PORT
      LAYER M3 ;
      RECT 11.727 214.219 11.745 214.273 ;
    END
  END r0_rd_out[276]
  PIN r0_rd_out[277]
    DIRECTION OUTPUT ;
    USE SIGNAL ;
    SHAPE ABUTMENT ;
    PORT
      LAYER M3 ;
      RECT 12.303 214.219 12.321 214.273 ;
    END
  END r0_rd_out[277]
  PIN r0_rd_out[278]
    DIRECTION OUTPUT ;
    USE SIGNAL ;
    SHAPE ABUTMENT ;
    PORT
      LAYER M3 ;
      RECT 12.879 214.219 12.897 214.273 ;
    END
  END r0_rd_out[278]
  PIN r0_rd_out[279]
    DIRECTION OUTPUT ;
    USE SIGNAL ;
    SHAPE ABUTMENT ;
    PORT
      LAYER M3 ;
      RECT 13.455 214.219 13.473 214.273 ;
    END
  END r0_rd_out[279]
  PIN r0_rd_out[280]
    DIRECTION OUTPUT ;
    USE SIGNAL ;
    SHAPE ABUTMENT ;
    PORT
      LAYER M3 ;
      RECT 14.031 214.219 14.049 214.273 ;
    END
  END r0_rd_out[280]
  PIN r0_rd_out[281]
    DIRECTION OUTPUT ;
    USE SIGNAL ;
    SHAPE ABUTMENT ;
    PORT
      LAYER M3 ;
      RECT 14.607 214.219 14.625 214.273 ;
    END
  END r0_rd_out[281]
  PIN r0_rd_out[282]
    DIRECTION OUTPUT ;
    USE SIGNAL ;
    SHAPE ABUTMENT ;
    PORT
      LAYER M3 ;
      RECT 15.183 214.219 15.201 214.273 ;
    END
  END r0_rd_out[282]
  PIN r0_rd_out[283]
    DIRECTION OUTPUT ;
    USE SIGNAL ;
    SHAPE ABUTMENT ;
    PORT
      LAYER M3 ;
      RECT 15.759 214.219 15.777 214.273 ;
    END
  END r0_rd_out[283]
  PIN r0_rd_out[284]
    DIRECTION OUTPUT ;
    USE SIGNAL ;
    SHAPE ABUTMENT ;
    PORT
      LAYER M3 ;
      RECT 16.335 214.219 16.353 214.273 ;
    END
  END r0_rd_out[284]
  PIN r0_rd_out[285]
    DIRECTION OUTPUT ;
    USE SIGNAL ;
    SHAPE ABUTMENT ;
    PORT
      LAYER M3 ;
      RECT 16.911 214.219 16.929 214.273 ;
    END
  END r0_rd_out[285]
  PIN r0_rd_out[286]
    DIRECTION OUTPUT ;
    USE SIGNAL ;
    SHAPE ABUTMENT ;
    PORT
      LAYER M3 ;
      RECT 17.487 214.219 17.505 214.273 ;
    END
  END r0_rd_out[286]
  PIN r0_rd_out[287]
    DIRECTION OUTPUT ;
    USE SIGNAL ;
    SHAPE ABUTMENT ;
    PORT
      LAYER M3 ;
      RECT 18.063 214.219 18.081 214.273 ;
    END
  END r0_rd_out[287]
  PIN r0_rd_out[288]
    DIRECTION OUTPUT ;
    USE SIGNAL ;
    SHAPE ABUTMENT ;
    PORT
      LAYER M3 ;
      RECT 18.639 214.219 18.657 214.273 ;
    END
  END r0_rd_out[288]
  PIN r0_rd_out[289]
    DIRECTION OUTPUT ;
    USE SIGNAL ;
    SHAPE ABUTMENT ;
    PORT
      LAYER M3 ;
      RECT 19.215 214.219 19.233 214.273 ;
    END
  END r0_rd_out[289]
  PIN r0_rd_out[290]
    DIRECTION OUTPUT ;
    USE SIGNAL ;
    SHAPE ABUTMENT ;
    PORT
      LAYER M3 ;
      RECT 19.791 214.219 19.809 214.273 ;
    END
  END r0_rd_out[290]
  PIN r0_rd_out[291]
    DIRECTION OUTPUT ;
    USE SIGNAL ;
    SHAPE ABUTMENT ;
    PORT
      LAYER M3 ;
      RECT 20.367 214.219 20.385 214.273 ;
    END
  END r0_rd_out[291]
  PIN r0_rd_out[292]
    DIRECTION OUTPUT ;
    USE SIGNAL ;
    SHAPE ABUTMENT ;
    PORT
      LAYER M3 ;
      RECT 20.943 214.219 20.961 214.273 ;
    END
  END r0_rd_out[292]
  PIN r0_rd_out[293]
    DIRECTION OUTPUT ;
    USE SIGNAL ;
    SHAPE ABUTMENT ;
    PORT
      LAYER M3 ;
      RECT 21.519 214.219 21.537 214.273 ;
    END
  END r0_rd_out[293]
  PIN r0_rd_out[294]
    DIRECTION OUTPUT ;
    USE SIGNAL ;
    SHAPE ABUTMENT ;
    PORT
      LAYER M3 ;
      RECT 22.095 214.219 22.113 214.273 ;
    END
  END r0_rd_out[294]
  PIN r0_rd_out[295]
    DIRECTION OUTPUT ;
    USE SIGNAL ;
    SHAPE ABUTMENT ;
    PORT
      LAYER M3 ;
      RECT 22.671 214.219 22.689 214.273 ;
    END
  END r0_rd_out[295]
  PIN r0_rd_out[296]
    DIRECTION OUTPUT ;
    USE SIGNAL ;
    SHAPE ABUTMENT ;
    PORT
      LAYER M3 ;
      RECT 23.247 214.219 23.265 214.273 ;
    END
  END r0_rd_out[296]
  PIN r0_rd_out[297]
    DIRECTION OUTPUT ;
    USE SIGNAL ;
    SHAPE ABUTMENT ;
    PORT
      LAYER M3 ;
      RECT 23.823 214.219 23.841 214.273 ;
    END
  END r0_rd_out[297]
  PIN r0_rd_out[298]
    DIRECTION OUTPUT ;
    USE SIGNAL ;
    SHAPE ABUTMENT ;
    PORT
      LAYER M3 ;
      RECT 24.399 214.219 24.417 214.273 ;
    END
  END r0_rd_out[298]
  PIN r0_rd_out[299]
    DIRECTION OUTPUT ;
    USE SIGNAL ;
    SHAPE ABUTMENT ;
    PORT
      LAYER M3 ;
      RECT 24.975 214.219 24.993 214.273 ;
    END
  END r0_rd_out[299]
  PIN r0_rd_out[300]
    DIRECTION OUTPUT ;
    USE SIGNAL ;
    SHAPE ABUTMENT ;
    PORT
      LAYER M3 ;
      RECT 25.551 214.219 25.569 214.273 ;
    END
  END r0_rd_out[300]
  PIN r0_rd_out[301]
    DIRECTION OUTPUT ;
    USE SIGNAL ;
    SHAPE ABUTMENT ;
    PORT
      LAYER M3 ;
      RECT 26.127 214.219 26.145 214.273 ;
    END
  END r0_rd_out[301]
  PIN r0_rd_out[302]
    DIRECTION OUTPUT ;
    USE SIGNAL ;
    SHAPE ABUTMENT ;
    PORT
      LAYER M3 ;
      RECT 26.703 214.219 26.721 214.273 ;
    END
  END r0_rd_out[302]
  PIN r0_rd_out[303]
    DIRECTION OUTPUT ;
    USE SIGNAL ;
    SHAPE ABUTMENT ;
    PORT
      LAYER M3 ;
      RECT 27.279 214.219 27.297 214.273 ;
    END
  END r0_rd_out[303]
  PIN r0_rd_out[304]
    DIRECTION OUTPUT ;
    USE SIGNAL ;
    SHAPE ABUTMENT ;
    PORT
      LAYER M3 ;
      RECT 27.855 214.219 27.873 214.273 ;
    END
  END r0_rd_out[304]
  PIN r0_rd_out[305]
    DIRECTION OUTPUT ;
    USE SIGNAL ;
    SHAPE ABUTMENT ;
    PORT
      LAYER M3 ;
      RECT 28.431 214.219 28.449 214.273 ;
    END
  END r0_rd_out[305]
  PIN r0_rd_out[306]
    DIRECTION OUTPUT ;
    USE SIGNAL ;
    SHAPE ABUTMENT ;
    PORT
      LAYER M3 ;
      RECT 29.007 214.219 29.025 214.273 ;
    END
  END r0_rd_out[306]
  PIN r0_rd_out[307]
    DIRECTION OUTPUT ;
    USE SIGNAL ;
    SHAPE ABUTMENT ;
    PORT
      LAYER M3 ;
      RECT 29.583 214.219 29.601 214.273 ;
    END
  END r0_rd_out[307]
  PIN r0_rd_out[308]
    DIRECTION OUTPUT ;
    USE SIGNAL ;
    SHAPE ABUTMENT ;
    PORT
      LAYER M3 ;
      RECT 30.159 214.219 30.177 214.273 ;
    END
  END r0_rd_out[308]
  PIN r0_rd_out[309]
    DIRECTION OUTPUT ;
    USE SIGNAL ;
    SHAPE ABUTMENT ;
    PORT
      LAYER M3 ;
      RECT 30.735 214.219 30.753 214.273 ;
    END
  END r0_rd_out[309]
  PIN r0_rd_out[310]
    DIRECTION OUTPUT ;
    USE SIGNAL ;
    SHAPE ABUTMENT ;
    PORT
      LAYER M3 ;
      RECT 31.311 214.219 31.329 214.273 ;
    END
  END r0_rd_out[310]
  PIN r0_rd_out[311]
    DIRECTION OUTPUT ;
    USE SIGNAL ;
    SHAPE ABUTMENT ;
    PORT
      LAYER M3 ;
      RECT 31.887 214.219 31.905 214.273 ;
    END
  END r0_rd_out[311]
  PIN r0_rd_out[312]
    DIRECTION OUTPUT ;
    USE SIGNAL ;
    SHAPE ABUTMENT ;
    PORT
      LAYER M3 ;
      RECT 32.463 214.219 32.481 214.273 ;
    END
  END r0_rd_out[312]
  PIN r0_rd_out[313]
    DIRECTION OUTPUT ;
    USE SIGNAL ;
    SHAPE ABUTMENT ;
    PORT
      LAYER M3 ;
      RECT 33.039 214.219 33.057 214.273 ;
    END
  END r0_rd_out[313]
  PIN r0_rd_out[314]
    DIRECTION OUTPUT ;
    USE SIGNAL ;
    SHAPE ABUTMENT ;
    PORT
      LAYER M3 ;
      RECT 33.615 214.219 33.633 214.273 ;
    END
  END r0_rd_out[314]
  PIN r0_rd_out[315]
    DIRECTION OUTPUT ;
    USE SIGNAL ;
    SHAPE ABUTMENT ;
    PORT
      LAYER M3 ;
      RECT 34.191 214.219 34.209 214.273 ;
    END
  END r0_rd_out[315]
  PIN r0_rd_out[316]
    DIRECTION OUTPUT ;
    USE SIGNAL ;
    SHAPE ABUTMENT ;
    PORT
      LAYER M3 ;
      RECT 34.767 214.219 34.785 214.273 ;
    END
  END r0_rd_out[316]
  PIN r0_rd_out[317]
    DIRECTION OUTPUT ;
    USE SIGNAL ;
    SHAPE ABUTMENT ;
    PORT
      LAYER M3 ;
      RECT 35.343 214.219 35.361 214.273 ;
    END
  END r0_rd_out[317]
  PIN r0_rd_out[318]
    DIRECTION OUTPUT ;
    USE SIGNAL ;
    SHAPE ABUTMENT ;
    PORT
      LAYER M3 ;
      RECT 35.919 214.219 35.937 214.273 ;
    END
  END r0_rd_out[318]
  PIN r0_rd_out[319]
    DIRECTION OUTPUT ;
    USE SIGNAL ;
    SHAPE ABUTMENT ;
    PORT
      LAYER M3 ;
      RECT 36.495 214.219 36.513 214.273 ;
    END
  END r0_rd_out[319]
  PIN r0_rd_out[320]
    DIRECTION OUTPUT ;
    USE SIGNAL ;
    SHAPE ABUTMENT ;
    PORT
      LAYER M3 ;
      RECT 37.071 214.219 37.089 214.273 ;
    END
  END r0_rd_out[320]
  PIN r0_rd_out[321]
    DIRECTION OUTPUT ;
    USE SIGNAL ;
    SHAPE ABUTMENT ;
    PORT
      LAYER M3 ;
      RECT 37.647 214.219 37.665 214.273 ;
    END
  END r0_rd_out[321]
  PIN r0_rd_out[322]
    DIRECTION OUTPUT ;
    USE SIGNAL ;
    SHAPE ABUTMENT ;
    PORT
      LAYER M3 ;
      RECT 38.223 214.219 38.241 214.273 ;
    END
  END r0_rd_out[322]
  PIN r0_rd_out[323]
    DIRECTION OUTPUT ;
    USE SIGNAL ;
    SHAPE ABUTMENT ;
    PORT
      LAYER M3 ;
      RECT 38.799 214.219 38.817 214.273 ;
    END
  END r0_rd_out[323]
  PIN r0_rd_out[324]
    DIRECTION OUTPUT ;
    USE SIGNAL ;
    SHAPE ABUTMENT ;
    PORT
      LAYER M3 ;
      RECT 39.375 214.219 39.393 214.273 ;
    END
  END r0_rd_out[324]
  PIN r0_rd_out[325]
    DIRECTION OUTPUT ;
    USE SIGNAL ;
    SHAPE ABUTMENT ;
    PORT
      LAYER M3 ;
      RECT 39.951 214.219 39.969 214.273 ;
    END
  END r0_rd_out[325]
  PIN r0_rd_out[326]
    DIRECTION OUTPUT ;
    USE SIGNAL ;
    SHAPE ABUTMENT ;
    PORT
      LAYER M3 ;
      RECT 40.527 214.219 40.545 214.273 ;
    END
  END r0_rd_out[326]
  PIN r0_rd_out[327]
    DIRECTION OUTPUT ;
    USE SIGNAL ;
    SHAPE ABUTMENT ;
    PORT
      LAYER M3 ;
      RECT 41.103 214.219 41.121 214.273 ;
    END
  END r0_rd_out[327]
  PIN r0_rd_out[328]
    DIRECTION OUTPUT ;
    USE SIGNAL ;
    SHAPE ABUTMENT ;
    PORT
      LAYER M3 ;
      RECT 41.679 214.219 41.697 214.273 ;
    END
  END r0_rd_out[328]
  PIN r0_rd_out[329]
    DIRECTION OUTPUT ;
    USE SIGNAL ;
    SHAPE ABUTMENT ;
    PORT
      LAYER M3 ;
      RECT 42.255 214.219 42.273 214.273 ;
    END
  END r0_rd_out[329]
  PIN r0_rd_out[330]
    DIRECTION OUTPUT ;
    USE SIGNAL ;
    SHAPE ABUTMENT ;
    PORT
      LAYER M3 ;
      RECT 42.831 214.219 42.849 214.273 ;
    END
  END r0_rd_out[330]
  PIN r0_rd_out[331]
    DIRECTION OUTPUT ;
    USE SIGNAL ;
    SHAPE ABUTMENT ;
    PORT
      LAYER M3 ;
      RECT 43.407 214.219 43.425 214.273 ;
    END
  END r0_rd_out[331]
  PIN r0_rd_out[332]
    DIRECTION OUTPUT ;
    USE SIGNAL ;
    SHAPE ABUTMENT ;
    PORT
      LAYER M3 ;
      RECT 43.983 214.219 44.001 214.273 ;
    END
  END r0_rd_out[332]
  PIN r0_rd_out[333]
    DIRECTION OUTPUT ;
    USE SIGNAL ;
    SHAPE ABUTMENT ;
    PORT
      LAYER M3 ;
      RECT 44.559 214.219 44.577 214.273 ;
    END
  END r0_rd_out[333]
  PIN r0_rd_out[334]
    DIRECTION OUTPUT ;
    USE SIGNAL ;
    SHAPE ABUTMENT ;
    PORT
      LAYER M3 ;
      RECT 45.135 214.219 45.153 214.273 ;
    END
  END r0_rd_out[334]
  PIN r0_rd_out[335]
    DIRECTION OUTPUT ;
    USE SIGNAL ;
    SHAPE ABUTMENT ;
    PORT
      LAYER M3 ;
      RECT 45.711 214.219 45.729 214.273 ;
    END
  END r0_rd_out[335]
  PIN r0_rd_out[336]
    DIRECTION OUTPUT ;
    USE SIGNAL ;
    SHAPE ABUTMENT ;
    PORT
      LAYER M3 ;
      RECT 46.287 214.219 46.305 214.273 ;
    END
  END r0_rd_out[336]
  PIN r0_rd_out[337]
    DIRECTION OUTPUT ;
    USE SIGNAL ;
    SHAPE ABUTMENT ;
    PORT
      LAYER M3 ;
      RECT 46.863 214.219 46.881 214.273 ;
    END
  END r0_rd_out[337]
  PIN r0_rd_out[338]
    DIRECTION OUTPUT ;
    USE SIGNAL ;
    SHAPE ABUTMENT ;
    PORT
      LAYER M3 ;
      RECT 47.439 214.219 47.457 214.273 ;
    END
  END r0_rd_out[338]
  PIN r0_rd_out[339]
    DIRECTION OUTPUT ;
    USE SIGNAL ;
    SHAPE ABUTMENT ;
    PORT
      LAYER M3 ;
      RECT 48.015 214.219 48.033 214.273 ;
    END
  END r0_rd_out[339]
  PIN r0_rd_out[340]
    DIRECTION OUTPUT ;
    USE SIGNAL ;
    SHAPE ABUTMENT ;
    PORT
      LAYER M3 ;
      RECT 48.591 214.219 48.609 214.273 ;
    END
  END r0_rd_out[340]
  PIN r0_rd_out[341]
    DIRECTION OUTPUT ;
    USE SIGNAL ;
    SHAPE ABUTMENT ;
    PORT
      LAYER M3 ;
      RECT 49.167 214.219 49.185 214.273 ;
    END
  END r0_rd_out[341]
  PIN r0_rd_out[342]
    DIRECTION OUTPUT ;
    USE SIGNAL ;
    SHAPE ABUTMENT ;
    PORT
      LAYER M3 ;
      RECT 49.743 214.219 49.761 214.273 ;
    END
  END r0_rd_out[342]
  PIN r0_rd_out[343]
    DIRECTION OUTPUT ;
    USE SIGNAL ;
    SHAPE ABUTMENT ;
    PORT
      LAYER M3 ;
      RECT 50.319 214.219 50.337 214.273 ;
    END
  END r0_rd_out[343]
  PIN r0_rd_out[344]
    DIRECTION OUTPUT ;
    USE SIGNAL ;
    SHAPE ABUTMENT ;
    PORT
      LAYER M3 ;
      RECT 50.895 214.219 50.913 214.273 ;
    END
  END r0_rd_out[344]
  PIN r0_rd_out[345]
    DIRECTION OUTPUT ;
    USE SIGNAL ;
    SHAPE ABUTMENT ;
    PORT
      LAYER M3 ;
      RECT 51.471 214.219 51.489 214.273 ;
    END
  END r0_rd_out[345]
  PIN r0_rd_out[346]
    DIRECTION OUTPUT ;
    USE SIGNAL ;
    SHAPE ABUTMENT ;
    PORT
      LAYER M3 ;
      RECT 52.047 214.219 52.065 214.273 ;
    END
  END r0_rd_out[346]
  PIN r0_rd_out[347]
    DIRECTION OUTPUT ;
    USE SIGNAL ;
    SHAPE ABUTMENT ;
    PORT
      LAYER M3 ;
      RECT 52.623 214.219 52.641 214.273 ;
    END
  END r0_rd_out[347]
  PIN r0_rd_out[348]
    DIRECTION OUTPUT ;
    USE SIGNAL ;
    SHAPE ABUTMENT ;
    PORT
      LAYER M3 ;
      RECT 53.199 214.219 53.217 214.273 ;
    END
  END r0_rd_out[348]
  PIN r0_rd_out[349]
    DIRECTION OUTPUT ;
    USE SIGNAL ;
    SHAPE ABUTMENT ;
    PORT
      LAYER M3 ;
      RECT 53.775 214.219 53.793 214.273 ;
    END
  END r0_rd_out[349]
  PIN r0_rd_out[350]
    DIRECTION OUTPUT ;
    USE SIGNAL ;
    SHAPE ABUTMENT ;
    PORT
      LAYER M3 ;
      RECT 54.351 214.219 54.369 214.273 ;
    END
  END r0_rd_out[350]
  PIN r0_rd_out[351]
    DIRECTION OUTPUT ;
    USE SIGNAL ;
    SHAPE ABUTMENT ;
    PORT
      LAYER M3 ;
      RECT 54.927 214.219 54.945 214.273 ;
    END
  END r0_rd_out[351]
  PIN r0_rd_out[352]
    DIRECTION OUTPUT ;
    USE SIGNAL ;
    SHAPE ABUTMENT ;
    PORT
      LAYER M3 ;
      RECT 55.503 214.219 55.521 214.273 ;
    END
  END r0_rd_out[352]
  PIN r0_rd_out[353]
    DIRECTION OUTPUT ;
    USE SIGNAL ;
    SHAPE ABUTMENT ;
    PORT
      LAYER M3 ;
      RECT 56.079 214.219 56.097 214.273 ;
    END
  END r0_rd_out[353]
  PIN r0_rd_out[354]
    DIRECTION OUTPUT ;
    USE SIGNAL ;
    SHAPE ABUTMENT ;
    PORT
      LAYER M3 ;
      RECT 56.655 214.219 56.673 214.273 ;
    END
  END r0_rd_out[354]
  PIN r0_rd_out[355]
    DIRECTION OUTPUT ;
    USE SIGNAL ;
    SHAPE ABUTMENT ;
    PORT
      LAYER M3 ;
      RECT 57.231 214.219 57.249 214.273 ;
    END
  END r0_rd_out[355]
  PIN r0_rd_out[356]
    DIRECTION OUTPUT ;
    USE SIGNAL ;
    SHAPE ABUTMENT ;
    PORT
      LAYER M3 ;
      RECT 57.807 214.219 57.825 214.273 ;
    END
  END r0_rd_out[356]
  PIN r0_rd_out[357]
    DIRECTION OUTPUT ;
    USE SIGNAL ;
    SHAPE ABUTMENT ;
    PORT
      LAYER M3 ;
      RECT 58.383 214.219 58.401 214.273 ;
    END
  END r0_rd_out[357]
  PIN r0_rd_out[358]
    DIRECTION OUTPUT ;
    USE SIGNAL ;
    SHAPE ABUTMENT ;
    PORT
      LAYER M3 ;
      RECT 58.959 214.219 58.977 214.273 ;
    END
  END r0_rd_out[358]
  PIN r0_rd_out[359]
    DIRECTION OUTPUT ;
    USE SIGNAL ;
    SHAPE ABUTMENT ;
    PORT
      LAYER M3 ;
      RECT 59.535 214.219 59.553 214.273 ;
    END
  END r0_rd_out[359]
  PIN r0_rd_out[360]
    DIRECTION OUTPUT ;
    USE SIGNAL ;
    SHAPE ABUTMENT ;
    PORT
      LAYER M3 ;
      RECT 60.111 214.219 60.129 214.273 ;
    END
  END r0_rd_out[360]
  PIN r0_rd_out[361]
    DIRECTION OUTPUT ;
    USE SIGNAL ;
    SHAPE ABUTMENT ;
    PORT
      LAYER M3 ;
      RECT 60.687 214.219 60.705 214.273 ;
    END
  END r0_rd_out[361]
  PIN r0_rd_out[362]
    DIRECTION OUTPUT ;
    USE SIGNAL ;
    SHAPE ABUTMENT ;
    PORT
      LAYER M3 ;
      RECT 61.263 214.219 61.281 214.273 ;
    END
  END r0_rd_out[362]
  PIN r0_rd_out[363]
    DIRECTION OUTPUT ;
    USE SIGNAL ;
    SHAPE ABUTMENT ;
    PORT
      LAYER M3 ;
      RECT 61.839 214.219 61.857 214.273 ;
    END
  END r0_rd_out[363]
  PIN r0_rd_out[364]
    DIRECTION OUTPUT ;
    USE SIGNAL ;
    SHAPE ABUTMENT ;
    PORT
      LAYER M3 ;
      RECT 62.415 214.219 62.433 214.273 ;
    END
  END r0_rd_out[364]
  PIN r0_rd_out[365]
    DIRECTION OUTPUT ;
    USE SIGNAL ;
    SHAPE ABUTMENT ;
    PORT
      LAYER M3 ;
      RECT 62.991 214.219 63.009 214.273 ;
    END
  END r0_rd_out[365]
  PIN r0_rd_out[366]
    DIRECTION OUTPUT ;
    USE SIGNAL ;
    SHAPE ABUTMENT ;
    PORT
      LAYER M3 ;
      RECT 63.567 214.219 63.585 214.273 ;
    END
  END r0_rd_out[366]
  PIN r0_rd_out[367]
    DIRECTION OUTPUT ;
    USE SIGNAL ;
    SHAPE ABUTMENT ;
    PORT
      LAYER M3 ;
      RECT 64.143 214.219 64.161 214.273 ;
    END
  END r0_rd_out[367]
  PIN r0_rd_out[368]
    DIRECTION OUTPUT ;
    USE SIGNAL ;
    SHAPE ABUTMENT ;
    PORT
      LAYER M3 ;
      RECT 64.719 214.219 64.737 214.273 ;
    END
  END r0_rd_out[368]
  PIN r0_rd_out[369]
    DIRECTION OUTPUT ;
    USE SIGNAL ;
    SHAPE ABUTMENT ;
    PORT
      LAYER M3 ;
      RECT 65.295 214.219 65.313 214.273 ;
    END
  END r0_rd_out[369]
  PIN r0_rd_out[370]
    DIRECTION OUTPUT ;
    USE SIGNAL ;
    SHAPE ABUTMENT ;
    PORT
      LAYER M3 ;
      RECT 65.871 214.219 65.889 214.273 ;
    END
  END r0_rd_out[370]
  PIN r0_rd_out[371]
    DIRECTION OUTPUT ;
    USE SIGNAL ;
    SHAPE ABUTMENT ;
    PORT
      LAYER M3 ;
      RECT 66.447 214.219 66.465 214.273 ;
    END
  END r0_rd_out[371]
  PIN r0_rd_out[372]
    DIRECTION OUTPUT ;
    USE SIGNAL ;
    SHAPE ABUTMENT ;
    PORT
      LAYER M3 ;
      RECT 67.023 214.219 67.041 214.273 ;
    END
  END r0_rd_out[372]
  PIN r0_rd_out[373]
    DIRECTION OUTPUT ;
    USE SIGNAL ;
    SHAPE ABUTMENT ;
    PORT
      LAYER M3 ;
      RECT 67.599 214.219 67.617 214.273 ;
    END
  END r0_rd_out[373]
  PIN r0_rd_out[374]
    DIRECTION OUTPUT ;
    USE SIGNAL ;
    SHAPE ABUTMENT ;
    PORT
      LAYER M3 ;
      RECT 68.175 214.219 68.193 214.273 ;
    END
  END r0_rd_out[374]
  PIN r0_rd_out[375]
    DIRECTION OUTPUT ;
    USE SIGNAL ;
    SHAPE ABUTMENT ;
    PORT
      LAYER M3 ;
      RECT 68.751 214.219 68.769 214.273 ;
    END
  END r0_rd_out[375]
  PIN r0_rd_out[376]
    DIRECTION OUTPUT ;
    USE SIGNAL ;
    SHAPE ABUTMENT ;
    PORT
      LAYER M3 ;
      RECT 69.327 214.219 69.345 214.273 ;
    END
  END r0_rd_out[376]
  PIN r0_rd_out[377]
    DIRECTION OUTPUT ;
    USE SIGNAL ;
    SHAPE ABUTMENT ;
    PORT
      LAYER M3 ;
      RECT 69.903 214.219 69.921 214.273 ;
    END
  END r0_rd_out[377]
  PIN r0_rd_out[378]
    DIRECTION OUTPUT ;
    USE SIGNAL ;
    SHAPE ABUTMENT ;
    PORT
      LAYER M3 ;
      RECT 70.479 214.219 70.497 214.273 ;
    END
  END r0_rd_out[378]
  PIN r0_rd_out[379]
    DIRECTION OUTPUT ;
    USE SIGNAL ;
    SHAPE ABUTMENT ;
    PORT
      LAYER M3 ;
      RECT 71.055 214.219 71.073 214.273 ;
    END
  END r0_rd_out[379]
  PIN r0_rd_out[380]
    DIRECTION OUTPUT ;
    USE SIGNAL ;
    SHAPE ABUTMENT ;
    PORT
      LAYER M3 ;
      RECT 71.631 214.219 71.649 214.273 ;
    END
  END r0_rd_out[380]
  PIN r0_rd_out[381]
    DIRECTION OUTPUT ;
    USE SIGNAL ;
    SHAPE ABUTMENT ;
    PORT
      LAYER M3 ;
      RECT 72.207 214.219 72.225 214.273 ;
    END
  END r0_rd_out[381]
  PIN r0_rd_out[382]
    DIRECTION OUTPUT ;
    USE SIGNAL ;
    SHAPE ABUTMENT ;
    PORT
      LAYER M3 ;
      RECT 72.783 214.219 72.801 214.273 ;
    END
  END r0_rd_out[382]
  PIN r0_rd_out[383]
    DIRECTION OUTPUT ;
    USE SIGNAL ;
    SHAPE ABUTMENT ;
    PORT
      LAYER M3 ;
      RECT 73.359 214.219 73.377 214.273 ;
    END
  END r0_rd_out[383]
  PIN r0_rd_out[384]
    DIRECTION OUTPUT ;
    USE SIGNAL ;
    SHAPE ABUTMENT ;
    PORT
      LAYER M3 ;
      RECT 73.935 214.219 73.953 214.273 ;
    END
  END r0_rd_out[384]
  PIN r0_rd_out[385]
    DIRECTION OUTPUT ;
    USE SIGNAL ;
    SHAPE ABUTMENT ;
    PORT
      LAYER M3 ;
      RECT 74.511 214.219 74.529 214.273 ;
    END
  END r0_rd_out[385]
  PIN r0_rd_out[386]
    DIRECTION OUTPUT ;
    USE SIGNAL ;
    SHAPE ABUTMENT ;
    PORT
      LAYER M3 ;
      RECT 75.087 214.219 75.105 214.273 ;
    END
  END r0_rd_out[386]
  PIN r0_rd_out[387]
    DIRECTION OUTPUT ;
    USE SIGNAL ;
    SHAPE ABUTMENT ;
    PORT
      LAYER M3 ;
      RECT 75.663 214.219 75.681 214.273 ;
    END
  END r0_rd_out[387]
  PIN r0_rd_out[388]
    DIRECTION OUTPUT ;
    USE SIGNAL ;
    SHAPE ABUTMENT ;
    PORT
      LAYER M3 ;
      RECT 76.239 214.219 76.257 214.273 ;
    END
  END r0_rd_out[388]
  PIN r0_rd_out[389]
    DIRECTION OUTPUT ;
    USE SIGNAL ;
    SHAPE ABUTMENT ;
    PORT
      LAYER M3 ;
      RECT 76.815 214.219 76.833 214.273 ;
    END
  END r0_rd_out[389]
  PIN r0_rd_out[390]
    DIRECTION OUTPUT ;
    USE SIGNAL ;
    SHAPE ABUTMENT ;
    PORT
      LAYER M3 ;
      RECT 77.391 214.219 77.409 214.273 ;
    END
  END r0_rd_out[390]
  PIN r0_rd_out[391]
    DIRECTION OUTPUT ;
    USE SIGNAL ;
    SHAPE ABUTMENT ;
    PORT
      LAYER M3 ;
      RECT 77.967 214.219 77.985 214.273 ;
    END
  END r0_rd_out[391]
  PIN r0_rd_out[392]
    DIRECTION OUTPUT ;
    USE SIGNAL ;
    SHAPE ABUTMENT ;
    PORT
      LAYER M3 ;
      RECT 78.543 214.219 78.561 214.273 ;
    END
  END r0_rd_out[392]
  PIN r0_rd_out[393]
    DIRECTION OUTPUT ;
    USE SIGNAL ;
    SHAPE ABUTMENT ;
    PORT
      LAYER M3 ;
      RECT 79.119 214.219 79.137 214.273 ;
    END
  END r0_rd_out[393]
  PIN r0_rd_out[394]
    DIRECTION OUTPUT ;
    USE SIGNAL ;
    SHAPE ABUTMENT ;
    PORT
      LAYER M3 ;
      RECT 79.695 214.219 79.713 214.273 ;
    END
  END r0_rd_out[394]
  PIN r0_rd_out[395]
    DIRECTION OUTPUT ;
    USE SIGNAL ;
    SHAPE ABUTMENT ;
    PORT
      LAYER M3 ;
      RECT 80.271 214.219 80.289 214.273 ;
    END
  END r0_rd_out[395]
  PIN r0_rd_out[396]
    DIRECTION OUTPUT ;
    USE SIGNAL ;
    SHAPE ABUTMENT ;
    PORT
      LAYER M3 ;
      RECT 80.847 214.219 80.865 214.273 ;
    END
  END r0_rd_out[396]
  PIN r0_rd_out[397]
    DIRECTION OUTPUT ;
    USE SIGNAL ;
    SHAPE ABUTMENT ;
    PORT
      LAYER M3 ;
      RECT 81.423 214.219 81.441 214.273 ;
    END
  END r0_rd_out[397]
  PIN r0_rd_out[398]
    DIRECTION OUTPUT ;
    USE SIGNAL ;
    SHAPE ABUTMENT ;
    PORT
      LAYER M3 ;
      RECT 81.999 214.219 82.017 214.273 ;
    END
  END r0_rd_out[398]
  PIN r0_rd_out[399]
    DIRECTION OUTPUT ;
    USE SIGNAL ;
    SHAPE ABUTMENT ;
    PORT
      LAYER M3 ;
      RECT 82.575 214.219 82.593 214.273 ;
    END
  END r0_rd_out[399]
  PIN r0_rd_out[400]
    DIRECTION OUTPUT ;
    USE SIGNAL ;
    SHAPE ABUTMENT ;
    PORT
      LAYER M3 ;
      RECT 83.151 214.219 83.169 214.273 ;
    END
  END r0_rd_out[400]
  PIN r0_rd_out[401]
    DIRECTION OUTPUT ;
    USE SIGNAL ;
    SHAPE ABUTMENT ;
    PORT
      LAYER M3 ;
      RECT 83.727 214.219 83.745 214.273 ;
    END
  END r0_rd_out[401]
  PIN r0_rd_out[402]
    DIRECTION OUTPUT ;
    USE SIGNAL ;
    SHAPE ABUTMENT ;
    PORT
      LAYER M3 ;
      RECT 84.303 214.219 84.321 214.273 ;
    END
  END r0_rd_out[402]
  PIN r0_rd_out[403]
    DIRECTION OUTPUT ;
    USE SIGNAL ;
    SHAPE ABUTMENT ;
    PORT
      LAYER M3 ;
      RECT 84.879 214.219 84.897 214.273 ;
    END
  END r0_rd_out[403]
  PIN r0_rd_out[404]
    DIRECTION OUTPUT ;
    USE SIGNAL ;
    SHAPE ABUTMENT ;
    PORT
      LAYER M3 ;
      RECT 85.455 214.219 85.473 214.273 ;
    END
  END r0_rd_out[404]
  PIN r0_rd_out[405]
    DIRECTION OUTPUT ;
    USE SIGNAL ;
    SHAPE ABUTMENT ;
    PORT
      LAYER M3 ;
      RECT 86.031 214.219 86.049 214.273 ;
    END
  END r0_rd_out[405]
  PIN r0_rd_out[406]
    DIRECTION OUTPUT ;
    USE SIGNAL ;
    SHAPE ABUTMENT ;
    PORT
      LAYER M3 ;
      RECT 86.607 214.219 86.625 214.273 ;
    END
  END r0_rd_out[406]
  PIN r0_rd_out[407]
    DIRECTION OUTPUT ;
    USE SIGNAL ;
    SHAPE ABUTMENT ;
    PORT
      LAYER M3 ;
      RECT 87.183 214.219 87.201 214.273 ;
    END
  END r0_rd_out[407]
  PIN r0_rd_out[408]
    DIRECTION OUTPUT ;
    USE SIGNAL ;
    SHAPE ABUTMENT ;
    PORT
      LAYER M3 ;
      RECT 87.759 214.219 87.777 214.273 ;
    END
  END r0_rd_out[408]
  PIN r0_rd_out[409]
    DIRECTION OUTPUT ;
    USE SIGNAL ;
    SHAPE ABUTMENT ;
    PORT
      LAYER M3 ;
      RECT 88.335 214.219 88.353 214.273 ;
    END
  END r0_rd_out[409]
  PIN r0_rd_out[410]
    DIRECTION OUTPUT ;
    USE SIGNAL ;
    SHAPE ABUTMENT ;
    PORT
      LAYER M3 ;
      RECT 88.911 214.219 88.929 214.273 ;
    END
  END r0_rd_out[410]
  PIN r0_rd_out[411]
    DIRECTION OUTPUT ;
    USE SIGNAL ;
    SHAPE ABUTMENT ;
    PORT
      LAYER M3 ;
      RECT 89.487 214.219 89.505 214.273 ;
    END
  END r0_rd_out[411]
  PIN r0_rd_out[412]
    DIRECTION OUTPUT ;
    USE SIGNAL ;
    SHAPE ABUTMENT ;
    PORT
      LAYER M3 ;
      RECT 90.063 214.219 90.081 214.273 ;
    END
  END r0_rd_out[412]
  PIN r0_rd_out[413]
    DIRECTION OUTPUT ;
    USE SIGNAL ;
    SHAPE ABUTMENT ;
    PORT
      LAYER M3 ;
      RECT 90.639 214.219 90.657 214.273 ;
    END
  END r0_rd_out[413]
  PIN r0_rd_out[414]
    DIRECTION OUTPUT ;
    USE SIGNAL ;
    SHAPE ABUTMENT ;
    PORT
      LAYER M3 ;
      RECT 91.215 214.219 91.233 214.273 ;
    END
  END r0_rd_out[414]
  PIN r0_rd_out[415]
    DIRECTION OUTPUT ;
    USE SIGNAL ;
    SHAPE ABUTMENT ;
    PORT
      LAYER M3 ;
      RECT 91.791 214.219 91.809 214.273 ;
    END
  END r0_rd_out[415]
  PIN r0_rd_out[416]
    DIRECTION OUTPUT ;
    USE SIGNAL ;
    SHAPE ABUTMENT ;
    PORT
      LAYER M3 ;
      RECT 92.367 214.219 92.385 214.273 ;
    END
  END r0_rd_out[416]
  PIN r0_rd_out[417]
    DIRECTION OUTPUT ;
    USE SIGNAL ;
    SHAPE ABUTMENT ;
    PORT
      LAYER M3 ;
      RECT 92.943 214.219 92.961 214.273 ;
    END
  END r0_rd_out[417]
  PIN r0_rd_out[418]
    DIRECTION OUTPUT ;
    USE SIGNAL ;
    SHAPE ABUTMENT ;
    PORT
      LAYER M3 ;
      RECT 93.519 214.219 93.537 214.273 ;
    END
  END r0_rd_out[418]
  PIN r0_rd_out[419]
    DIRECTION OUTPUT ;
    USE SIGNAL ;
    SHAPE ABUTMENT ;
    PORT
      LAYER M3 ;
      RECT 94.095 214.219 94.113 214.273 ;
    END
  END r0_rd_out[419]
  PIN r0_rd_out[420]
    DIRECTION OUTPUT ;
    USE SIGNAL ;
    SHAPE ABUTMENT ;
    PORT
      LAYER M3 ;
      RECT 94.671 214.219 94.689 214.273 ;
    END
  END r0_rd_out[420]
  PIN r0_rd_out[421]
    DIRECTION OUTPUT ;
    USE SIGNAL ;
    SHAPE ABUTMENT ;
    PORT
      LAYER M3 ;
      RECT 95.247 214.219 95.265 214.273 ;
    END
  END r0_rd_out[421]
  PIN r0_rd_out[422]
    DIRECTION OUTPUT ;
    USE SIGNAL ;
    SHAPE ABUTMENT ;
    PORT
      LAYER M3 ;
      RECT 95.823 214.219 95.841 214.273 ;
    END
  END r0_rd_out[422]
  PIN r0_rd_out[423]
    DIRECTION OUTPUT ;
    USE SIGNAL ;
    SHAPE ABUTMENT ;
    PORT
      LAYER M3 ;
      RECT 96.399 214.219 96.417 214.273 ;
    END
  END r0_rd_out[423]
  PIN r0_rd_out[424]
    DIRECTION OUTPUT ;
    USE SIGNAL ;
    SHAPE ABUTMENT ;
    PORT
      LAYER M3 ;
      RECT 96.975 214.219 96.993 214.273 ;
    END
  END r0_rd_out[424]
  PIN r0_rd_out[425]
    DIRECTION OUTPUT ;
    USE SIGNAL ;
    SHAPE ABUTMENT ;
    PORT
      LAYER M3 ;
      RECT 97.551 214.219 97.569 214.273 ;
    END
  END r0_rd_out[425]
  PIN r0_rd_out[426]
    DIRECTION OUTPUT ;
    USE SIGNAL ;
    SHAPE ABUTMENT ;
    PORT
      LAYER M3 ;
      RECT 98.127 214.219 98.145 214.273 ;
    END
  END r0_rd_out[426]
  PIN r0_rd_out[427]
    DIRECTION OUTPUT ;
    USE SIGNAL ;
    SHAPE ABUTMENT ;
    PORT
      LAYER M3 ;
      RECT 98.703 214.219 98.721 214.273 ;
    END
  END r0_rd_out[427]
  PIN r0_rd_out[428]
    DIRECTION OUTPUT ;
    USE SIGNAL ;
    SHAPE ABUTMENT ;
    PORT
      LAYER M3 ;
      RECT 99.279 214.219 99.297 214.273 ;
    END
  END r0_rd_out[428]
  PIN r0_rd_out[429]
    DIRECTION OUTPUT ;
    USE SIGNAL ;
    SHAPE ABUTMENT ;
    PORT
      LAYER M3 ;
      RECT 99.855 214.219 99.873 214.273 ;
    END
  END r0_rd_out[429]
  PIN r0_rd_out[430]
    DIRECTION OUTPUT ;
    USE SIGNAL ;
    SHAPE ABUTMENT ;
    PORT
      LAYER M3 ;
      RECT 100.431 214.219 100.449 214.273 ;
    END
  END r0_rd_out[430]
  PIN r0_rd_out[431]
    DIRECTION OUTPUT ;
    USE SIGNAL ;
    SHAPE ABUTMENT ;
    PORT
      LAYER M3 ;
      RECT 101.007 214.219 101.025 214.273 ;
    END
  END r0_rd_out[431]
  PIN r0_rd_out[432]
    DIRECTION OUTPUT ;
    USE SIGNAL ;
    SHAPE ABUTMENT ;
    PORT
      LAYER M3 ;
      RECT 101.583 214.219 101.601 214.273 ;
    END
  END r0_rd_out[432]
  PIN r0_rd_out[433]
    DIRECTION OUTPUT ;
    USE SIGNAL ;
    SHAPE ABUTMENT ;
    PORT
      LAYER M3 ;
      RECT 102.159 214.219 102.177 214.273 ;
    END
  END r0_rd_out[433]
  PIN r0_rd_out[434]
    DIRECTION OUTPUT ;
    USE SIGNAL ;
    SHAPE ABUTMENT ;
    PORT
      LAYER M3 ;
      RECT 102.735 214.219 102.753 214.273 ;
    END
  END r0_rd_out[434]
  PIN r0_rd_out[435]
    DIRECTION OUTPUT ;
    USE SIGNAL ;
    SHAPE ABUTMENT ;
    PORT
      LAYER M3 ;
      RECT 103.311 214.219 103.329 214.273 ;
    END
  END r0_rd_out[435]
  PIN r0_rd_out[436]
    DIRECTION OUTPUT ;
    USE SIGNAL ;
    SHAPE ABUTMENT ;
    PORT
      LAYER M3 ;
      RECT 103.887 214.219 103.905 214.273 ;
    END
  END r0_rd_out[436]
  PIN r0_rd_out[437]
    DIRECTION OUTPUT ;
    USE SIGNAL ;
    SHAPE ABUTMENT ;
    PORT
      LAYER M3 ;
      RECT 104.463 214.219 104.481 214.273 ;
    END
  END r0_rd_out[437]
  PIN r0_rd_out[438]
    DIRECTION OUTPUT ;
    USE SIGNAL ;
    SHAPE ABUTMENT ;
    PORT
      LAYER M3 ;
      RECT 105.039 214.219 105.057 214.273 ;
    END
  END r0_rd_out[438]
  PIN r0_rd_out[439]
    DIRECTION OUTPUT ;
    USE SIGNAL ;
    SHAPE ABUTMENT ;
    PORT
      LAYER M3 ;
      RECT 105.615 214.219 105.633 214.273 ;
    END
  END r0_rd_out[439]
  PIN r0_rd_out[440]
    DIRECTION OUTPUT ;
    USE SIGNAL ;
    SHAPE ABUTMENT ;
    PORT
      LAYER M3 ;
      RECT 106.191 214.219 106.209 214.273 ;
    END
  END r0_rd_out[440]
  PIN r0_rd_out[441]
    DIRECTION OUTPUT ;
    USE SIGNAL ;
    SHAPE ABUTMENT ;
    PORT
      LAYER M3 ;
      RECT 106.767 214.219 106.785 214.273 ;
    END
  END r0_rd_out[441]
  PIN r0_rd_out[442]
    DIRECTION OUTPUT ;
    USE SIGNAL ;
    SHAPE ABUTMENT ;
    PORT
      LAYER M3 ;
      RECT 107.343 214.219 107.361 214.273 ;
    END
  END r0_rd_out[442]
  PIN r0_rd_out[443]
    DIRECTION OUTPUT ;
    USE SIGNAL ;
    SHAPE ABUTMENT ;
    PORT
      LAYER M3 ;
      RECT 107.919 214.219 107.937 214.273 ;
    END
  END r0_rd_out[443]
  PIN r0_rd_out[444]
    DIRECTION OUTPUT ;
    USE SIGNAL ;
    SHAPE ABUTMENT ;
    PORT
      LAYER M3 ;
      RECT 108.495 214.219 108.513 214.273 ;
    END
  END r0_rd_out[444]
  PIN r0_rd_out[445]
    DIRECTION OUTPUT ;
    USE SIGNAL ;
    SHAPE ABUTMENT ;
    PORT
      LAYER M3 ;
      RECT 109.071 214.219 109.089 214.273 ;
    END
  END r0_rd_out[445]
  PIN r0_rd_out[446]
    DIRECTION OUTPUT ;
    USE SIGNAL ;
    SHAPE ABUTMENT ;
    PORT
      LAYER M3 ;
      RECT 109.647 214.219 109.665 214.273 ;
    END
  END r0_rd_out[446]
  PIN r0_rd_out[447]
    DIRECTION OUTPUT ;
    USE SIGNAL ;
    SHAPE ABUTMENT ;
    PORT
      LAYER M3 ;
      RECT 110.223 214.219 110.241 214.273 ;
    END
  END r0_rd_out[447]
  PIN r0_rd_out[448]
    DIRECTION OUTPUT ;
    USE SIGNAL ;
    SHAPE ABUTMENT ;
    PORT
      LAYER M3 ;
      RECT 110.799 214.219 110.817 214.273 ;
    END
  END r0_rd_out[448]
  PIN r0_rd_out[449]
    DIRECTION OUTPUT ;
    USE SIGNAL ;
    SHAPE ABUTMENT ;
    PORT
      LAYER M3 ;
      RECT 111.375 214.219 111.393 214.273 ;
    END
  END r0_rd_out[449]
  PIN r0_rd_out[450]
    DIRECTION OUTPUT ;
    USE SIGNAL ;
    SHAPE ABUTMENT ;
    PORT
      LAYER M3 ;
      RECT 111.951 214.219 111.969 214.273 ;
    END
  END r0_rd_out[450]
  PIN r0_rd_out[451]
    DIRECTION OUTPUT ;
    USE SIGNAL ;
    SHAPE ABUTMENT ;
    PORT
      LAYER M3 ;
      RECT 112.527 214.219 112.545 214.273 ;
    END
  END r0_rd_out[451]
  PIN r0_rd_out[452]
    DIRECTION OUTPUT ;
    USE SIGNAL ;
    SHAPE ABUTMENT ;
    PORT
      LAYER M3 ;
      RECT 113.103 214.219 113.121 214.273 ;
    END
  END r0_rd_out[452]
  PIN r0_rd_out[453]
    DIRECTION OUTPUT ;
    USE SIGNAL ;
    SHAPE ABUTMENT ;
    PORT
      LAYER M3 ;
      RECT 113.679 214.219 113.697 214.273 ;
    END
  END r0_rd_out[453]
  PIN r0_rd_out[454]
    DIRECTION OUTPUT ;
    USE SIGNAL ;
    SHAPE ABUTMENT ;
    PORT
      LAYER M3 ;
      RECT 114.255 214.219 114.273 214.273 ;
    END
  END r0_rd_out[454]
  PIN r0_rd_out[455]
    DIRECTION OUTPUT ;
    USE SIGNAL ;
    SHAPE ABUTMENT ;
    PORT
      LAYER M3 ;
      RECT 114.831 214.219 114.849 214.273 ;
    END
  END r0_rd_out[455]
  PIN r0_rd_out[456]
    DIRECTION OUTPUT ;
    USE SIGNAL ;
    SHAPE ABUTMENT ;
    PORT
      LAYER M3 ;
      RECT 115.407 214.219 115.425 214.273 ;
    END
  END r0_rd_out[456]
  PIN r0_rd_out[457]
    DIRECTION OUTPUT ;
    USE SIGNAL ;
    SHAPE ABUTMENT ;
    PORT
      LAYER M3 ;
      RECT 115.983 214.219 116.001 214.273 ;
    END
  END r0_rd_out[457]
  PIN r0_rd_out[458]
    DIRECTION OUTPUT ;
    USE SIGNAL ;
    SHAPE ABUTMENT ;
    PORT
      LAYER M3 ;
      RECT 116.559 214.219 116.577 214.273 ;
    END
  END r0_rd_out[458]
  PIN r0_rd_out[459]
    DIRECTION OUTPUT ;
    USE SIGNAL ;
    SHAPE ABUTMENT ;
    PORT
      LAYER M3 ;
      RECT 117.135 214.219 117.153 214.273 ;
    END
  END r0_rd_out[459]
  PIN r0_rd_out[460]
    DIRECTION OUTPUT ;
    USE SIGNAL ;
    SHAPE ABUTMENT ;
    PORT
      LAYER M3 ;
      RECT 117.711 214.219 117.729 214.273 ;
    END
  END r0_rd_out[460]
  PIN r0_rd_out[461]
    DIRECTION OUTPUT ;
    USE SIGNAL ;
    SHAPE ABUTMENT ;
    PORT
      LAYER M3 ;
      RECT 118.287 214.219 118.305 214.273 ;
    END
  END r0_rd_out[461]
  PIN r0_rd_out[462]
    DIRECTION OUTPUT ;
    USE SIGNAL ;
    SHAPE ABUTMENT ;
    PORT
      LAYER M3 ;
      RECT 118.863 214.219 118.881 214.273 ;
    END
  END r0_rd_out[462]
  PIN r0_rd_out[463]
    DIRECTION OUTPUT ;
    USE SIGNAL ;
    SHAPE ABUTMENT ;
    PORT
      LAYER M3 ;
      RECT 119.439 214.219 119.457 214.273 ;
    END
  END r0_rd_out[463]
  PIN r0_rd_out[464]
    DIRECTION OUTPUT ;
    USE SIGNAL ;
    SHAPE ABUTMENT ;
    PORT
      LAYER M3 ;
      RECT 120.015 214.219 120.033 214.273 ;
    END
  END r0_rd_out[464]
  PIN r0_rd_out[465]
    DIRECTION OUTPUT ;
    USE SIGNAL ;
    SHAPE ABUTMENT ;
    PORT
      LAYER M3 ;
      RECT 120.591 214.219 120.609 214.273 ;
    END
  END r0_rd_out[465]
  PIN r0_rd_out[466]
    DIRECTION OUTPUT ;
    USE SIGNAL ;
    SHAPE ABUTMENT ;
    PORT
      LAYER M3 ;
      RECT 121.167 214.219 121.185 214.273 ;
    END
  END r0_rd_out[466]
  PIN r0_rd_out[467]
    DIRECTION OUTPUT ;
    USE SIGNAL ;
    SHAPE ABUTMENT ;
    PORT
      LAYER M3 ;
      RECT 121.743 214.219 121.761 214.273 ;
    END
  END r0_rd_out[467]
  PIN r0_rd_out[468]
    DIRECTION OUTPUT ;
    USE SIGNAL ;
    SHAPE ABUTMENT ;
    PORT
      LAYER M3 ;
      RECT 122.319 214.219 122.337 214.273 ;
    END
  END r0_rd_out[468]
  PIN r0_rd_out[469]
    DIRECTION OUTPUT ;
    USE SIGNAL ;
    SHAPE ABUTMENT ;
    PORT
      LAYER M3 ;
      RECT 122.895 214.219 122.913 214.273 ;
    END
  END r0_rd_out[469]
  PIN r0_rd_out[470]
    DIRECTION OUTPUT ;
    USE SIGNAL ;
    SHAPE ABUTMENT ;
    PORT
      LAYER M3 ;
      RECT 123.471 214.219 123.489 214.273 ;
    END
  END r0_rd_out[470]
  PIN r0_rd_out[471]
    DIRECTION OUTPUT ;
    USE SIGNAL ;
    SHAPE ABUTMENT ;
    PORT
      LAYER M3 ;
      RECT 124.047 214.219 124.065 214.273 ;
    END
  END r0_rd_out[471]
  PIN r0_rd_out[472]
    DIRECTION OUTPUT ;
    USE SIGNAL ;
    SHAPE ABUTMENT ;
    PORT
      LAYER M3 ;
      RECT 124.623 214.219 124.641 214.273 ;
    END
  END r0_rd_out[472]
  PIN r0_rd_out[473]
    DIRECTION OUTPUT ;
    USE SIGNAL ;
    SHAPE ABUTMENT ;
    PORT
      LAYER M3 ;
      RECT 125.199 214.219 125.217 214.273 ;
    END
  END r0_rd_out[473]
  PIN r0_rd_out[474]
    DIRECTION OUTPUT ;
    USE SIGNAL ;
    SHAPE ABUTMENT ;
    PORT
      LAYER M3 ;
      RECT 125.775 214.219 125.793 214.273 ;
    END
  END r0_rd_out[474]
  PIN r0_rd_out[475]
    DIRECTION OUTPUT ;
    USE SIGNAL ;
    SHAPE ABUTMENT ;
    PORT
      LAYER M3 ;
      RECT 126.351 214.219 126.369 214.273 ;
    END
  END r0_rd_out[475]
  PIN r0_rd_out[476]
    DIRECTION OUTPUT ;
    USE SIGNAL ;
    SHAPE ABUTMENT ;
    PORT
      LAYER M3 ;
      RECT 126.927 214.219 126.945 214.273 ;
    END
  END r0_rd_out[476]
  PIN r0_rd_out[477]
    DIRECTION OUTPUT ;
    USE SIGNAL ;
    SHAPE ABUTMENT ;
    PORT
      LAYER M3 ;
      RECT 127.503 214.219 127.521 214.273 ;
    END
  END r0_rd_out[477]
  PIN r0_rd_out[478]
    DIRECTION OUTPUT ;
    USE SIGNAL ;
    SHAPE ABUTMENT ;
    PORT
      LAYER M3 ;
      RECT 128.079 214.219 128.097 214.273 ;
    END
  END r0_rd_out[478]
  PIN r0_rd_out[479]
    DIRECTION OUTPUT ;
    USE SIGNAL ;
    SHAPE ABUTMENT ;
    PORT
      LAYER M3 ;
      RECT 128.655 214.219 128.673 214.273 ;
    END
  END r0_rd_out[479]
  PIN r0_rd_out[480]
    DIRECTION OUTPUT ;
    USE SIGNAL ;
    SHAPE ABUTMENT ;
    PORT
      LAYER M3 ;
      RECT 129.231 214.219 129.249 214.273 ;
    END
  END r0_rd_out[480]
  PIN r0_rd_out[481]
    DIRECTION OUTPUT ;
    USE SIGNAL ;
    SHAPE ABUTMENT ;
    PORT
      LAYER M3 ;
      RECT 129.807 214.219 129.825 214.273 ;
    END
  END r0_rd_out[481]
  PIN r0_rd_out[482]
    DIRECTION OUTPUT ;
    USE SIGNAL ;
    SHAPE ABUTMENT ;
    PORT
      LAYER M3 ;
      RECT 130.383 214.219 130.401 214.273 ;
    END
  END r0_rd_out[482]
  PIN r0_rd_out[483]
    DIRECTION OUTPUT ;
    USE SIGNAL ;
    SHAPE ABUTMENT ;
    PORT
      LAYER M3 ;
      RECT 130.959 214.219 130.977 214.273 ;
    END
  END r0_rd_out[483]
  PIN r0_rd_out[484]
    DIRECTION OUTPUT ;
    USE SIGNAL ;
    SHAPE ABUTMENT ;
    PORT
      LAYER M3 ;
      RECT 131.535 214.219 131.553 214.273 ;
    END
  END r0_rd_out[484]
  PIN r0_rd_out[485]
    DIRECTION OUTPUT ;
    USE SIGNAL ;
    SHAPE ABUTMENT ;
    PORT
      LAYER M3 ;
      RECT 132.111 214.219 132.129 214.273 ;
    END
  END r0_rd_out[485]
  PIN r0_rd_out[486]
    DIRECTION OUTPUT ;
    USE SIGNAL ;
    SHAPE ABUTMENT ;
    PORT
      LAYER M3 ;
      RECT 132.687 214.219 132.705 214.273 ;
    END
  END r0_rd_out[486]
  PIN r0_rd_out[487]
    DIRECTION OUTPUT ;
    USE SIGNAL ;
    SHAPE ABUTMENT ;
    PORT
      LAYER M3 ;
      RECT 133.263 214.219 133.281 214.273 ;
    END
  END r0_rd_out[487]
  PIN r0_rd_out[488]
    DIRECTION OUTPUT ;
    USE SIGNAL ;
    SHAPE ABUTMENT ;
    PORT
      LAYER M3 ;
      RECT 133.839 214.219 133.857 214.273 ;
    END
  END r0_rd_out[488]
  PIN r0_rd_out[489]
    DIRECTION OUTPUT ;
    USE SIGNAL ;
    SHAPE ABUTMENT ;
    PORT
      LAYER M3 ;
      RECT 134.415 214.219 134.433 214.273 ;
    END
  END r0_rd_out[489]
  PIN r0_rd_out[490]
    DIRECTION OUTPUT ;
    USE SIGNAL ;
    SHAPE ABUTMENT ;
    PORT
      LAYER M3 ;
      RECT 134.991 214.219 135.009 214.273 ;
    END
  END r0_rd_out[490]
  PIN r0_rd_out[491]
    DIRECTION OUTPUT ;
    USE SIGNAL ;
    SHAPE ABUTMENT ;
    PORT
      LAYER M3 ;
      RECT 135.567 214.219 135.585 214.273 ;
    END
  END r0_rd_out[491]
  PIN r0_rd_out[492]
    DIRECTION OUTPUT ;
    USE SIGNAL ;
    SHAPE ABUTMENT ;
    PORT
      LAYER M3 ;
      RECT 136.143 214.219 136.161 214.273 ;
    END
  END r0_rd_out[492]
  PIN r0_rd_out[493]
    DIRECTION OUTPUT ;
    USE SIGNAL ;
    SHAPE ABUTMENT ;
    PORT
      LAYER M3 ;
      RECT 136.719 214.219 136.737 214.273 ;
    END
  END r0_rd_out[493]
  PIN r0_rd_out[494]
    DIRECTION OUTPUT ;
    USE SIGNAL ;
    SHAPE ABUTMENT ;
    PORT
      LAYER M3 ;
      RECT 137.295 214.219 137.313 214.273 ;
    END
  END r0_rd_out[494]
  PIN r0_rd_out[495]
    DIRECTION OUTPUT ;
    USE SIGNAL ;
    SHAPE ABUTMENT ;
    PORT
      LAYER M3 ;
      RECT 137.871 214.219 137.889 214.273 ;
    END
  END r0_rd_out[495]
  PIN r0_rd_out[496]
    DIRECTION OUTPUT ;
    USE SIGNAL ;
    SHAPE ABUTMENT ;
    PORT
      LAYER M3 ;
      RECT 138.447 214.219 138.465 214.273 ;
    END
  END r0_rd_out[496]
  PIN r0_rd_out[497]
    DIRECTION OUTPUT ;
    USE SIGNAL ;
    SHAPE ABUTMENT ;
    PORT
      LAYER M3 ;
      RECT 139.023 214.219 139.041 214.273 ;
    END
  END r0_rd_out[497]
  PIN r0_rd_out[498]
    DIRECTION OUTPUT ;
    USE SIGNAL ;
    SHAPE ABUTMENT ;
    PORT
      LAYER M3 ;
      RECT 139.599 214.219 139.617 214.273 ;
    END
  END r0_rd_out[498]
  PIN r0_rd_out[499]
    DIRECTION OUTPUT ;
    USE SIGNAL ;
    SHAPE ABUTMENT ;
    PORT
      LAYER M3 ;
      RECT 140.175 214.219 140.193 214.273 ;
    END
  END r0_rd_out[499]
  PIN r0_rd_out[500]
    DIRECTION OUTPUT ;
    USE SIGNAL ;
    SHAPE ABUTMENT ;
    PORT
      LAYER M3 ;
      RECT 140.751 214.219 140.769 214.273 ;
    END
  END r0_rd_out[500]
  PIN r0_rd_out[501]
    DIRECTION OUTPUT ;
    USE SIGNAL ;
    SHAPE ABUTMENT ;
    PORT
      LAYER M3 ;
      RECT 141.327 214.219 141.345 214.273 ;
    END
  END r0_rd_out[501]
  PIN r0_rd_out[502]
    DIRECTION OUTPUT ;
    USE SIGNAL ;
    SHAPE ABUTMENT ;
    PORT
      LAYER M3 ;
      RECT 141.903 214.219 141.921 214.273 ;
    END
  END r0_rd_out[502]
  PIN r0_rd_out[503]
    DIRECTION OUTPUT ;
    USE SIGNAL ;
    SHAPE ABUTMENT ;
    PORT
      LAYER M3 ;
      RECT 142.479 214.219 142.497 214.273 ;
    END
  END r0_rd_out[503]
  PIN r0_rd_out[504]
    DIRECTION OUTPUT ;
    USE SIGNAL ;
    SHAPE ABUTMENT ;
    PORT
      LAYER M3 ;
      RECT 143.055 214.219 143.073 214.273 ;
    END
  END r0_rd_out[504]
  PIN r0_rd_out[505]
    DIRECTION OUTPUT ;
    USE SIGNAL ;
    SHAPE ABUTMENT ;
    PORT
      LAYER M3 ;
      RECT 143.631 214.219 143.649 214.273 ;
    END
  END r0_rd_out[505]
  PIN r0_rd_out[506]
    DIRECTION OUTPUT ;
    USE SIGNAL ;
    SHAPE ABUTMENT ;
    PORT
      LAYER M3 ;
      RECT 144.207 214.219 144.225 214.273 ;
    END
  END r0_rd_out[506]
  PIN r0_rd_out[507]
    DIRECTION OUTPUT ;
    USE SIGNAL ;
    SHAPE ABUTMENT ;
    PORT
      LAYER M3 ;
      RECT 144.783 214.219 144.801 214.273 ;
    END
  END r0_rd_out[507]
  PIN r0_rd_out[508]
    DIRECTION OUTPUT ;
    USE SIGNAL ;
    SHAPE ABUTMENT ;
    PORT
      LAYER M3 ;
      RECT 145.359 214.219 145.377 214.273 ;
    END
  END r0_rd_out[508]
  PIN r0_rd_out[509]
    DIRECTION OUTPUT ;
    USE SIGNAL ;
    SHAPE ABUTMENT ;
    PORT
      LAYER M3 ;
      RECT 145.935 214.219 145.953 214.273 ;
    END
  END r0_rd_out[509]
  PIN r0_rd_out[510]
    DIRECTION OUTPUT ;
    USE SIGNAL ;
    SHAPE ABUTMENT ;
    PORT
      LAYER M3 ;
      RECT 146.511 214.219 146.529 214.273 ;
    END
  END r0_rd_out[510]
  PIN r0_rd_out[511]
    DIRECTION OUTPUT ;
    USE SIGNAL ;
    SHAPE ABUTMENT ;
    PORT
      LAYER M3 ;
      RECT 147.087 214.219 147.105 214.273 ;
    END
  END r0_rd_out[511]
  PIN w0_addr_in[0]
    DIRECTION INPUT ;
    USE SIGNAL ;
    SHAPE ABUTMENT ;
    PORT
      LAYER M4 ;
      RECT 0.000 196.884 0.072 196.908 ;
    END
  END w0_addr_in[0]
  PIN w0_addr_in[1]
    DIRECTION INPUT ;
    USE SIGNAL ;
    SHAPE ABUTMENT ;
    PORT
      LAYER M4 ;
      RECT 0.000 198.420 0.072 198.444 ;
    END
  END w0_addr_in[1]
  PIN w0_addr_in[2]
    DIRECTION INPUT ;
    USE SIGNAL ;
    SHAPE ABUTMENT ;
    PORT
      LAYER M4 ;
      RECT 0.000 199.956 0.072 199.980 ;
    END
  END w0_addr_in[2]
  PIN w0_addr_in[3]
    DIRECTION INPUT ;
    USE SIGNAL ;
    SHAPE ABUTMENT ;
    PORT
      LAYER M4 ;
      RECT 0.000 201.492 0.072 201.516 ;
    END
  END w0_addr_in[3]
  PIN w0_addr_in[4]
    DIRECTION INPUT ;
    USE SIGNAL ;
    SHAPE ABUTMENT ;
    PORT
      LAYER M4 ;
      RECT 0.000 203.028 0.072 203.052 ;
    END
  END w0_addr_in[4]
  PIN w0_addr_in[5]
    DIRECTION INPUT ;
    USE SIGNAL ;
    SHAPE ABUTMENT ;
    PORT
      LAYER M4 ;
      RECT 154.204 196.884 154.276 196.908 ;
    END
  END w0_addr_in[5]
  PIN w0_addr_in[6]
    DIRECTION INPUT ;
    USE SIGNAL ;
    SHAPE ABUTMENT ;
    PORT
      LAYER M4 ;
      RECT 154.204 198.420 154.276 198.444 ;
    END
  END w0_addr_in[6]
  PIN w0_addr_in[7]
    DIRECTION INPUT ;
    USE SIGNAL ;
    SHAPE ABUTMENT ;
    PORT
      LAYER M4 ;
      RECT 154.204 199.956 154.276 199.980 ;
    END
  END w0_addr_in[7]
  PIN w0_addr_in[8]
    DIRECTION INPUT ;
    USE SIGNAL ;
    SHAPE ABUTMENT ;
    PORT
      LAYER M4 ;
      RECT 154.204 201.492 154.276 201.516 ;
    END
  END w0_addr_in[8]
  PIN w0_addr_in[9]
    DIRECTION INPUT ;
    USE SIGNAL ;
    SHAPE ABUTMENT ;
    PORT
      LAYER M4 ;
      RECT 154.204 203.028 154.276 203.052 ;
    END
  END w0_addr_in[9]
  PIN r0_addr_in[0]
    DIRECTION INPUT ;
    USE SIGNAL ;
    SHAPE ABUTMENT ;
    PORT
      LAYER M4 ;
      RECT 0.000 204.564 0.072 204.588 ;
    END
  END r0_addr_in[0]
  PIN r0_addr_in[1]
    DIRECTION INPUT ;
    USE SIGNAL ;
    SHAPE ABUTMENT ;
    PORT
      LAYER M4 ;
      RECT 0.000 206.100 0.072 206.124 ;
    END
  END r0_addr_in[1]
  PIN r0_addr_in[2]
    DIRECTION INPUT ;
    USE SIGNAL ;
    SHAPE ABUTMENT ;
    PORT
      LAYER M4 ;
      RECT 0.000 207.636 0.072 207.660 ;
    END
  END r0_addr_in[2]
  PIN r0_addr_in[3]
    DIRECTION INPUT ;
    USE SIGNAL ;
    SHAPE ABUTMENT ;
    PORT
      LAYER M4 ;
      RECT 0.000 209.172 0.072 209.196 ;
    END
  END r0_addr_in[3]
  PIN r0_addr_in[4]
    DIRECTION INPUT ;
    USE SIGNAL ;
    SHAPE ABUTMENT ;
    PORT
      LAYER M4 ;
      RECT 0.000 210.708 0.072 210.732 ;
    END
  END r0_addr_in[4]
  PIN r0_addr_in[5]
    DIRECTION INPUT ;
    USE SIGNAL ;
    SHAPE ABUTMENT ;
    PORT
      LAYER M4 ;
      RECT 154.204 204.564 154.276 204.588 ;
    END
  END r0_addr_in[5]
  PIN r0_addr_in[6]
    DIRECTION INPUT ;
    USE SIGNAL ;
    SHAPE ABUTMENT ;
    PORT
      LAYER M4 ;
      RECT 154.204 206.100 154.276 206.124 ;
    END
  END r0_addr_in[6]
  PIN r0_addr_in[7]
    DIRECTION INPUT ;
    USE SIGNAL ;
    SHAPE ABUTMENT ;
    PORT
      LAYER M4 ;
      RECT 154.204 207.636 154.276 207.660 ;
    END
  END r0_addr_in[7]
  PIN r0_addr_in[8]
    DIRECTION INPUT ;
    USE SIGNAL ;
    SHAPE ABUTMENT ;
    PORT
      LAYER M4 ;
      RECT 154.204 209.172 154.276 209.196 ;
    END
  END r0_addr_in[8]
  PIN r0_addr_in[9]
    DIRECTION INPUT ;
    USE SIGNAL ;
    SHAPE ABUTMENT ;
    PORT
      LAYER M4 ;
      RECT 154.204 210.708 154.276 210.732 ;
    END
  END r0_addr_in[9]
  PIN w0_we_in
    DIRECTION INPUT ;
    USE SIGNAL ;
    SHAPE ABUTMENT ;
    PORT
      LAYER M3 ;
      RECT 147.663 214.219 147.681 214.273 ;
    END
  END w0_we_in
  PIN w0_ce_in
    DIRECTION INPUT ;
    USE SIGNAL ;
    SHAPE ABUTMENT ;
    PORT
      LAYER M3 ;
      RECT 148.239 214.219 148.257 214.273 ;
    END
  END w0_ce_in
  PIN w0_clk
    DIRECTION INPUT ;
    USE SIGNAL ;
    SHAPE ABUTMENT ;
    PORT
      LAYER M3 ;
      RECT 148.815 214.219 148.833 214.273 ;
    END
  END w0_clk
  PIN r0_ce_in
    DIRECTION INPUT ;
    USE SIGNAL ;
    SHAPE ABUTMENT ;
    PORT
      LAYER M3 ;
      RECT 149.391 214.219 149.409 214.273 ;
    END
  END r0_ce_in
  PIN r0_clk
    DIRECTION INPUT ;
    USE SIGNAL ;
    SHAPE ABUTMENT ;
    PORT
      LAYER M3 ;
      RECT 149.967 214.219 149.985 214.273 ;
    END
  END r0_clk
  PIN VSS
    DIRECTION INOUT ;
    USE GROUND ;
    PORT
      LAYER M4 ;
      RECT 0.216 0.240 154.060 0.336 ;
      RECT 0.216 1.008 154.060 1.104 ;
      RECT 0.216 1.776 154.060 1.872 ;
      RECT 0.216 2.544 154.060 2.640 ;
      RECT 0.216 3.312 154.060 3.408 ;
      RECT 0.216 4.080 154.060 4.176 ;
      RECT 0.216 4.848 154.060 4.944 ;
      RECT 0.216 5.616 154.060 5.712 ;
      RECT 0.216 6.384 154.060 6.480 ;
      RECT 0.216 7.152 154.060 7.248 ;
      RECT 0.216 7.920 154.060 8.016 ;
      RECT 0.216 8.688 154.060 8.784 ;
      RECT 0.216 9.456 154.060 9.552 ;
      RECT 0.216 10.224 154.060 10.320 ;
      RECT 0.216 10.992 154.060 11.088 ;
      RECT 0.216 11.760 154.060 11.856 ;
      RECT 0.216 12.528 154.060 12.624 ;
      RECT 0.216 13.296 154.060 13.392 ;
      RECT 0.216 14.064 154.060 14.160 ;
      RECT 0.216 14.832 154.060 14.928 ;
      RECT 0.216 15.600 154.060 15.696 ;
      RECT 0.216 16.368 154.060 16.464 ;
      RECT 0.216 17.136 154.060 17.232 ;
      RECT 0.216 17.904 154.060 18.000 ;
      RECT 0.216 18.672 154.060 18.768 ;
      RECT 0.216 19.440 154.060 19.536 ;
      RECT 0.216 20.208 154.060 20.304 ;
      RECT 0.216 20.976 154.060 21.072 ;
      RECT 0.216 21.744 154.060 21.840 ;
      RECT 0.216 22.512 154.060 22.608 ;
      RECT 0.216 23.280 154.060 23.376 ;
      RECT 0.216 24.048 154.060 24.144 ;
      RECT 0.216 24.816 154.060 24.912 ;
      RECT 0.216 25.584 154.060 25.680 ;
      RECT 0.216 26.352 154.060 26.448 ;
      RECT 0.216 27.120 154.060 27.216 ;
      RECT 0.216 27.888 154.060 27.984 ;
      RECT 0.216 28.656 154.060 28.752 ;
      RECT 0.216 29.424 154.060 29.520 ;
      RECT 0.216 30.192 154.060 30.288 ;
      RECT 0.216 30.960 154.060 31.056 ;
      RECT 0.216 31.728 154.060 31.824 ;
      RECT 0.216 32.496 154.060 32.592 ;
      RECT 0.216 33.264 154.060 33.360 ;
      RECT 0.216 34.032 154.060 34.128 ;
      RECT 0.216 34.800 154.060 34.896 ;
      RECT 0.216 35.568 154.060 35.664 ;
      RECT 0.216 36.336 154.060 36.432 ;
      RECT 0.216 37.104 154.060 37.200 ;
      RECT 0.216 37.872 154.060 37.968 ;
      RECT 0.216 38.640 154.060 38.736 ;
      RECT 0.216 39.408 154.060 39.504 ;
      RECT 0.216 40.176 154.060 40.272 ;
      RECT 0.216 40.944 154.060 41.040 ;
      RECT 0.216 41.712 154.060 41.808 ;
      RECT 0.216 42.480 154.060 42.576 ;
      RECT 0.216 43.248 154.060 43.344 ;
      RECT 0.216 44.016 154.060 44.112 ;
      RECT 0.216 44.784 154.060 44.880 ;
      RECT 0.216 45.552 154.060 45.648 ;
      RECT 0.216 46.320 154.060 46.416 ;
      RECT 0.216 47.088 154.060 47.184 ;
      RECT 0.216 47.856 154.060 47.952 ;
      RECT 0.216 48.624 154.060 48.720 ;
      RECT 0.216 49.392 154.060 49.488 ;
      RECT 0.216 50.160 154.060 50.256 ;
      RECT 0.216 50.928 154.060 51.024 ;
      RECT 0.216 51.696 154.060 51.792 ;
      RECT 0.216 52.464 154.060 52.560 ;
      RECT 0.216 53.232 154.060 53.328 ;
      RECT 0.216 54.000 154.060 54.096 ;
      RECT 0.216 54.768 154.060 54.864 ;
      RECT 0.216 55.536 154.060 55.632 ;
      RECT 0.216 56.304 154.060 56.400 ;
      RECT 0.216 57.072 154.060 57.168 ;
      RECT 0.216 57.840 154.060 57.936 ;
      RECT 0.216 58.608 154.060 58.704 ;
      RECT 0.216 59.376 154.060 59.472 ;
      RECT 0.216 60.144 154.060 60.240 ;
      RECT 0.216 60.912 154.060 61.008 ;
      RECT 0.216 61.680 154.060 61.776 ;
      RECT 0.216 62.448 154.060 62.544 ;
      RECT 0.216 63.216 154.060 63.312 ;
      RECT 0.216 63.984 154.060 64.080 ;
      RECT 0.216 64.752 154.060 64.848 ;
      RECT 0.216 65.520 154.060 65.616 ;
      RECT 0.216 66.288 154.060 66.384 ;
      RECT 0.216 67.056 154.060 67.152 ;
      RECT 0.216 67.824 154.060 67.920 ;
      RECT 0.216 68.592 154.060 68.688 ;
      RECT 0.216 69.360 154.060 69.456 ;
      RECT 0.216 70.128 154.060 70.224 ;
      RECT 0.216 70.896 154.060 70.992 ;
      RECT 0.216 71.664 154.060 71.760 ;
      RECT 0.216 72.432 154.060 72.528 ;
      RECT 0.216 73.200 154.060 73.296 ;
      RECT 0.216 73.968 154.060 74.064 ;
      RECT 0.216 74.736 154.060 74.832 ;
      RECT 0.216 75.504 154.060 75.600 ;
      RECT 0.216 76.272 154.060 76.368 ;
      RECT 0.216 77.040 154.060 77.136 ;
      RECT 0.216 77.808 154.060 77.904 ;
      RECT 0.216 78.576 154.060 78.672 ;
      RECT 0.216 79.344 154.060 79.440 ;
      RECT 0.216 80.112 154.060 80.208 ;
      RECT 0.216 80.880 154.060 80.976 ;
      RECT 0.216 81.648 154.060 81.744 ;
      RECT 0.216 82.416 154.060 82.512 ;
      RECT 0.216 83.184 154.060 83.280 ;
      RECT 0.216 83.952 154.060 84.048 ;
      RECT 0.216 84.720 154.060 84.816 ;
      RECT 0.216 85.488 154.060 85.584 ;
      RECT 0.216 86.256 154.060 86.352 ;
      RECT 0.216 87.024 154.060 87.120 ;
      RECT 0.216 87.792 154.060 87.888 ;
      RECT 0.216 88.560 154.060 88.656 ;
      RECT 0.216 89.328 154.060 89.424 ;
      RECT 0.216 90.096 154.060 90.192 ;
      RECT 0.216 90.864 154.060 90.960 ;
      RECT 0.216 91.632 154.060 91.728 ;
      RECT 0.216 92.400 154.060 92.496 ;
      RECT 0.216 93.168 154.060 93.264 ;
      RECT 0.216 93.936 154.060 94.032 ;
      RECT 0.216 94.704 154.060 94.800 ;
      RECT 0.216 95.472 154.060 95.568 ;
      RECT 0.216 96.240 154.060 96.336 ;
      RECT 0.216 97.008 154.060 97.104 ;
      RECT 0.216 97.776 154.060 97.872 ;
      RECT 0.216 98.544 154.060 98.640 ;
      RECT 0.216 99.312 154.060 99.408 ;
      RECT 0.216 100.080 154.060 100.176 ;
      RECT 0.216 100.848 154.060 100.944 ;
      RECT 0.216 101.616 154.060 101.712 ;
      RECT 0.216 102.384 154.060 102.480 ;
      RECT 0.216 103.152 154.060 103.248 ;
      RECT 0.216 103.920 154.060 104.016 ;
      RECT 0.216 104.688 154.060 104.784 ;
      RECT 0.216 105.456 154.060 105.552 ;
      RECT 0.216 106.224 154.060 106.320 ;
      RECT 0.216 106.992 154.060 107.088 ;
      RECT 0.216 107.760 154.060 107.856 ;
      RECT 0.216 108.528 154.060 108.624 ;
      RECT 0.216 109.296 154.060 109.392 ;
      RECT 0.216 110.064 154.060 110.160 ;
      RECT 0.216 110.832 154.060 110.928 ;
      RECT 0.216 111.600 154.060 111.696 ;
      RECT 0.216 112.368 154.060 112.464 ;
      RECT 0.216 113.136 154.060 113.232 ;
      RECT 0.216 113.904 154.060 114.000 ;
      RECT 0.216 114.672 154.060 114.768 ;
      RECT 0.216 115.440 154.060 115.536 ;
      RECT 0.216 116.208 154.060 116.304 ;
      RECT 0.216 116.976 154.060 117.072 ;
      RECT 0.216 117.744 154.060 117.840 ;
      RECT 0.216 118.512 154.060 118.608 ;
      RECT 0.216 119.280 154.060 119.376 ;
      RECT 0.216 120.048 154.060 120.144 ;
      RECT 0.216 120.816 154.060 120.912 ;
      RECT 0.216 121.584 154.060 121.680 ;
      RECT 0.216 122.352 154.060 122.448 ;
      RECT 0.216 123.120 154.060 123.216 ;
      RECT 0.216 123.888 154.060 123.984 ;
      RECT 0.216 124.656 154.060 124.752 ;
      RECT 0.216 125.424 154.060 125.520 ;
      RECT 0.216 126.192 154.060 126.288 ;
      RECT 0.216 126.960 154.060 127.056 ;
      RECT 0.216 127.728 154.060 127.824 ;
      RECT 0.216 128.496 154.060 128.592 ;
      RECT 0.216 129.264 154.060 129.360 ;
      RECT 0.216 130.032 154.060 130.128 ;
      RECT 0.216 130.800 154.060 130.896 ;
      RECT 0.216 131.568 154.060 131.664 ;
      RECT 0.216 132.336 154.060 132.432 ;
      RECT 0.216 133.104 154.060 133.200 ;
      RECT 0.216 133.872 154.060 133.968 ;
      RECT 0.216 134.640 154.060 134.736 ;
      RECT 0.216 135.408 154.060 135.504 ;
      RECT 0.216 136.176 154.060 136.272 ;
      RECT 0.216 136.944 154.060 137.040 ;
      RECT 0.216 137.712 154.060 137.808 ;
      RECT 0.216 138.480 154.060 138.576 ;
      RECT 0.216 139.248 154.060 139.344 ;
      RECT 0.216 140.016 154.060 140.112 ;
      RECT 0.216 140.784 154.060 140.880 ;
      RECT 0.216 141.552 154.060 141.648 ;
      RECT 0.216 142.320 154.060 142.416 ;
      RECT 0.216 143.088 154.060 143.184 ;
      RECT 0.216 143.856 154.060 143.952 ;
      RECT 0.216 144.624 154.060 144.720 ;
      RECT 0.216 145.392 154.060 145.488 ;
      RECT 0.216 146.160 154.060 146.256 ;
      RECT 0.216 146.928 154.060 147.024 ;
      RECT 0.216 147.696 154.060 147.792 ;
      RECT 0.216 148.464 154.060 148.560 ;
      RECT 0.216 149.232 154.060 149.328 ;
      RECT 0.216 150.000 154.060 150.096 ;
      RECT 0.216 150.768 154.060 150.864 ;
      RECT 0.216 151.536 154.060 151.632 ;
      RECT 0.216 152.304 154.060 152.400 ;
      RECT 0.216 153.072 154.060 153.168 ;
      RECT 0.216 153.840 154.060 153.936 ;
      RECT 0.216 154.608 154.060 154.704 ;
      RECT 0.216 155.376 154.060 155.472 ;
      RECT 0.216 156.144 154.060 156.240 ;
      RECT 0.216 156.912 154.060 157.008 ;
      RECT 0.216 157.680 154.060 157.776 ;
      RECT 0.216 158.448 154.060 158.544 ;
      RECT 0.216 159.216 154.060 159.312 ;
      RECT 0.216 159.984 154.060 160.080 ;
      RECT 0.216 160.752 154.060 160.848 ;
      RECT 0.216 161.520 154.060 161.616 ;
      RECT 0.216 162.288 154.060 162.384 ;
      RECT 0.216 163.056 154.060 163.152 ;
      RECT 0.216 163.824 154.060 163.920 ;
      RECT 0.216 164.592 154.060 164.688 ;
      RECT 0.216 165.360 154.060 165.456 ;
      RECT 0.216 166.128 154.060 166.224 ;
      RECT 0.216 166.896 154.060 166.992 ;
      RECT 0.216 167.664 154.060 167.760 ;
      RECT 0.216 168.432 154.060 168.528 ;
      RECT 0.216 169.200 154.060 169.296 ;
      RECT 0.216 169.968 154.060 170.064 ;
      RECT 0.216 170.736 154.060 170.832 ;
      RECT 0.216 171.504 154.060 171.600 ;
      RECT 0.216 172.272 154.060 172.368 ;
      RECT 0.216 173.040 154.060 173.136 ;
      RECT 0.216 173.808 154.060 173.904 ;
      RECT 0.216 174.576 154.060 174.672 ;
      RECT 0.216 175.344 154.060 175.440 ;
      RECT 0.216 176.112 154.060 176.208 ;
      RECT 0.216 176.880 154.060 176.976 ;
      RECT 0.216 177.648 154.060 177.744 ;
      RECT 0.216 178.416 154.060 178.512 ;
      RECT 0.216 179.184 154.060 179.280 ;
      RECT 0.216 179.952 154.060 180.048 ;
      RECT 0.216 180.720 154.060 180.816 ;
      RECT 0.216 181.488 154.060 181.584 ;
      RECT 0.216 182.256 154.060 182.352 ;
      RECT 0.216 183.024 154.060 183.120 ;
      RECT 0.216 183.792 154.060 183.888 ;
      RECT 0.216 184.560 154.060 184.656 ;
      RECT 0.216 185.328 154.060 185.424 ;
      RECT 0.216 186.096 154.060 186.192 ;
      RECT 0.216 186.864 154.060 186.960 ;
      RECT 0.216 187.632 154.060 187.728 ;
      RECT 0.216 188.400 154.060 188.496 ;
      RECT 0.216 189.168 154.060 189.264 ;
      RECT 0.216 189.936 154.060 190.032 ;
      RECT 0.216 190.704 154.060 190.800 ;
      RECT 0.216 191.472 154.060 191.568 ;
      RECT 0.216 192.240 154.060 192.336 ;
      RECT 0.216 193.008 154.060 193.104 ;
      RECT 0.216 193.776 154.060 193.872 ;
      RECT 0.216 194.544 154.060 194.640 ;
      RECT 0.216 195.312 154.060 195.408 ;
      RECT 0.216 196.080 154.060 196.176 ;
      RECT 0.216 196.848 154.060 196.944 ;
      RECT 0.216 197.616 154.060 197.712 ;
      RECT 0.216 198.384 154.060 198.480 ;
      RECT 0.216 199.152 154.060 199.248 ;
      RECT 0.216 199.920 154.060 200.016 ;
      RECT 0.216 200.688 154.060 200.784 ;
      RECT 0.216 201.456 154.060 201.552 ;
      RECT 0.216 202.224 154.060 202.320 ;
      RECT 0.216 202.992 154.060 203.088 ;
      RECT 0.216 203.760 154.060 203.856 ;
      RECT 0.216 204.528 154.060 204.624 ;
      RECT 0.216 205.296 154.060 205.392 ;
      RECT 0.216 206.064 154.060 206.160 ;
      RECT 0.216 206.832 154.060 206.928 ;
      RECT 0.216 207.600 154.060 207.696 ;
      RECT 0.216 208.368 154.060 208.464 ;
      RECT 0.216 209.136 154.060 209.232 ;
      RECT 0.216 209.904 154.060 210.000 ;
      RECT 0.216 210.672 154.060 210.768 ;
      RECT 0.216 211.440 154.060 211.536 ;
      RECT 0.216 212.208 154.060 212.304 ;
      RECT 0.216 212.976 154.060 213.072 ;
      RECT 0.216 213.744 154.060 213.840 ;
    END
  END VSS
  PIN VDD
    DIRECTION INOUT ;
    USE POWER ;
    PORT
      LAYER M4 ;
      RECT 0.216 0.240 154.060 0.336 ;
      RECT 0.216 1.008 154.060 1.104 ;
      RECT 0.216 1.776 154.060 1.872 ;
      RECT 0.216 2.544 154.060 2.640 ;
      RECT 0.216 3.312 154.060 3.408 ;
      RECT 0.216 4.080 154.060 4.176 ;
      RECT 0.216 4.848 154.060 4.944 ;
      RECT 0.216 5.616 154.060 5.712 ;
      RECT 0.216 6.384 154.060 6.480 ;
      RECT 0.216 7.152 154.060 7.248 ;
      RECT 0.216 7.920 154.060 8.016 ;
      RECT 0.216 8.688 154.060 8.784 ;
      RECT 0.216 9.456 154.060 9.552 ;
      RECT 0.216 10.224 154.060 10.320 ;
      RECT 0.216 10.992 154.060 11.088 ;
      RECT 0.216 11.760 154.060 11.856 ;
      RECT 0.216 12.528 154.060 12.624 ;
      RECT 0.216 13.296 154.060 13.392 ;
      RECT 0.216 14.064 154.060 14.160 ;
      RECT 0.216 14.832 154.060 14.928 ;
      RECT 0.216 15.600 154.060 15.696 ;
      RECT 0.216 16.368 154.060 16.464 ;
      RECT 0.216 17.136 154.060 17.232 ;
      RECT 0.216 17.904 154.060 18.000 ;
      RECT 0.216 18.672 154.060 18.768 ;
      RECT 0.216 19.440 154.060 19.536 ;
      RECT 0.216 20.208 154.060 20.304 ;
      RECT 0.216 20.976 154.060 21.072 ;
      RECT 0.216 21.744 154.060 21.840 ;
      RECT 0.216 22.512 154.060 22.608 ;
      RECT 0.216 23.280 154.060 23.376 ;
      RECT 0.216 24.048 154.060 24.144 ;
      RECT 0.216 24.816 154.060 24.912 ;
      RECT 0.216 25.584 154.060 25.680 ;
      RECT 0.216 26.352 154.060 26.448 ;
      RECT 0.216 27.120 154.060 27.216 ;
      RECT 0.216 27.888 154.060 27.984 ;
      RECT 0.216 28.656 154.060 28.752 ;
      RECT 0.216 29.424 154.060 29.520 ;
      RECT 0.216 30.192 154.060 30.288 ;
      RECT 0.216 30.960 154.060 31.056 ;
      RECT 0.216 31.728 154.060 31.824 ;
      RECT 0.216 32.496 154.060 32.592 ;
      RECT 0.216 33.264 154.060 33.360 ;
      RECT 0.216 34.032 154.060 34.128 ;
      RECT 0.216 34.800 154.060 34.896 ;
      RECT 0.216 35.568 154.060 35.664 ;
      RECT 0.216 36.336 154.060 36.432 ;
      RECT 0.216 37.104 154.060 37.200 ;
      RECT 0.216 37.872 154.060 37.968 ;
      RECT 0.216 38.640 154.060 38.736 ;
      RECT 0.216 39.408 154.060 39.504 ;
      RECT 0.216 40.176 154.060 40.272 ;
      RECT 0.216 40.944 154.060 41.040 ;
      RECT 0.216 41.712 154.060 41.808 ;
      RECT 0.216 42.480 154.060 42.576 ;
      RECT 0.216 43.248 154.060 43.344 ;
      RECT 0.216 44.016 154.060 44.112 ;
      RECT 0.216 44.784 154.060 44.880 ;
      RECT 0.216 45.552 154.060 45.648 ;
      RECT 0.216 46.320 154.060 46.416 ;
      RECT 0.216 47.088 154.060 47.184 ;
      RECT 0.216 47.856 154.060 47.952 ;
      RECT 0.216 48.624 154.060 48.720 ;
      RECT 0.216 49.392 154.060 49.488 ;
      RECT 0.216 50.160 154.060 50.256 ;
      RECT 0.216 50.928 154.060 51.024 ;
      RECT 0.216 51.696 154.060 51.792 ;
      RECT 0.216 52.464 154.060 52.560 ;
      RECT 0.216 53.232 154.060 53.328 ;
      RECT 0.216 54.000 154.060 54.096 ;
      RECT 0.216 54.768 154.060 54.864 ;
      RECT 0.216 55.536 154.060 55.632 ;
      RECT 0.216 56.304 154.060 56.400 ;
      RECT 0.216 57.072 154.060 57.168 ;
      RECT 0.216 57.840 154.060 57.936 ;
      RECT 0.216 58.608 154.060 58.704 ;
      RECT 0.216 59.376 154.060 59.472 ;
      RECT 0.216 60.144 154.060 60.240 ;
      RECT 0.216 60.912 154.060 61.008 ;
      RECT 0.216 61.680 154.060 61.776 ;
      RECT 0.216 62.448 154.060 62.544 ;
      RECT 0.216 63.216 154.060 63.312 ;
      RECT 0.216 63.984 154.060 64.080 ;
      RECT 0.216 64.752 154.060 64.848 ;
      RECT 0.216 65.520 154.060 65.616 ;
      RECT 0.216 66.288 154.060 66.384 ;
      RECT 0.216 67.056 154.060 67.152 ;
      RECT 0.216 67.824 154.060 67.920 ;
      RECT 0.216 68.592 154.060 68.688 ;
      RECT 0.216 69.360 154.060 69.456 ;
      RECT 0.216 70.128 154.060 70.224 ;
      RECT 0.216 70.896 154.060 70.992 ;
      RECT 0.216 71.664 154.060 71.760 ;
      RECT 0.216 72.432 154.060 72.528 ;
      RECT 0.216 73.200 154.060 73.296 ;
      RECT 0.216 73.968 154.060 74.064 ;
      RECT 0.216 74.736 154.060 74.832 ;
      RECT 0.216 75.504 154.060 75.600 ;
      RECT 0.216 76.272 154.060 76.368 ;
      RECT 0.216 77.040 154.060 77.136 ;
      RECT 0.216 77.808 154.060 77.904 ;
      RECT 0.216 78.576 154.060 78.672 ;
      RECT 0.216 79.344 154.060 79.440 ;
      RECT 0.216 80.112 154.060 80.208 ;
      RECT 0.216 80.880 154.060 80.976 ;
      RECT 0.216 81.648 154.060 81.744 ;
      RECT 0.216 82.416 154.060 82.512 ;
      RECT 0.216 83.184 154.060 83.280 ;
      RECT 0.216 83.952 154.060 84.048 ;
      RECT 0.216 84.720 154.060 84.816 ;
      RECT 0.216 85.488 154.060 85.584 ;
      RECT 0.216 86.256 154.060 86.352 ;
      RECT 0.216 87.024 154.060 87.120 ;
      RECT 0.216 87.792 154.060 87.888 ;
      RECT 0.216 88.560 154.060 88.656 ;
      RECT 0.216 89.328 154.060 89.424 ;
      RECT 0.216 90.096 154.060 90.192 ;
      RECT 0.216 90.864 154.060 90.960 ;
      RECT 0.216 91.632 154.060 91.728 ;
      RECT 0.216 92.400 154.060 92.496 ;
      RECT 0.216 93.168 154.060 93.264 ;
      RECT 0.216 93.936 154.060 94.032 ;
      RECT 0.216 94.704 154.060 94.800 ;
      RECT 0.216 95.472 154.060 95.568 ;
      RECT 0.216 96.240 154.060 96.336 ;
      RECT 0.216 97.008 154.060 97.104 ;
      RECT 0.216 97.776 154.060 97.872 ;
      RECT 0.216 98.544 154.060 98.640 ;
      RECT 0.216 99.312 154.060 99.408 ;
      RECT 0.216 100.080 154.060 100.176 ;
      RECT 0.216 100.848 154.060 100.944 ;
      RECT 0.216 101.616 154.060 101.712 ;
      RECT 0.216 102.384 154.060 102.480 ;
      RECT 0.216 103.152 154.060 103.248 ;
      RECT 0.216 103.920 154.060 104.016 ;
      RECT 0.216 104.688 154.060 104.784 ;
      RECT 0.216 105.456 154.060 105.552 ;
      RECT 0.216 106.224 154.060 106.320 ;
      RECT 0.216 106.992 154.060 107.088 ;
      RECT 0.216 107.760 154.060 107.856 ;
      RECT 0.216 108.528 154.060 108.624 ;
      RECT 0.216 109.296 154.060 109.392 ;
      RECT 0.216 110.064 154.060 110.160 ;
      RECT 0.216 110.832 154.060 110.928 ;
      RECT 0.216 111.600 154.060 111.696 ;
      RECT 0.216 112.368 154.060 112.464 ;
      RECT 0.216 113.136 154.060 113.232 ;
      RECT 0.216 113.904 154.060 114.000 ;
      RECT 0.216 114.672 154.060 114.768 ;
      RECT 0.216 115.440 154.060 115.536 ;
      RECT 0.216 116.208 154.060 116.304 ;
      RECT 0.216 116.976 154.060 117.072 ;
      RECT 0.216 117.744 154.060 117.840 ;
      RECT 0.216 118.512 154.060 118.608 ;
      RECT 0.216 119.280 154.060 119.376 ;
      RECT 0.216 120.048 154.060 120.144 ;
      RECT 0.216 120.816 154.060 120.912 ;
      RECT 0.216 121.584 154.060 121.680 ;
      RECT 0.216 122.352 154.060 122.448 ;
      RECT 0.216 123.120 154.060 123.216 ;
      RECT 0.216 123.888 154.060 123.984 ;
      RECT 0.216 124.656 154.060 124.752 ;
      RECT 0.216 125.424 154.060 125.520 ;
      RECT 0.216 126.192 154.060 126.288 ;
      RECT 0.216 126.960 154.060 127.056 ;
      RECT 0.216 127.728 154.060 127.824 ;
      RECT 0.216 128.496 154.060 128.592 ;
      RECT 0.216 129.264 154.060 129.360 ;
      RECT 0.216 130.032 154.060 130.128 ;
      RECT 0.216 130.800 154.060 130.896 ;
      RECT 0.216 131.568 154.060 131.664 ;
      RECT 0.216 132.336 154.060 132.432 ;
      RECT 0.216 133.104 154.060 133.200 ;
      RECT 0.216 133.872 154.060 133.968 ;
      RECT 0.216 134.640 154.060 134.736 ;
      RECT 0.216 135.408 154.060 135.504 ;
      RECT 0.216 136.176 154.060 136.272 ;
      RECT 0.216 136.944 154.060 137.040 ;
      RECT 0.216 137.712 154.060 137.808 ;
      RECT 0.216 138.480 154.060 138.576 ;
      RECT 0.216 139.248 154.060 139.344 ;
      RECT 0.216 140.016 154.060 140.112 ;
      RECT 0.216 140.784 154.060 140.880 ;
      RECT 0.216 141.552 154.060 141.648 ;
      RECT 0.216 142.320 154.060 142.416 ;
      RECT 0.216 143.088 154.060 143.184 ;
      RECT 0.216 143.856 154.060 143.952 ;
      RECT 0.216 144.624 154.060 144.720 ;
      RECT 0.216 145.392 154.060 145.488 ;
      RECT 0.216 146.160 154.060 146.256 ;
      RECT 0.216 146.928 154.060 147.024 ;
      RECT 0.216 147.696 154.060 147.792 ;
      RECT 0.216 148.464 154.060 148.560 ;
      RECT 0.216 149.232 154.060 149.328 ;
      RECT 0.216 150.000 154.060 150.096 ;
      RECT 0.216 150.768 154.060 150.864 ;
      RECT 0.216 151.536 154.060 151.632 ;
      RECT 0.216 152.304 154.060 152.400 ;
      RECT 0.216 153.072 154.060 153.168 ;
      RECT 0.216 153.840 154.060 153.936 ;
      RECT 0.216 154.608 154.060 154.704 ;
      RECT 0.216 155.376 154.060 155.472 ;
      RECT 0.216 156.144 154.060 156.240 ;
      RECT 0.216 156.912 154.060 157.008 ;
      RECT 0.216 157.680 154.060 157.776 ;
      RECT 0.216 158.448 154.060 158.544 ;
      RECT 0.216 159.216 154.060 159.312 ;
      RECT 0.216 159.984 154.060 160.080 ;
      RECT 0.216 160.752 154.060 160.848 ;
      RECT 0.216 161.520 154.060 161.616 ;
      RECT 0.216 162.288 154.060 162.384 ;
      RECT 0.216 163.056 154.060 163.152 ;
      RECT 0.216 163.824 154.060 163.920 ;
      RECT 0.216 164.592 154.060 164.688 ;
      RECT 0.216 165.360 154.060 165.456 ;
      RECT 0.216 166.128 154.060 166.224 ;
      RECT 0.216 166.896 154.060 166.992 ;
      RECT 0.216 167.664 154.060 167.760 ;
      RECT 0.216 168.432 154.060 168.528 ;
      RECT 0.216 169.200 154.060 169.296 ;
      RECT 0.216 169.968 154.060 170.064 ;
      RECT 0.216 170.736 154.060 170.832 ;
      RECT 0.216 171.504 154.060 171.600 ;
      RECT 0.216 172.272 154.060 172.368 ;
      RECT 0.216 173.040 154.060 173.136 ;
      RECT 0.216 173.808 154.060 173.904 ;
      RECT 0.216 174.576 154.060 174.672 ;
      RECT 0.216 175.344 154.060 175.440 ;
      RECT 0.216 176.112 154.060 176.208 ;
      RECT 0.216 176.880 154.060 176.976 ;
      RECT 0.216 177.648 154.060 177.744 ;
      RECT 0.216 178.416 154.060 178.512 ;
      RECT 0.216 179.184 154.060 179.280 ;
      RECT 0.216 179.952 154.060 180.048 ;
      RECT 0.216 180.720 154.060 180.816 ;
      RECT 0.216 181.488 154.060 181.584 ;
      RECT 0.216 182.256 154.060 182.352 ;
      RECT 0.216 183.024 154.060 183.120 ;
      RECT 0.216 183.792 154.060 183.888 ;
      RECT 0.216 184.560 154.060 184.656 ;
      RECT 0.216 185.328 154.060 185.424 ;
      RECT 0.216 186.096 154.060 186.192 ;
      RECT 0.216 186.864 154.060 186.960 ;
      RECT 0.216 187.632 154.060 187.728 ;
      RECT 0.216 188.400 154.060 188.496 ;
      RECT 0.216 189.168 154.060 189.264 ;
      RECT 0.216 189.936 154.060 190.032 ;
      RECT 0.216 190.704 154.060 190.800 ;
      RECT 0.216 191.472 154.060 191.568 ;
      RECT 0.216 192.240 154.060 192.336 ;
      RECT 0.216 193.008 154.060 193.104 ;
      RECT 0.216 193.776 154.060 193.872 ;
      RECT 0.216 194.544 154.060 194.640 ;
      RECT 0.216 195.312 154.060 195.408 ;
      RECT 0.216 196.080 154.060 196.176 ;
      RECT 0.216 196.848 154.060 196.944 ;
      RECT 0.216 197.616 154.060 197.712 ;
      RECT 0.216 198.384 154.060 198.480 ;
      RECT 0.216 199.152 154.060 199.248 ;
      RECT 0.216 199.920 154.060 200.016 ;
      RECT 0.216 200.688 154.060 200.784 ;
      RECT 0.216 201.456 154.060 201.552 ;
      RECT 0.216 202.224 154.060 202.320 ;
      RECT 0.216 202.992 154.060 203.088 ;
      RECT 0.216 203.760 154.060 203.856 ;
      RECT 0.216 204.528 154.060 204.624 ;
      RECT 0.216 205.296 154.060 205.392 ;
      RECT 0.216 206.064 154.060 206.160 ;
      RECT 0.216 206.832 154.060 206.928 ;
      RECT 0.216 207.600 154.060 207.696 ;
      RECT 0.216 208.368 154.060 208.464 ;
      RECT 0.216 209.136 154.060 209.232 ;
      RECT 0.216 209.904 154.060 210.000 ;
      RECT 0.216 210.672 154.060 210.768 ;
      RECT 0.216 211.440 154.060 211.536 ;
      RECT 0.216 212.208 154.060 212.304 ;
      RECT 0.216 212.976 154.060 213.072 ;
      RECT 0.216 213.744 154.060 213.840 ;
    END
  END VDD
  OBS
    LAYER M1 ;
    RECT 0 0 154.276 214.273 ;
    LAYER M2 ;
    RECT 0 0 154.276 214.273 ;
    LAYER M3 ;
    RECT 0 0 154.276 214.273 ;
    LAYER M4 ;
    RECT 0 0 154.276 214.273 ;
  END
END fakeram_512x1024_1r1w

END LIBRARY
